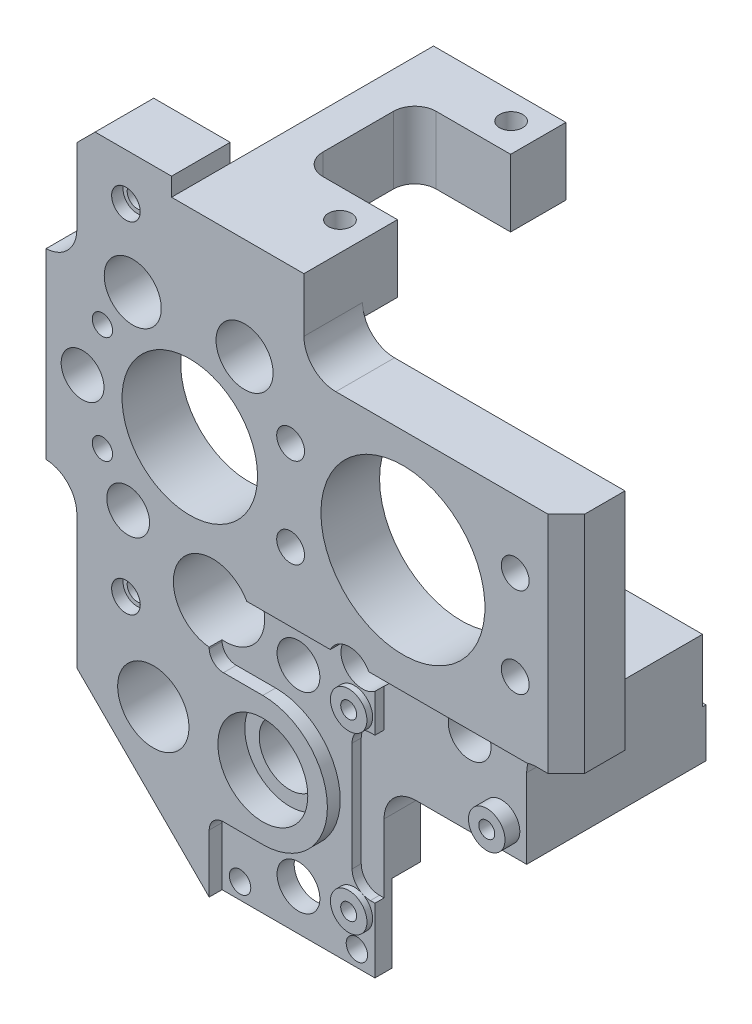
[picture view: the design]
ISO-10303-21;
HEADER;
FILE_DESCRIPTION(('STEP AP214'),'2;1');
FILE_NAME('part.step','',(''),(''),'','','');
FILE_SCHEMA(('AUTOMOTIVE_DESIGN { 1 0 10303 214 1 1 1 1 }'));
ENDSEC;
DATA;
#1=APPLICATION_CONTEXT('core data for automotive mechanical design processes');
#2=APPLICATION_PROTOCOL_DEFINITION('international standard','automotive_design',2000,#1);
#3=PRODUCT_CONTEXT('',#1,'mechanical');
#4=PRODUCT('Part','Part','',(#3));
#5=PRODUCT_RELATED_PRODUCT_CATEGORY('part','',(#4));
#6=PRODUCT_DEFINITION_FORMATION('','',#4);
#7=PRODUCT_DEFINITION_CONTEXT('part definition',#1,'design');
#8=PRODUCT_DEFINITION('design','',#6,#7);
#9=PRODUCT_DEFINITION_SHAPE('','',#8);
#10=(LENGTH_UNIT() NAMED_UNIT(*) SI_UNIT(.MILLI.,.METRE.));
#11=(NAMED_UNIT(*) PLANE_ANGLE_UNIT() SI_UNIT($,.RADIAN.));
#12=(NAMED_UNIT(*) SI_UNIT($,.STERADIAN.) SOLID_ANGLE_UNIT());
#13=UNCERTAINTY_MEASURE_WITH_UNIT(LENGTH_MEASURE(1.E-05),#10,'distance_accuracy_value','');
#14=(GEOMETRIC_REPRESENTATION_CONTEXT(3) GLOBAL_UNCERTAINTY_ASSIGNED_CONTEXT((#13)) GLOBAL_UNIT_ASSIGNED_CONTEXT((#10,
#11,#12)) REPRESENTATION_CONTEXT('',''));
#15=CARTESIAN_POINT('',(0.,0.,0.));
#16=DIRECTION('',(0.,0.,1.));
#17=DIRECTION('',(1.,0.,0.));
#18=AXIS2_PLACEMENT_3D('',#15,#16,#17);
#19=CARTESIAN_POINT('',(-16.51,-18.941358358,6.528054));
#20=DIRECTION('',(0.,0.,1.));
#21=DIRECTION('',(1.,0.,0.));
#22=AXIS2_PLACEMENT_3D('',#19,#20,#21);
#23=CYLINDRICAL_SURFACE('',#22,1.13029999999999);
#24=CARTESIAN_POINT('',(-16.51,-18.941358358,0.));
#25=DIRECTION('',(0.,0.,1.));
#26=DIRECTION('',(1.,0.,0.));
#27=AXIS2_PLACEMENT_3D('',#24,#25,#26);
#28=CIRCLE('',#27,1.13029999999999);
#29=CARTESIAN_POINT('',(-15.3797,-18.941358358,0.));
#30=VERTEX_POINT('',#29);
#31=EDGE_CURVE('E518',#30,#30,#28,.T.);
#32=ORIENTED_EDGE('',*,*,#31,.F.);
#33=EDGE_LOOP('',(#32));
#34=FACE_BOUND('',#33,.T.);
#35=CARTESIAN_POINT('',(-16.51,-18.941358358,5.258054));
#36=DIRECTION('',(0.,0.,1.));
#37=DIRECTION('',(1.,0.,0.));
#38=AXIS2_PLACEMENT_3D('',#35,#36,#37);
#39=CIRCLE('',#38,1.13029999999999);
#40=CARTESIAN_POINT('',(-15.3797,-18.941358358,5.258054));
#41=VERTEX_POINT('',#40);
#42=EDGE_CURVE('E38',#41,#41,#39,.F.);
#43=ORIENTED_EDGE('',*,*,#42,.F.);
#44=EDGE_LOOP('',(#43));
#45=FACE_BOUND('',#44,.T.);
#46=ADVANCED_FACE('F34',(#34,#45),#23,.F.);
#47=CARTESIAN_POINT('',(-16.51,18.941358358,6.528054));
#48=DIRECTION('',(0.,0.,1.));
#49=DIRECTION('',(1.,0.,0.));
#50=AXIS2_PLACEMENT_3D('',#47,#48,#49);
#51=CYLINDRICAL_SURFACE('',#50,1.13029999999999);
#52=CARTESIAN_POINT('',(-16.51,18.941358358,0.));
#53=DIRECTION('',(0.,0.,1.));
#54=DIRECTION('',(1.,0.,0.));
#55=AXIS2_PLACEMENT_3D('',#52,#53,#54);
#56=CIRCLE('',#55,1.13029999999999);
#57=CARTESIAN_POINT('',(-15.3797,18.941358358,0.));
#58=VERTEX_POINT('',#57);
#59=EDGE_CURVE('E497',#58,#58,#56,.T.);
#60=ORIENTED_EDGE('',*,*,#59,.F.);
#61=EDGE_LOOP('',(#60));
#62=FACE_BOUND('',#61,.T.);
#63=CARTESIAN_POINT('',(-16.51,18.941358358,5.258054));
#64=DIRECTION('',(0.,0.,1.));
#65=DIRECTION('',(1.,0.,0.));
#66=AXIS2_PLACEMENT_3D('',#63,#64,#65);
#67=CIRCLE('',#66,1.13029999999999);
#68=CARTESIAN_POINT('',(-15.3797,18.941358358,5.258054));
#69=VERTEX_POINT('',#68);
#70=EDGE_CURVE('E438',#69,#69,#67,.F.);
#71=ORIENTED_EDGE('',*,*,#70,.F.);
#72=EDGE_LOOP('',(#71));
#73=FACE_BOUND('',#72,.T.);
#74=ADVANCED_FACE('F962',(#62,#73),#51,.F.);
#75=CARTESIAN_POINT('',(-7.23900000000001,-15.20698,5.73405));
#76=DIRECTION('',(-1.,0.,0.));
#77=DIRECTION('',(0.,-1.,0.));
#78=AXIS2_PLACEMENT_3D('',#75,#76,#77);
#79=PLANE('',#78);
#80=DIRECTION('',(0.,0.,-1.));
#81=VECTOR('',#80,1.);
#82=CARTESIAN_POINT('',(-7.23900000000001,-36.80968,28.3966203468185));
#83=LINE('',#82,#81);
#84=CARTESIAN_POINT('',(-7.23900000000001,-36.80968,6.5278));
#85=VERTEX_POINT('',#84);
#86=CARTESIAN_POINT('',(-7.23900000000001,-36.80968,5.09905));
#87=VERTEX_POINT('',#86);
#88=EDGE_CURVE('E51',#85,#87,#83,.T.);
#89=ORIENTED_EDGE('',*,*,#88,.F.);
#90=DIRECTION('',(0.,-1.,0.));
#91=VECTOR('',#90,1.);
#92=CARTESIAN_POINT('',(-7.23900000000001,-15.20698,6.5278));
#93=LINE('',#92,#91);
#94=CARTESIAN_POINT('',(-7.239,-43.27398,6.5278));
#95=VERTEX_POINT('',#94);
#96=EDGE_CURVE('E732',#85,#95,#93,.T.);
#97=ORIENTED_EDGE('',*,*,#96,.T.);
#98=DIRECTION('',(0.,0.,1.));
#99=VECTOR('',#98,1.);
#100=CARTESIAN_POINT('',(-7.239,-43.27398,5.73405));
#101=LINE('',#100,#99);
#102=CARTESIAN_POINT('',(-7.23900000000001,-43.27398,5.09905));
#103=VERTEX_POINT('',#102);
#104=EDGE_CURVE('E734',#103,#95,#101,.T.);
#105=ORIENTED_EDGE('',*,*,#104,.F.);
#106=DIRECTION('',(0.,-1.,0.));
#107=VECTOR('',#106,1.);
#108=CARTESIAN_POINT('',(-7.23900000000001,-15.20698,5.09905));
#109=LINE('',#108,#107);
#110=EDGE_CURVE('E674',#87,#103,#109,.T.);
#111=ORIENTED_EDGE('',*,*,#110,.F.);
#112=EDGE_LOOP('',(#89,#97,#105,#111));
#113=FACE_BOUND('',#112,.T.);
#114=ADVANCED_FACE('F968',(#113),#79,.F.);
#115=DIRECTION('',(0.,0.,-1.));
#116=VECTOR('',#115,1.);
#117=CARTESIAN_POINT('',(-7.23900000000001,-19.3416122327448,28.3966203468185));
#118=LINE('',#117,#116);
#119=CARTESIAN_POINT('',(-7.23900000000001,-19.3416122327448,6.5278));
#120=VERTEX_POINT('',#119);
#121=CARTESIAN_POINT('',(-7.23900000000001,-19.3416122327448,5.09905));
#122=VERTEX_POINT('',#121);
#123=EDGE_CURVE('E495',#120,#122,#118,.T.);
#124=ORIENTED_EDGE('',*,*,#123,.T.);
#125=CARTESIAN_POINT('',(-7.23900000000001,-19.1749477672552,5.09905));
#126=VERTEX_POINT('',#125);
#127=EDGE_CURVE('E675',#126,#122,#109,.T.);
#128=ORIENTED_EDGE('',*,*,#127,.F.);
#129=DIRECTION('',(0.,0.,-1.));
#130=VECTOR('',#129,1.);
#131=CARTESIAN_POINT('',(-7.23900000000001,-19.1749477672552,0.));
#132=LINE('',#131,#130);
#133=CARTESIAN_POINT('',(-7.23900000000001,-19.1749477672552,6.5278));
#134=VERTEX_POINT('',#133);
#135=EDGE_CURVE('E653',#126,#134,#132,.F.);
#136=ORIENTED_EDGE('',*,*,#135,.T.);
#137=EDGE_CURVE('E59',#134,#120,#93,.T.);
#138=ORIENTED_EDGE('',*,*,#137,.T.);
#139=EDGE_LOOP('',(#124,#128,#136,#138));
#140=FACE_BOUND('',#139,.T.);
#141=ADVANCED_FACE('F1098',(#140),#79,.F.);
#142=CARTESIAN_POINT('',(-4.69900000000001,-15.20698,5.09905));
#143=DIRECTION('',(0.,0.,-1.));
#144=DIRECTION('',(-1.,0.,0.));
#145=AXIS2_PLACEMENT_3D('',#142,#143,#144);
#146=PLANE('',#145);
#147=CARTESIAN_POINT('',(1.27,-38.70198,5.09905));
#148=DIRECTION('',(0.,0.,-1.));
#149=DIRECTION('',(-1.,0.,0.));
#150=AXIS2_PLACEMENT_3D('',#147,#148,#149);
#151=CIRCLE('',#150,2.38124999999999);
#152=CARTESIAN_POINT('',(-1.11124999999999,-38.70198,5.09905));
#153=VERTEX_POINT('',#152);
#154=EDGE_CURVE('E625',#153,#153,#151,.T.);
#155=ORIENTED_EDGE('',*,*,#154,.T.);
#156=EDGE_LOOP('',(#155));
#157=FACE_BOUND('',#156,.T.);
#158=CARTESIAN_POINT('',(1.27,-17.36598,5.09905));
#159=DIRECTION('',(0.,0.,-1.));
#160=DIRECTION('',(-1.,0.,0.));
#161=AXIS2_PLACEMENT_3D('',#158,#159,#160);
#162=CIRCLE('',#161,2.38124999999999);
#163=CARTESIAN_POINT('',(-1.11124999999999,-17.36598,5.09905));
#164=VERTEX_POINT('',#163);
#165=EDGE_CURVE('E614',#164,#164,#162,.T.);
#166=ORIENTED_EDGE('',*,*,#165,.T.);
#167=EDGE_LOOP('',(#166));
#168=FACE_BOUND('',#167,.T.);
#169=CARTESIAN_POINT('',(-5.23000000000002,-41.49598,5.09905));
#170=DIRECTION('',(0.,0.,-1.));
#171=DIRECTION('',(-1.,0.,0.));
#172=AXIS2_PLACEMENT_3D('',#169,#170,#171);
#173=CIRCLE('',#172,1.190625);
#174=CARTESIAN_POINT('',(-4.03937500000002,-41.49598,5.09905));
#175=VERTEX_POINT('',#174);
#176=EDGE_CURVE('E557',#175,#175,#173,.T.);
#177=ORIENTED_EDGE('',*,*,#176,.T.);
#178=EDGE_LOOP('',(#177));
#179=FACE_BOUND('',#178,.T.);
#180=CARTESIAN_POINT('',(7.77,-41.49598,5.09905));
#181=DIRECTION('',(0.,0.,-1.));
#182=DIRECTION('',(-1.,0.,0.));
#183=AXIS2_PLACEMENT_3D('',#180,#181,#182);
#184=CIRCLE('',#183,1.190625);
#185=CARTESIAN_POINT('',(8.960625,-41.49598,5.09905));
#186=VERTEX_POINT('',#185);
#187=EDGE_CURVE('E551',#186,#186,#184,.T.);
#188=ORIENTED_EDGE('',*,*,#187,.T.);
#189=EDGE_LOOP('',(#188));
#190=FACE_BOUND('',#189,.T.);
#191=CARTESIAN_POINT('',(-5.65150000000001,-36.80968,5.09905));
#192=DIRECTION('',(0.,0.,-1.));
#193=DIRECTION('',(1.,0.,0.));
#194=AXIS2_PLACEMENT_3D('',#191,#192,#193);
#195=CIRCLE('',#194,1.5875);
#196=CARTESIAN_POINT('',(-5.65150000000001,-35.22218,5.09905));
#197=VERTEX_POINT('',#196);
#198=EDGE_CURVE('E470',#87,#197,#195,.T.);
#199=ORIENTED_EDGE('',*,*,#198,.F.);
#200=ORIENTED_EDGE('',*,*,#110,.T.);
#201=DIRECTION('',(1.,0.,0.));
#202=VECTOR('',#201,1.);
#203=CARTESIAN_POINT('',(-7.23900000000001,-43.27398,5.09905));
#204=LINE('',#203,#202);
#205=CARTESIAN_POINT('',(9.77899999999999,-43.27398,5.09905));
#206=VERTEX_POINT('',#205);
#207=EDGE_CURVE('E677',#103,#206,#204,.T.);
#208=ORIENTED_EDGE('',*,*,#207,.T.);
#209=DIRECTION('',(0.,-1.,0.));
#210=VECTOR('',#209,1.);
#211=CARTESIAN_POINT('',(9.779,-24.892,5.09905));
#212=LINE('',#211,#210);
#213=CARTESIAN_POINT('',(9.779,-36.0635563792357,5.09905));
#214=VERTEX_POINT('',#213);
#215=EDGE_CURVE('E687',#214,#206,#212,.T.);
#216=ORIENTED_EDGE('',*,*,#215,.F.);
#217=DIRECTION('',(1.,0.,0.));
#218=VECTOR('',#217,1.);
#219=CARTESIAN_POINT('',(9.27099999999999,-36.0635563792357,5.09905));
#220=LINE('',#219,#218);
#221=CARTESIAN_POINT('',(9.27099999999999,-36.0635563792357,5.09905));
#222=VERTEX_POINT('',#221);
#223=EDGE_CURVE('E527',#222,#214,#220,.T.);
#224=ORIENTED_EDGE('',*,*,#223,.F.);
#225=CARTESIAN_POINT('',(9.27099999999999,-34.0315563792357,5.09905));
#226=DIRECTION('',(0.,0.,1.));
#227=DIRECTION('',(-1.,0.,0.));
#228=AXIS2_PLACEMENT_3D('',#225,#226,#227);
#229=CIRCLE('',#228,2.032);
#230=CARTESIAN_POINT('',(8.38199999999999,-35.8587681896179,5.09905));
#231=VERTEX_POINT('',#230);
#232=EDGE_CURVE('E524',#231,#222,#229,.T.);
#233=ORIENTED_EDGE('',*,*,#232,.F.);
#234=CARTESIAN_POINT('',(7.49299999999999,-37.68598,5.09905));
#235=DIRECTION('',(0.,0.,1.));
#236=DIRECTION('',(1.,0.,0.));
#237=AXIS2_PLACEMENT_3D('',#234,#235,#236);
#238=CIRCLE('',#237,2.03199999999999);
#239=EDGE_CURVE('E668',#231,#231,#238,.T.);
#240=ORIENTED_EDGE('',*,*,#239,.F.);
#241=CARTESIAN_POINT('',(7.239,-34.0315563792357,5.09905));
#242=VERTEX_POINT('',#241);
#243=EDGE_CURVE('E525',#242,#231,#229,.T.);
#244=ORIENTED_EDGE('',*,*,#243,.F.);
#245=DIRECTION('',(0.,-1.,0.));
#246=VECTOR('',#245,1.);
#247=CARTESIAN_POINT('',(7.239,-34.0315563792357,5.09905));
#248=LINE('',#247,#246);
#249=CARTESIAN_POINT('',(7.239,-21.9094036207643,5.09905));
#250=VERTEX_POINT('',#249);
#251=EDGE_CURVE('E521',#250,#242,#248,.T.);
#252=ORIENTED_EDGE('',*,*,#251,.F.);
#253=CARTESIAN_POINT('',(9.27099999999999,-21.9094036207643,5.09905));
#254=DIRECTION('',(0.,0.,1.));
#255=DIRECTION('',(-1.,0.,0.));
#256=AXIS2_PLACEMENT_3D('',#253,#254,#255);
#257=CIRCLE('',#256,2.032);
#258=CARTESIAN_POINT('',(8.382,-20.0821918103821,5.09905));
#259=VERTEX_POINT('',#258);
#260=EDGE_CURVE('E517',#259,#250,#257,.T.);
#261=ORIENTED_EDGE('',*,*,#260,.F.);
#262=CARTESIAN_POINT('',(7.493,-18.25498,5.09905));
#263=DIRECTION('',(0.,0.,1.));
#264=DIRECTION('',(1.,0.,0.));
#265=AXIS2_PLACEMENT_3D('',#262,#263,#264);
#266=CIRCLE('',#265,2.032);
#267=EDGE_CURVE('E671',#259,#259,#266,.T.);
#268=ORIENTED_EDGE('',*,*,#267,.F.);
#269=CARTESIAN_POINT('',(9.27099999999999,-19.8774036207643,5.09905));
#270=VERTEX_POINT('',#269);
#271=EDGE_CURVE('E519',#270,#259,#257,.T.);
#272=ORIENTED_EDGE('',*,*,#271,.F.);
#273=DIRECTION('',(-1.,0.,0.));
#274=VECTOR('',#273,1.);
#275=CARTESIAN_POINT('',(9.27099999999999,-19.8774036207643,5.09905));
#276=LINE('',#275,#274);
#277=CARTESIAN_POINT('',(9.779,-19.8774036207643,5.09905));
#278=VERTEX_POINT('',#277);
#279=EDGE_CURVE('E514',#278,#270,#276,.T.);
#280=ORIENTED_EDGE('',*,*,#279,.F.);
#281=CARTESIAN_POINT('',(9.779,-15.6444041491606,5.09905));
#282=VERTEX_POINT('',#281);
#283=EDGE_CURVE('E683',#282,#278,#212,.T.);
#284=ORIENTED_EDGE('',*,*,#283,.F.);
#285=CARTESIAN_POINT('',(8.382,-13.716,5.09905));
#286=DIRECTION('',(0.,0.,-1.));
#287=DIRECTION('',(-1.,0.,0.));
#288=AXIS2_PLACEMENT_3D('',#285,#286,#287);
#289=CIRCLE('',#288,2.38124999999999);
#290=CARTESIAN_POINT('',(6.24426554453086,-12.66698,5.09905));
#291=VERTEX_POINT('',#290);
#292=EDGE_CURVE('E606',#282,#291,#289,.T.);
#293=ORIENTED_EDGE('',*,*,#292,.T.);
#294=DIRECTION('',(-1.,0.,0.));
#295=VECTOR('',#294,1.);
#296=CARTESIAN_POINT('',(32.512,-12.66698,5.09905));
#297=LINE('',#296,#295);
#298=CARTESIAN_POINT('',(-3.0636093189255,-12.66698,5.09905));
#299=VERTEX_POINT('',#298);
#300=EDGE_CURVE('E680',#291,#299,#297,.T.);
#301=ORIENTED_EDGE('',*,*,#300,.T.);
#302=CARTESIAN_POINT('',(-6.858,-14.82598,5.09905));
#303=DIRECTION('',(0.,0.,-1.));
#304=DIRECTION('',(-1.,0.,0.));
#305=AXIS2_PLACEMENT_3D('',#302,#303,#304);
#306=CIRCLE('',#305,4.365625);
#307=EDGE_CURVE('E1407',#299,#126,#306,.T.);
#308=ORIENTED_EDGE('',*,*,#307,.T.);
#309=ORIENTED_EDGE('',*,*,#127,.T.);
#310=CARTESIAN_POINT('',(-5.6536886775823,-19.25828,5.09905));
#311=DIRECTION('',(0.,0.,-1.));
#312=DIRECTION('',(1.,0.,0.));
#313=AXIS2_PLACEMENT_3D('',#310,#311,#312);
#314=CIRCLE('',#313,1.5875);
#315=CARTESIAN_POINT('',(-5.6536886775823,-20.84578,5.09905));
#316=VERTEX_POINT('',#315);
#317=EDGE_CURVE('E467',#316,#122,#314,.T.);
#318=ORIENTED_EDGE('',*,*,#317,.F.);
#319=DIRECTION('',(-1.,0.,0.));
#320=VECTOR('',#319,1.);
#321=CARTESIAN_POINT('',(-1.27,-20.84578,5.09905));
#322=LINE('',#321,#320);
#323=CARTESIAN_POINT('',(-1.27,-20.84578,5.09905));
#324=VERTEX_POINT('',#323);
#325=EDGE_CURVE('E479',#324,#316,#322,.T.);
#326=ORIENTED_EDGE('',*,*,#325,.F.);
#327=CARTESIAN_POINT('',(-1.27,-28.03398,5.09905));
#328=DIRECTION('',(0.,0.,1.));
#329=DIRECTION('',(1.,0.,0.));
#330=AXIS2_PLACEMENT_3D('',#327,#328,#329);
#331=CIRCLE('',#330,7.1882);
#332=CARTESIAN_POINT('',(-1.27,-35.22218,5.09905));
#333=VERTEX_POINT('',#332);
#334=EDGE_CURVE('E476',#333,#324,#331,.T.);
#335=ORIENTED_EDGE('',*,*,#334,.F.);
#336=DIRECTION('',(1.,0.,0.));
#337=VECTOR('',#336,1.);
#338=CARTESIAN_POINT('',(-1.27,-35.22218,5.09905));
#339=LINE('',#338,#337);
#340=EDGE_CURVE('E473',#197,#333,#339,.T.);
#341=ORIENTED_EDGE('',*,*,#340,.F.);
#342=EDGE_LOOP('',(#199,#200,#208,#216,#224,#233,#240,#244,#252,#261,#268,#272,#280,#284,#293,
#301,#308,#309,#318,#326,#335,#341));
#343=FACE_BOUND('',#342,.T.);
#344=ADVANCED_FACE('F957',(#157,#168,#179,#190,#343),#146,.F.);
#345=CARTESIAN_POINT('',(9.779,-24.892,6.5278));
#346=DIRECTION('',(-1.,0.,0.));
#347=DIRECTION('',(0.,-1.,0.));
#348=AXIS2_PLACEMENT_3D('',#345,#346,#347);
#349=PLANE('',#348);
#350=ORIENTED_EDGE('',*,*,#283,.T.);
#351=DIRECTION('',(0.,0.,1.));
#352=VECTOR('',#351,1.);
#353=CARTESIAN_POINT('',(9.779,-19.8774036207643,-12.3011845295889));
#354=LINE('',#353,#352);
#355=CARTESIAN_POINT('',(9.779,-19.8774036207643,4.08305));
#356=VERTEX_POINT('',#355);
#357=EDGE_CURVE('E529',#356,#278,#354,.T.);
#358=ORIENTED_EDGE('',*,*,#357,.F.);
#359=DIRECTION('',(0.,-1.,0.));
#360=VECTOR('',#359,1.);
#361=CARTESIAN_POINT('',(9.779,-31.5182040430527,4.08305));
#362=LINE('',#361,#360);
#363=CARTESIAN_POINT('',(9.779,-15.6444041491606,4.08305));
#364=VERTEX_POINT('',#363);
#365=EDGE_CURVE('E567',#364,#356,#362,.T.);
#366=ORIENTED_EDGE('',*,*,#365,.F.);
#367=DIRECTION('',(0.,0.,1.));
#368=VECTOR('',#367,1.);
#369=CARTESIAN_POINT('',(9.779,-15.6444041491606,6.5278));
#370=LINE('',#369,#368);
#371=EDGE_CURVE('E43',#282,#364,#370,.F.);
#372=ORIENTED_EDGE('',*,*,#371,.F.);
#373=EDGE_LOOP('',(#350,#358,#366,#372));
#374=FACE_BOUND('',#373,.T.);
#375=ADVANCED_FACE('F951',(#374),#349,.F.);
#376=CARTESIAN_POINT('',(-25.4,-43.27398,6.5278));
#377=DIRECTION('',(0.,0.,1.));
#378=DIRECTION('',(1.,0.,0.));
#379=AXIS2_PLACEMENT_3D('',#376,#377,#378);
#380=PLANE('',#379);
#381=CARTESIAN_POINT('',(-16.51,-18.941358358,6.5278));
#382=DIRECTION('',(0.,0.,1.));
#383=DIRECTION('',(1.,0.,0.));
#384=AXIS2_PLACEMENT_3D('',#381,#382,#383);
#385=CIRCLE('',#384,1.6002);
#386=CARTESIAN_POINT('',(-14.9098,-18.941358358,6.5278));
#387=VERTEX_POINT('',#386);
#388=EDGE_CURVE('E12',#387,#387,#385,.T.);
#389=ORIENTED_EDGE('',*,*,#388,.F.);
#390=EDGE_LOOP('',(#389));
#391=FACE_BOUND('',#390,.T.);
#392=CARTESIAN_POINT('',(-15.748,10.795,6.5278));
#393=DIRECTION('',(0.,0.,-1.));
#394=DIRECTION('',(-1.,0.,0.));
#395=AXIS2_PLACEMENT_3D('',#392,#393,#394);
#396=CIRCLE('',#395,3.175);
#397=CARTESIAN_POINT('',(-18.923,10.795,6.5278));
#398=VERTEX_POINT('',#397);
#399=EDGE_CURVE('E629',#398,#398,#396,.T.);
#400=ORIENTED_EDGE('',*,*,#399,.T.);
#401=EDGE_LOOP('',(#400));
#402=FACE_BOUND('',#401,.T.);
#403=CARTESIAN_POINT('',(-3.302,10.795,6.5278));
#404=DIRECTION('',(0.,0.,-1.));
#405=DIRECTION('',(-1.,0.,0.));
#406=AXIS2_PLACEMENT_3D('',#403,#404,#405);
#407=CIRCLE('',#406,3.175);
#408=CARTESIAN_POINT('',(-6.477,10.795,6.5278));
#409=VERTEX_POINT('',#408);
#410=EDGE_CURVE('E635',#409,#409,#407,.T.);
#411=ORIENTED_EDGE('',*,*,#410,.T.);
#412=EDGE_LOOP('',(#411));
#413=FACE_BOUND('',#412,.T.);
#414=CARTESIAN_POINT('',(-13.462,-28.03398,6.5278));
#415=DIRECTION('',(0.,0.,-1.));
#416=DIRECTION('',(-1.,0.,0.));
#417=AXIS2_PLACEMENT_3D('',#414,#415,#416);
#418=CIRCLE('',#417,3.96875);
#419=CARTESIAN_POINT('',(-17.43075,-28.03398,6.5278));
#420=VERTEX_POINT('',#419);
#421=EDGE_CURVE('E641',#420,#420,#418,.T.);
#422=ORIENTED_EDGE('',*,*,#421,.T.);
#423=EDGE_LOOP('',(#422));
#424=FACE_BOUND('',#423,.T.);
#425=CARTESIAN_POINT('',(-9.398,0.,6.5278));
#426=DIRECTION('',(0.,0.,1.));
#427=DIRECTION('',(1.,0.,0.));
#428=AXIS2_PLACEMENT_3D('',#425,#426,#427);
#429=CIRCLE('',#428,7.540625);
#430=CARTESIAN_POINT('',(-1.857375,0.,6.5278));
#431=VERTEX_POINT('',#430);
#432=EDGE_CURVE('E658',#431,#431,#429,.T.);
#433=ORIENTED_EDGE('',*,*,#432,.F.);
#434=EDGE_LOOP('',(#433));
#435=FACE_BOUND('',#434,.T.);
#436=CARTESIAN_POINT('',(26.823,5.,6.5278));
#437=DIRECTION('',(0.,0.,1.));
#438=DIRECTION('',(1.,0.,0.));
#439=AXIS2_PLACEMENT_3D('',#436,#437,#438);
#440=CIRCLE('',#439,1.54999999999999);
#441=CARTESIAN_POINT('',(28.373,5.,6.5278));
#442=VERTEX_POINT('',#441);
#443=EDGE_CURVE('E757',#442,#442,#440,.T.);
#444=ORIENTED_EDGE('',*,*,#443,.F.);
#445=EDGE_LOOP('',(#444));
#446=FACE_BOUND('',#445,.T.);
#447=CARTESIAN_POINT('',(1.82299999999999,-5.,6.5278));
#448=DIRECTION('',(0.,0.,1.));
#449=DIRECTION('',(1.,0.,0.));
#450=AXIS2_PLACEMENT_3D('',#447,#448,#449);
#451=CIRCLE('',#450,1.54999999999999);
#452=CARTESIAN_POINT('',(3.37299999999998,-5.,6.5278));
#453=VERTEX_POINT('',#452);
#454=EDGE_CURVE('E753',#453,#453,#451,.T.);
#455=ORIENTED_EDGE('',*,*,#454,.F.);
#456=EDGE_LOOP('',(#455));
#457=FACE_BOUND('',#456,.T.);
#458=CARTESIAN_POINT('',(1.82299999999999,5.,6.5278));
#459=DIRECTION('',(0.,0.,1.));
#460=DIRECTION('',(1.,0.,0.));
#461=AXIS2_PLACEMENT_3D('',#458,#459,#460);
#462=CIRCLE('',#461,1.54999999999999);
#463=CARTESIAN_POINT('',(3.37299999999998,5.,6.5278));
#464=VERTEX_POINT('',#463);
#465=EDGE_CURVE('E749',#464,#464,#462,.T.);
#466=ORIENTED_EDGE('',*,*,#465,.F.);
#467=EDGE_LOOP('',(#466));
#468=FACE_BOUND('',#467,.T.);
#469=CARTESIAN_POINT('',(26.823,-5.,6.5278));
#470=DIRECTION('',(0.,0.,1.));
#471=DIRECTION('',(1.,0.,0.));
#472=AXIS2_PLACEMENT_3D('',#469,#470,#471);
#473=CIRCLE('',#472,1.54999999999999);
#474=CARTESIAN_POINT('',(28.373,-5.,6.5278));
#475=VERTEX_POINT('',#474);
#476=EDGE_CURVE('E745',#475,#475,#473,.T.);
#477=ORIENTED_EDGE('',*,*,#476,.F.);
#478=EDGE_LOOP('',(#477));
#479=FACE_BOUND('',#478,.T.);
#480=CARTESIAN_POINT('',(-19.1232329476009,5.96899994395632,6.5278));
#481=DIRECTION('',(0.,0.,1.));
#482=DIRECTION('',(1.,0.,0.));
#483=AXIS2_PLACEMENT_3D('',#480,#481,#482);
#484=CIRCLE('',#483,1.13029999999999);
#485=CARTESIAN_POINT('',(-17.9929329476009,5.96899994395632,6.5278));
#486=VERTEX_POINT('',#485);
#487=EDGE_CURVE('E741',#486,#486,#484,.T.);
#488=ORIENTED_EDGE('',*,*,#487,.F.);
#489=EDGE_LOOP('',(#488));
#490=FACE_BOUND('',#489,.T.);
#491=CARTESIAN_POINT('',(-19.1232329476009,-5.96900005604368,6.5278));
#492=DIRECTION('',(0.,0.,1.));
#493=DIRECTION('',(1.,0.,0.));
#494=AXIS2_PLACEMENT_3D('',#491,#492,#493);
#495=CIRCLE('',#494,1.13029999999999);
#496=CARTESIAN_POINT('',(-17.9929329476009,-5.96900005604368,6.5278));
#497=VERTEX_POINT('',#496);
#498=EDGE_CURVE('E737',#497,#497,#495,.T.);
#499=ORIENTED_EDGE('',*,*,#498,.F.);
#500=EDGE_LOOP('',(#499));
#501=FACE_BOUND('',#500,.T.);
#502=CARTESIAN_POINT('',(14.323,0.,6.5278));
#503=DIRECTION('',(0.,0.,-1.));
#504=DIRECTION('',(-1.,0.,0.));
#505=AXIS2_PLACEMENT_3D('',#502,#503,#504);
#506=CIRCLE('',#505,9.128125);
#507=CARTESIAN_POINT('',(5.19487499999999,0.,6.5278));
#508=VERTEX_POINT('',#507);
#509=EDGE_CURVE('E662',#508,#508,#506,.T.);
#510=ORIENTED_EDGE('',*,*,#509,.T.);
#511=EDGE_LOOP('',(#510));
#512=FACE_BOUND('',#511,.T.);
#513=CARTESIAN_POINT('',(-21.336,0.,6.5278));
#514=DIRECTION('',(0.,0.,1.));
#515=DIRECTION('',(1.,0.,0.));
#516=AXIS2_PLACEMENT_3D('',#513,#514,#515);
#517=CIRCLE('',#516,2.38124999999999);
#518=CARTESIAN_POINT('',(-18.95475,0.,6.5278));
#519=VERTEX_POINT('',#518);
#520=EDGE_CURVE('E624',#519,#519,#517,.T.);
#521=ORIENTED_EDGE('',*,*,#520,.F.);
#522=EDGE_LOOP('',(#521));
#523=FACE_BOUND('',#522,.T.);
#524=CARTESIAN_POINT('',(-16.256,-10.50798,6.5278));
#525=DIRECTION('',(0.,0.,1.));
#526=DIRECTION('',(1.,0.,0.));
#527=AXIS2_PLACEMENT_3D('',#524,#525,#526);
#528=CIRCLE('',#527,2.38124999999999);
#529=CARTESIAN_POINT('',(-13.87475,-10.50798,6.5278));
#530=VERTEX_POINT('',#529);
#531=EDGE_CURVE('E617',#530,#530,#528,.T.);
#532=ORIENTED_EDGE('',*,*,#531,.F.);
#533=EDGE_LOOP('',(#532));
#534=FACE_BOUND('',#533,.T.);
#535=DIRECTION('',(1.,0.,0.));
#536=VECTOR('',#535,1.);
#537=CARTESIAN_POINT('',(3.302,22.098,6.5278));
#538=LINE('',#537,#536);
#539=CARTESIAN_POINT('',(-11.43,22.098,6.5278));
#540=VERTEX_POINT('',#539);
#541=CARTESIAN_POINT('',(3.302,22.098,6.5278));
#542=VERTEX_POINT('',#541);
#543=EDGE_CURVE('E801',#540,#542,#538,.T.);
#544=ORIENTED_EDGE('',*,*,#543,.F.);
#545=DIRECTION('',(0.,1.,0.));
#546=VECTOR('',#545,1.);
#547=CARTESIAN_POINT('',(-11.43,-7.50040104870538,6.5278));
#548=LINE('',#547,#546);
#549=CARTESIAN_POINT('',(-11.43,24.13,6.5278));
#550=VERTEX_POINT('',#549);
#551=EDGE_CURVE('E591',#540,#550,#548,.T.);
#552=ORIENTED_EDGE('',*,*,#551,.T.);
#553=DIRECTION('',(-1.,0.,0.));
#554=VECTOR('',#553,1.);
#555=CARTESIAN_POINT('',(-25.4,24.13,6.5278));
#556=LINE('',#555,#554);
#557=CARTESIAN_POINT('',(-19.939,24.13,6.5278));
#558=VERTEX_POINT('',#557);
#559=EDGE_CURVE('E828',#550,#558,#556,.T.);
#560=ORIENTED_EDGE('',*,*,#559,.T.);
#561=DIRECTION('',(0.707106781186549,0.707106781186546,0.));
#562=VECTOR('',#561,1.);
#563=CARTESIAN_POINT('',(-56.37149,-12.3024899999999,6.5278));
#564=LINE('',#563,#562);
#565=CARTESIAN_POINT('',(-21.971,22.098,6.5278));
#566=VERTEX_POINT('',#565);
#567=EDGE_CURVE('E1405',#558,#566,#564,.F.);
#568=ORIENTED_EDGE('',*,*,#567,.T.);
#569=DIRECTION('',(0.,-1.,0.));
#570=VECTOR('',#569,1.);
#571=CARTESIAN_POINT('',(-21.971,24.13,6.5278));
#572=LINE('',#571,#570);
#573=CARTESIAN_POINT('',(-21.971,13.7137313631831,6.5278));
#574=VERTEX_POINT('',#573);
#575=EDGE_CURVE('E715',#566,#574,#572,.T.);
#576=ORIENTED_EDGE('',*,*,#575,.T.);
#577=CARTESIAN_POINT('',(-25.527,13.7137313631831,6.5278));
#578=DIRECTION('',(0.,0.,1.));
#579=DIRECTION('',(1.,0.,0.));
#580=AXIS2_PLACEMENT_3D('',#577,#578,#579);
#581=CIRCLE('',#580,3.556);
#582=CARTESIAN_POINT('',(-25.4,10.1599999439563,6.5278));
#583=VERTEX_POINT('',#582);
#584=EDGE_CURVE('E1498',#574,#583,#581,.F.);
#585=ORIENTED_EDGE('',*,*,#584,.T.);
#586=DIRECTION('',(0.,-1.,0.));
#587=VECTOR('',#586,1.);
#588=CARTESIAN_POINT('',(-25.4,24.13,6.5278));
#589=LINE('',#588,#587);
#590=CARTESIAN_POINT('',(-25.4,-10.1600000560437,6.5278));
#591=VERTEX_POINT('',#590);
#592=EDGE_CURVE('E1261',#583,#591,#589,.T.);
#593=ORIENTED_EDGE('',*,*,#592,.T.);
#594=CARTESIAN_POINT('',(-25.527,-13.7137314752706,6.5278));
#595=DIRECTION('',(0.,0.,1.));
#596=DIRECTION('',(1.,0.,0.));
#597=AXIS2_PLACEMENT_3D('',#594,#595,#596);
#598=CIRCLE('',#597,3.556);
#599=CARTESIAN_POINT('',(-21.971,-13.7137314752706,6.5278));
#600=VERTEX_POINT('',#599);
#601=EDGE_CURVE('E1346',#591,#600,#598,.F.);
#602=ORIENTED_EDGE('',*,*,#601,.T.);
#603=DIRECTION('',(0.,-1.,0.));
#604=VECTOR('',#603,1.);
#605=CARTESIAN_POINT('',(-21.971,-43.27398,6.5278));
#606=LINE('',#605,#604);
#607=CARTESIAN_POINT('',(-21.971,-28.54198,6.5278));
#608=VERTEX_POINT('',#607);
#609=EDGE_CURVE('E722',#600,#608,#606,.T.);
#610=ORIENTED_EDGE('',*,*,#609,.T.);
#611=DIRECTION('',(-0.707106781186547,0.707106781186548,0.));
#612=VECTOR('',#611,1.);
#613=CARTESIAN_POINT('',(-16.3195,-34.19348,6.5278));
#614=LINE('',#613,#612);
#615=EDGE_CURVE('E1190',#608,#95,#614,.F.);
#616=ORIENTED_EDGE('',*,*,#615,.T.);
#617=ORIENTED_EDGE('',*,*,#96,.F.);
#618=CARTESIAN_POINT('',(-5.65150000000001,-36.80968,6.5278));
#619=DIRECTION('',(0.,0.,1.));
#620=DIRECTION('',(1.,0.,0.));
#621=AXIS2_PLACEMENT_3D('',#618,#619,#620);
#622=CIRCLE('',#621,1.5875);
#623=CARTESIAN_POINT('',(-5.65150000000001,-35.22218,6.52780000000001));
#624=VERTEX_POINT('',#623);
#625=EDGE_CURVE('E461',#85,#624,#622,.F.);
#626=ORIENTED_EDGE('',*,*,#625,.T.);
#627=DIRECTION('',(1.,0.,0.));
#628=VECTOR('',#627,1.);
#629=CARTESIAN_POINT('',(-1.27,-35.22218,6.5278));
#630=LINE('',#629,#628);
#631=CARTESIAN_POINT('',(-1.27,-35.22218,6.52780000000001));
#632=VERTEX_POINT('',#631);
#633=EDGE_CURVE('E458',#624,#632,#630,.T.);
#634=ORIENTED_EDGE('',*,*,#633,.T.);
#635=CARTESIAN_POINT('',(-1.27,-28.03398,6.5278));
#636=DIRECTION('',(0.,0.,1.));
#637=DIRECTION('',(1.,0.,0.));
#638=AXIS2_PLACEMENT_3D('',#635,#636,#637);
#639=CIRCLE('',#638,7.1882);
#640=CARTESIAN_POINT('',(-1.27,-20.84578,6.52780000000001));
#641=VERTEX_POINT('',#640);
#642=EDGE_CURVE('E454',#632,#641,#639,.T.);
#643=ORIENTED_EDGE('',*,*,#642,.T.);
#644=DIRECTION('',(-1.,0.,0.));
#645=VECTOR('',#644,1.);
#646=CARTESIAN_POINT('',(-1.27,-20.84578,6.5278));
#647=LINE('',#646,#645);
#648=CARTESIAN_POINT('',(-5.6536886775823,-20.84578,6.5278));
#649=VERTEX_POINT('',#648);
#650=EDGE_CURVE('E451',#641,#649,#647,.T.);
#651=ORIENTED_EDGE('',*,*,#650,.T.);
#652=CARTESIAN_POINT('',(-5.6536886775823,-19.25828,6.5278));
#653=DIRECTION('',(0.,0.,1.));
#654=DIRECTION('',(1.,0.,0.));
#655=AXIS2_PLACEMENT_3D('',#652,#653,#654);
#656=CIRCLE('',#655,1.5875);
#657=EDGE_CURVE('E464',#649,#120,#656,.F.);
#658=ORIENTED_EDGE('',*,*,#657,.T.);
#659=ORIENTED_EDGE('',*,*,#137,.F.);
#660=CARTESIAN_POINT('',(-6.858,-14.82598,6.5278));
#661=DIRECTION('',(0.,0.,-1.));
#662=DIRECTION('',(-1.,0.,0.));
#663=AXIS2_PLACEMENT_3D('',#660,#661,#662);
#664=CIRCLE('',#663,4.365625);
#665=CARTESIAN_POINT('',(-3.0636093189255,-12.66698,6.5278));
#666=VERTEX_POINT('',#665);
#667=EDGE_CURVE('E650',#134,#666,#664,.T.);
#668=ORIENTED_EDGE('',*,*,#667,.T.);
#669=DIRECTION('',(-1.,0.,0.));
#670=VECTOR('',#669,1.);
#671=CARTESIAN_POINT('',(-4.69900000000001,-12.66698,6.5278));
#672=LINE('',#671,#670);
#673=CARTESIAN_POINT('',(6.24426554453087,-12.66698,6.5278));
#674=VERTEX_POINT('',#673);
#675=EDGE_CURVE('E728',#674,#666,#672,.T.);
#676=ORIENTED_EDGE('',*,*,#675,.F.);
#677=CARTESIAN_POINT('',(8.382,-13.716,6.5278));
#678=DIRECTION('',(0.,0.,1.));
#679=DIRECTION('',(1.,0.,0.));
#680=AXIS2_PLACEMENT_3D('',#677,#678,#679);
#681=CIRCLE('',#680,2.38124999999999);
#682=CARTESIAN_POINT('',(10.5197344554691,-12.66698,6.5278));
#683=VERTEX_POINT('',#682);
#684=EDGE_CURVE('E603',#683,#674,#681,.T.);
#685=ORIENTED_EDGE('',*,*,#684,.F.);
#686=CARTESIAN_POINT('',(28.1331158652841,-12.66698,6.5278));
#687=VERTEX_POINT('',#686);
#688=EDGE_CURVE('E729',#687,#683,#672,.T.);
#689=ORIENTED_EDGE('',*,*,#688,.F.);
#690=CARTESIAN_POINT('',(29.21,-16.056,6.5278));
#691=DIRECTION('',(0.,0.,1.));
#692=DIRECTION('',(1.,0.,0.));
#693=AXIS2_PLACEMENT_3D('',#690,#691,#692);
#694=CIRCLE('',#693,3.556);
#695=CARTESIAN_POINT('',(29.21,-12.5,6.5278));
#696=VERTEX_POINT('',#695);
#697=EDGE_CURVE('E1311',#687,#696,#694,.F.);
#698=ORIENTED_EDGE('',*,*,#697,.T.);
#699=DIRECTION('',(1.,0.,0.));
#700=VECTOR('',#699,1.);
#701=CARTESIAN_POINT('',(32.512,-12.5,6.5278));
#702=LINE('',#701,#700);
#703=CARTESIAN_POINT('',(30.48,-12.5,6.5278));
#704=VERTEX_POINT('',#703);
#705=EDGE_CURVE('E1252',#696,#704,#702,.T.);
#706=ORIENTED_EDGE('',*,*,#705,.T.);
#707=DIRECTION('',(0.,1.,0.));
#708=VECTOR('',#707,1.);
#709=CARTESIAN_POINT('',(30.48,12.5,6.5278));
#710=LINE('',#709,#708);
#711=CARTESIAN_POINT('',(30.48,12.5,6.5278));
#712=VERTEX_POINT('',#711);
#713=EDGE_CURVE('E1198',#704,#712,#710,.T.);
#714=ORIENTED_EDGE('',*,*,#713,.T.);
#715=DIRECTION('',(-1.,0.,0.));
#716=VECTOR('',#715,1.);
#717=CARTESIAN_POINT('',(32.512,12.5,6.5278));
#718=LINE('',#717,#716);
#719=CARTESIAN_POINT('',(6.858,12.5,6.5278));
#720=VERTEX_POINT('',#719);
#721=EDGE_CURVE('E1320',#712,#720,#718,.T.);
#722=ORIENTED_EDGE('',*,*,#721,.T.);
#723=CARTESIAN_POINT('',(6.858,16.056,6.5278));
#724=DIRECTION('',(0.,0.,1.));
#725=DIRECTION('',(1.,0.,0.));
#726=AXIS2_PLACEMENT_3D('',#723,#724,#725);
#727=CIRCLE('',#726,3.556);
#728=CARTESIAN_POINT('',(3.302,16.056,6.5278));
#729=VERTEX_POINT('',#728);
#730=EDGE_CURVE('E1342',#720,#729,#727,.F.);
#731=ORIENTED_EDGE('',*,*,#730,.T.);
#732=DIRECTION('',(0.,-1.,0.));
#733=VECTOR('',#732,1.);
#734=CARTESIAN_POINT('',(3.302,24.13,6.5278));
#735=LINE('',#734,#733);
#736=EDGE_CURVE('E1276',#542,#729,#735,.T.);
#737=ORIENTED_EDGE('',*,*,#736,.F.);
#738=EDGE_LOOP('',(#544,#552,#560,#568,#576,#585,#593,#602,#610,#616,#617,#626,#634,#643,#651,
#658,#659,#668,#676,#685,#689,#698,#706,#714,#722,#731,#737));
#739=FACE_BOUND('',#738,.T.);
#740=CARTESIAN_POINT('',(-16.51,18.941358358,6.5278));
#741=DIRECTION('',(0.,0.,1.));
#742=DIRECTION('',(1.,0.,0.));
#743=AXIS2_PLACEMENT_3D('',#740,#741,#742);
#744=CIRCLE('',#743,1.6002);
#745=CARTESIAN_POINT('',(-14.9098,18.941358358,6.5278));
#746=VERTEX_POINT('',#745);
#747=EDGE_CURVE('E547',#746,#746,#744,.T.);
#748=ORIENTED_EDGE('',*,*,#747,.F.);
#749=EDGE_LOOP('',(#748));
#750=FACE_BOUND('',#749,.T.);
#751=CARTESIAN_POINT('',(-1.27,-28.03398,6.5278));
#752=DIRECTION('',(0.,0.,1.));
#753=DIRECTION('',(1.,0.,0.));
#754=AXIS2_PLACEMENT_3D('',#751,#752,#753);
#755=CIRCLE('',#754,5.0038);
#756=CARTESIAN_POINT('',(3.7338,-28.03398,6.5278));
#757=VERTEX_POINT('',#756);
#758=EDGE_CURVE('E455',#757,#757,#755,.T.);
#759=ORIENTED_EDGE('',*,*,#758,.F.);
#760=EDGE_LOOP('',(#759));
#761=FACE_BOUND('',#760,.T.);
#762=ADVANCED_FACE('F946',(#391,#402,#413,#424,#435,#446,#457,#468,#479,#490,#501,#512,#523,
#534,#739,#750,#761),#380,.T.);
#763=CARTESIAN_POINT('',(25.654,-24.892,6.5278));
#764=DIRECTION('',(0.,1.,0.));
#765=DIRECTION('',(0.,0.,1.));
#766=AXIS2_PLACEMENT_3D('',#763,#764,#765);
#767=PLANE('',#766);
#768=DIRECTION('',(1.,0.,0.));
#769=VECTOR('',#768,1.);
#770=CARTESIAN_POINT('',(25.654,-24.892,4.08305));
#771=LINE('',#770,#769);
#772=CARTESIAN_POINT('',(13.335,-24.892,4.08305));
#773=VERTEX_POINT('',#772);
#774=CARTESIAN_POINT('',(25.654,-24.892,4.08305));
#775=VERTEX_POINT('',#774);
#776=EDGE_CURVE('E575',#773,#775,#771,.T.);
#777=ORIENTED_EDGE('',*,*,#776,.F.);
#778=DIRECTION('',(0.,0.,-1.));
#779=VECTOR('',#778,1.);
#780=CARTESIAN_POINT('',(13.335,-24.892,0.));
#781=LINE('',#780,#779);
#782=CARTESIAN_POINT('',(13.335,-24.892,0.));
#783=VERTEX_POINT('',#782);
#784=EDGE_CURVE('E1240',#773,#783,#781,.T.);
#785=ORIENTED_EDGE('',*,*,#784,.T.);
#786=DIRECTION('',(1.,0.,0.));
#787=VECTOR('',#786,1.);
#788=CARTESIAN_POINT('',(25.654,-24.892,0.));
#789=LINE('',#788,#787);
#790=CARTESIAN_POINT('',(15.113,-24.892,0.));
#791=VERTEX_POINT('',#790);
#792=EDGE_CURVE('E1241',#783,#791,#789,.T.);
#793=ORIENTED_EDGE('',*,*,#792,.T.);
#794=DIRECTION('',(0.,0.,1.));
#795=VECTOR('',#794,1.);
#796=CARTESIAN_POINT('',(15.113,-24.892,-15.492000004));
#797=LINE('',#796,#795);
#798=CARTESIAN_POINT('',(15.113,-24.892,-15.873000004));
#799=VERTEX_POINT('',#798);
#800=EDGE_CURVE('E1279',#799,#791,#797,.T.);
#801=ORIENTED_EDGE('',*,*,#800,.F.);
#802=DIRECTION('',(-1.,0.,0.));
#803=VECTOR('',#802,1.);
#804=CARTESIAN_POINT('',(25.654,-24.892,-15.873000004));
#805=LINE('',#804,#803);
#806=CARTESIAN_POINT('',(25.654,-24.892,-15.873000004));
#807=VERTEX_POINT('',#806);
#808=EDGE_CURVE('E791',#807,#799,#805,.T.);
#809=ORIENTED_EDGE('',*,*,#808,.F.);
#810=DIRECTION('',(0.,0.,-1.));
#811=VECTOR('',#810,1.);
#812=CARTESIAN_POINT('',(25.654,-24.892,6.5278));
#813=LINE('',#812,#811);
#814=EDGE_CURVE('E1257',#775,#807,#813,.T.);
#815=ORIENTED_EDGE('',*,*,#814,.F.);
#816=EDGE_LOOP('',(#777,#785,#793,#801,#809,#815));
#817=FACE_BOUND('',#816,.T.);
#818=ADVANCED_FACE('F942',(#817),#767,.F.);
#819=CARTESIAN_POINT('',(25.654,-12.5,6.5278));
#820=DIRECTION('',(-1.,0.,0.));
#821=DIRECTION('',(0.,0.,1.));
#822=AXIS2_PLACEMENT_3D('',#819,#820,#821);
#823=PLANE('',#822);
#824=DIRECTION('',(0.,1.,0.));
#825=VECTOR('',#824,1.);
#826=CARTESIAN_POINT('',(25.654,-12.5,4.08305));
#827=LINE('',#826,#825);
#828=CARTESIAN_POINT('',(25.654,-16.056,4.08305));
#829=VERTEX_POINT('',#828);
#830=EDGE_CURVE('E577',#775,#829,#827,.T.);
#831=ORIENTED_EDGE('',*,*,#830,.F.);
#832=ORIENTED_EDGE('',*,*,#814,.T.);
#833=DIRECTION('',(0.,-1.,0.));
#834=VECTOR('',#833,1.);
#835=CARTESIAN_POINT('',(25.654,-24.892,-15.873000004));
#836=LINE('',#835,#834);
#837=CARTESIAN_POINT('',(25.654,-19.485,-15.873000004));
#838=VERTEX_POINT('',#837);
#839=EDGE_CURVE('E788',#838,#807,#836,.T.);
#840=ORIENTED_EDGE('',*,*,#839,.F.);
#841=DIRECTION('',(0.,0.,1.));
#842=VECTOR('',#841,1.);
#843=CARTESIAN_POINT('',(25.654,-19.485,-15.873000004));
#844=LINE('',#843,#842);
#845=CARTESIAN_POINT('',(25.654,-19.485,-15.492000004));
#846=VERTEX_POINT('',#845);
#847=EDGE_CURVE('E798',#838,#846,#844,.T.);
#848=ORIENTED_EDGE('',*,*,#847,.T.);
#849=DIRECTION('',(0.,-1.,0.));
#850=VECTOR('',#849,1.);
#851=CARTESIAN_POINT('',(25.654,-24.892,-15.492000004));
#852=LINE('',#851,#850);
#853=CARTESIAN_POINT('',(25.654,-12.5,-15.492000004));
#854=VERTEX_POINT('',#853);
#855=EDGE_CURVE('E1289',#854,#846,#852,.T.);
#856=ORIENTED_EDGE('',*,*,#855,.F.);
#857=DIRECTION('',(0.,0.,1.));
#858=VECTOR('',#857,1.);
#859=CARTESIAN_POINT('',(25.654,-12.5,-15.492000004));
#860=LINE('',#859,#858);
#861=CARTESIAN_POINT('',(25.654,-12.5,0.));
#862=VERTEX_POINT('',#861);
#863=EDGE_CURVE('E1298',#854,#862,#860,.T.);
#864=ORIENTED_EDGE('',*,*,#863,.T.);
#865=DIRECTION('',(0.,-1.,0.));
#866=VECTOR('',#865,1.);
#867=CARTESIAN_POINT('',(25.654,-43.27398,0.));
#868=LINE('',#867,#866);
#869=CARTESIAN_POINT('',(25.654,-16.056,0.));
#870=VERTEX_POINT('',#869);
#871=EDGE_CURVE('E1237',#862,#870,#868,.T.);
#872=ORIENTED_EDGE('',*,*,#871,.T.);
#873=DIRECTION('',(0.,0.,-1.));
#874=VECTOR('',#873,1.);
#875=CARTESIAN_POINT('',(25.654,-16.056,6.5278));
#876=LINE('',#875,#874);
#877=EDGE_CURVE('E1234',#870,#829,#876,.F.);
#878=ORIENTED_EDGE('',*,*,#877,.T.);
#879=EDGE_LOOP('',(#831,#832,#840,#848,#856,#864,#872,#878));
#880=FACE_BOUND('',#879,.T.);
#881=ADVANCED_FACE('F938',(#880),#823,.F.);
#882=CARTESIAN_POINT('',(13.335,-28.448,6.5278));
#883=DIRECTION('',(0.,0.,1.));
#884=DIRECTION('',(1.,0.,0.));
#885=AXIS2_PLACEMENT_3D('',#882,#883,#884);
#886=CYLINDRICAL_SURFACE('',#885,3.556);
#887=CARTESIAN_POINT('',(13.335,-28.448,4.08305));
#888=DIRECTION('',(0.,0.,1.));
#889=DIRECTION('',(1.,0.,0.));
#890=AXIS2_PLACEMENT_3D('',#887,#888,#889);
#891=CIRCLE('',#890,3.556);
#892=CARTESIAN_POINT('',(9.779,-28.448,4.08305));
#893=VERTEX_POINT('',#892);
#894=EDGE_CURVE('E573',#893,#773,#891,.F.);
#895=ORIENTED_EDGE('',*,*,#894,.F.);
#896=DIRECTION('',(0.,0.,-1.));
#897=VECTOR('',#896,1.);
#898=CARTESIAN_POINT('',(9.779,-28.448,5.09905));
#899=LINE('',#898,#897);
#900=CARTESIAN_POINT('',(9.779,-28.448,0.));
#901=VERTEX_POINT('',#900);
#902=EDGE_CURVE('E1499',#901,#893,#899,.F.);
#903=ORIENTED_EDGE('',*,*,#902,.F.);
#904=CARTESIAN_POINT('',(13.335,-28.448,0.));
#905=DIRECTION('',(0.,0.,1.));
#906=DIRECTION('',(1.,0.,0.));
#907=AXIS2_PLACEMENT_3D('',#904,#905,#906);
#908=CIRCLE('',#907,3.556);
#909=EDGE_CURVE('E1395',#783,#901,#908,.T.);
#910=ORIENTED_EDGE('',*,*,#909,.F.);
#911=ORIENTED_EDGE('',*,*,#784,.F.);
#912=EDGE_LOOP('',(#895,#903,#910,#911));
#913=FACE_BOUND('',#912,.T.);
#914=ADVANCED_FACE('F941',(#913),#886,.F.);
#915=CARTESIAN_POINT('',(-4.69900000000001,-12.66698,5.73405));
#916=DIRECTION('',(0.,1.,0.));
#917=DIRECTION('',(-1.,0.,0.));
#918=AXIS2_PLACEMENT_3D('',#915,#916,#917);
#919=PLANE('',#918);
#920=ORIENTED_EDGE('',*,*,#300,.F.);
#921=DIRECTION('',(0.,0.,1.));
#922=VECTOR('',#921,1.);
#923=CARTESIAN_POINT('',(6.24426554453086,-12.66698,6.5278));
#924=LINE('',#923,#922);
#925=EDGE_CURVE('E610',#291,#674,#924,.T.);
#926=ORIENTED_EDGE('',*,*,#925,.T.);
#927=ORIENTED_EDGE('',*,*,#675,.T.);
#928=DIRECTION('',(0.,0.,-1.));
#929=VECTOR('',#928,1.);
#930=CARTESIAN_POINT('',(-3.0636093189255,-12.66698,0.));
#931=LINE('',#930,#929);
#932=EDGE_CURVE('E655',#666,#299,#931,.T.);
#933=ORIENTED_EDGE('',*,*,#932,.T.);
#934=EDGE_LOOP('',(#920,#926,#927,#933));
#935=FACE_BOUND('',#934,.T.);
#936=ADVANCED_FACE('F1143',(#935),#919,.F.);
#937=CARTESIAN_POINT('',(-25.4,-43.27398,0.));
#938=DIRECTION('',(0.,0.,1.));
#939=DIRECTION('',(1.,0.,0.));
#940=AXIS2_PLACEMENT_3D('',#937,#938,#939);
#941=PLANE('',#940);
#942=ORIENTED_EDGE('',*,*,#59,.T.);
#943=EDGE_LOOP('',(#942));
#944=FACE_BOUND('',#943,.T.);
#945=ORIENTED_EDGE('',*,*,#31,.T.);
#946=EDGE_LOOP('',(#945));
#947=FACE_BOUND('',#946,.T.);
#948=CARTESIAN_POINT('',(6.858,16.056,0.));
#949=DIRECTION('',(0.,0.,1.));
#950=DIRECTION('',(1.,0.,0.));
#951=AXIS2_PLACEMENT_3D('',#948,#949,#950);
#952=CIRCLE('',#951,3.556);
#953=CARTESIAN_POINT('',(3.302,16.056,0.));
#954=VERTEX_POINT('',#953);
#955=CARTESIAN_POINT('',(6.858,12.5,0.));
#956=VERTEX_POINT('',#955);
#957=EDGE_CURVE('E1344',#954,#956,#952,.T.);
#958=ORIENTED_EDGE('',*,*,#957,.T.);
#959=DIRECTION('',(-1.,0.,0.));
#960=VECTOR('',#959,1.);
#961=CARTESIAN_POINT('',(32.512,12.5,0.));
#962=LINE('',#961,#960);
#963=CARTESIAN_POINT('',(32.512,12.5,0.));
#964=VERTEX_POINT('',#963);
#965=EDGE_CURVE('E1326',#964,#956,#962,.T.);
#966=ORIENTED_EDGE('',*,*,#965,.F.);
#967=DIRECTION('',(0.,1.,0.));
#968=VECTOR('',#967,1.);
#969=CARTESIAN_POINT('',(32.512,24.13,0.));
#970=LINE('',#969,#968);
#971=CARTESIAN_POINT('',(32.512,-12.5,0.));
#972=VERTEX_POINT('',#971);
#973=EDGE_CURVE('E1267',#972,#964,#970,.T.);
#974=ORIENTED_EDGE('',*,*,#973,.F.);
#975=DIRECTION('',(1.,0.,0.));
#976=VECTOR('',#975,1.);
#977=CARTESIAN_POINT('',(32.512,-12.5,0.));
#978=LINE('',#977,#976);
#979=CARTESIAN_POINT('',(29.21,-12.5,0.));
#980=VERTEX_POINT('',#979);
#981=EDGE_CURVE('E1244',#980,#972,#978,.T.);
#982=ORIENTED_EDGE('',*,*,#981,.F.);
#983=CARTESIAN_POINT('',(29.21,-16.056,0.));
#984=DIRECTION('',(0.,0.,1.));
#985=DIRECTION('',(1.,0.,0.));
#986=AXIS2_PLACEMENT_3D('',#983,#984,#985);
#987=CIRCLE('',#986,3.556);
#988=EDGE_CURVE('E1383',#980,#870,#987,.T.);
#989=ORIENTED_EDGE('',*,*,#988,.T.);
#990=ORIENTED_EDGE('',*,*,#871,.F.);
#991=DIRECTION('',(1.,0.,0.));
#992=VECTOR('',#991,1.);
#993=CARTESIAN_POINT('',(25.654,-12.5,0.));
#994=LINE('',#993,#992);
#995=CARTESIAN_POINT('',(15.113,-12.5,0.));
#996=VERTEX_POINT('',#995);
#997=EDGE_CURVE('E1275',#996,#862,#994,.T.);
#998=ORIENTED_EDGE('',*,*,#997,.F.);
#999=DIRECTION('',(0.,1.,0.));
#1000=VECTOR('',#999,1.);
#1001=CARTESIAN_POINT('',(15.113,-24.892,0.));
#1002=LINE('',#1001,#1000);
#1003=EDGE_CURVE('E1272',#791,#996,#1002,.T.);
#1004=ORIENTED_EDGE('',*,*,#1003,.F.);
#1005=ORIENTED_EDGE('',*,*,#792,.F.);
#1006=ORIENTED_EDGE('',*,*,#909,.T.);
#1007=DIRECTION('',(0.,1.,0.));
#1008=VECTOR('',#1007,1.);
#1009=CARTESIAN_POINT('',(9.779,-24.892,0.));
#1010=LINE('',#1009,#1008);
#1011=CARTESIAN_POINT('',(9.77899999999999,-34.6202364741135,0.));
#1012=VERTEX_POINT('',#1011);
#1013=EDGE_CURVE('E1245',#1012,#901,#1010,.T.);
#1014=ORIENTED_EDGE('',*,*,#1013,.F.);
#1015=DIRECTION('',(1.,0.,0.));
#1016=VECTOR('',#1015,1.);
#1017=CARTESIAN_POINT('',(9.77899999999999,-34.6202364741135,0.));
#1018=LINE('',#1017,#1016);
#1019=CARTESIAN_POINT('',(-15.8927435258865,-34.6202364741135,0.));
#1020=VERTEX_POINT('',#1019);
#1021=EDGE_CURVE('E701',#1020,#1012,#1018,.T.);
#1022=ORIENTED_EDGE('',*,*,#1021,.F.);
#1023=DIRECTION('',(0.707106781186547,-0.707106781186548,0.));
#1024=VECTOR('',#1023,1.);
#1025=CARTESIAN_POINT('',(-7.23900000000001,-43.27398,0.));
#1026=LINE('',#1025,#1024);
#1027=CARTESIAN_POINT('',(-21.971,-28.5419799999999,0.));
#1028=VERTEX_POINT('',#1027);
#1029=EDGE_CURVE('E1183',#1020,#1028,#1026,.F.);
#1030=ORIENTED_EDGE('',*,*,#1029,.T.);
#1031=DIRECTION('',(0.,-1.,0.));
#1032=VECTOR('',#1031,1.);
#1033=CARTESIAN_POINT('',(-21.971,-43.27398,0.));
#1034=LINE('',#1033,#1032);
#1035=CARTESIAN_POINT('',(-21.971,-13.7137314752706,0.));
#1036=VERTEX_POINT('',#1035);
#1037=EDGE_CURVE('E721',#1036,#1028,#1034,.T.);
#1038=ORIENTED_EDGE('',*,*,#1037,.F.);
#1039=CARTESIAN_POINT('',(-25.527,-13.7137314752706,0.));
#1040=DIRECTION('',(0.,0.,1.));
#1041=DIRECTION('',(1.,0.,0.));
#1042=AXIS2_PLACEMENT_3D('',#1039,#1040,#1041);
#1043=CIRCLE('',#1042,3.556);
#1044=CARTESIAN_POINT('',(-25.4,-10.1600000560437,0.));
#1045=VERTEX_POINT('',#1044);
#1046=EDGE_CURVE('E1502',#1036,#1045,#1043,.T.);
#1047=ORIENTED_EDGE('',*,*,#1046,.T.);
#1048=DIRECTION('',(0.,-1.,0.));
#1049=VECTOR('',#1048,1.);
#1050=CARTESIAN_POINT('',(-25.4,24.13,0.));
#1051=LINE('',#1050,#1049);
#1052=CARTESIAN_POINT('',(-25.4,10.1599999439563,0.));
#1053=VERTEX_POINT('',#1052);
#1054=EDGE_CURVE('E1256',#1053,#1045,#1051,.T.);
#1055=ORIENTED_EDGE('',*,*,#1054,.F.);
#1056=CARTESIAN_POINT('',(-25.527,13.7137313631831,0.));
#1057=DIRECTION('',(0.,0.,1.));
#1058=DIRECTION('',(1.,0.,0.));
#1059=AXIS2_PLACEMENT_3D('',#1056,#1057,#1058);
#1060=CIRCLE('',#1059,3.556);
#1061=CARTESIAN_POINT('',(-21.971,13.7137313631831,0.));
#1062=VERTEX_POINT('',#1061);
#1063=EDGE_CURVE('E1495',#1053,#1062,#1060,.T.);
#1064=ORIENTED_EDGE('',*,*,#1063,.T.);
#1065=DIRECTION('',(0.,-1.,0.));
#1066=VECTOR('',#1065,1.);
#1067=CARTESIAN_POINT('',(-21.971,24.13,0.));
#1068=LINE('',#1067,#1066);
#1069=CARTESIAN_POINT('',(-21.971,22.098,0.));
#1070=VERTEX_POINT('',#1069);
#1071=EDGE_CURVE('E710',#1070,#1062,#1068,.T.);
#1072=ORIENTED_EDGE('',*,*,#1071,.F.);
#1073=DIRECTION('',(-0.707106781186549,-0.707106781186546,0.));
#1074=VECTOR('',#1073,1.);
#1075=CARTESIAN_POINT('',(-21.971,22.098,0.));
#1076=LINE('',#1075,#1074);
#1077=CARTESIAN_POINT('',(-19.939,24.13,0.));
#1078=VERTEX_POINT('',#1077);
#1079=EDGE_CURVE('E1400',#1070,#1078,#1076,.F.);
#1080=ORIENTED_EDGE('',*,*,#1079,.T.);
#1081=DIRECTION('',(-1.,0.,0.));
#1082=VECTOR('',#1081,1.);
#1083=CARTESIAN_POINT('',(-25.4,24.13,0.));
#1084=LINE('',#1083,#1082);
#1085=CARTESIAN_POINT('',(-11.43,24.13,0.));
#1086=VERTEX_POINT('',#1085);
#1087=EDGE_CURVE('E1263',#1086,#1078,#1084,.T.);
#1088=ORIENTED_EDGE('',*,*,#1087,.F.);
#1089=DIRECTION('',(0.,-1.,0.));
#1090=VECTOR('',#1089,1.);
#1091=CARTESIAN_POINT('',(-11.43,-43.27398,0.));
#1092=LINE('',#1091,#1090);
#1093=CARTESIAN_POINT('',(-11.43,22.098,0.));
#1094=VERTEX_POINT('',#1093);
#1095=EDGE_CURVE('E594',#1086,#1094,#1092,.T.);
#1096=ORIENTED_EDGE('',*,*,#1095,.T.);
#1097=DIRECTION('',(0.,1.,0.));
#1098=VECTOR('',#1097,1.);
#1099=CARTESIAN_POINT('',(-11.43,24.13,0.));
#1100=LINE('',#1099,#1098);
#1101=CARTESIAN_POINT('',(-11.43,14.605,0.));
#1102=VERTEX_POINT('',#1101);
#1103=EDGE_CURVE('E1370',#1102,#1094,#1100,.T.);
#1104=ORIENTED_EDGE('',*,*,#1103,.F.);
#1105=DIRECTION('',(-1.,0.,0.));
#1106=VECTOR('',#1105,1.);
#1107=CARTESIAN_POINT('',(-6.35,14.605,0.));
#1108=LINE('',#1107,#1106);
#1109=CARTESIAN_POINT('',(-0.98003285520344,14.605,0.));
#1110=VERTEX_POINT('',#1109);
#1111=EDGE_CURVE('E1375',#1110,#1102,#1108,.T.);
#1112=ORIENTED_EDGE('',*,*,#1111,.F.);
#1113=DIRECTION('',(0.,1.,0.));
#1114=VECTOR('',#1113,1.);
#1115=CARTESIAN_POINT('',(-0.980032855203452,22.098,0.));
#1116=LINE('',#1115,#1114);
#1117=CARTESIAN_POINT('',(-0.980032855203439,13.843,0.));
#1118=VERTEX_POINT('',#1117);
#1119=EDGE_CURVE('E827',#1110,#1118,#1116,.F.);
#1120=ORIENTED_EDGE('',*,*,#1119,.T.);
#1121=CARTESIAN_POINT('',(-0.980420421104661,13.8432,0.));
#1122=CARTESIAN_POINT('',(-0.928970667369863,13.816688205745,0.));
#1123=CARTESIAN_POINT('',(-0.877347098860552,13.7904970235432,0.));
#1124=CARTESIAN_POINT('',(-0.773455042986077,13.7391750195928,0.));
#1125=CARTESIAN_POINT('',(-0.721185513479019,13.7140463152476,0.));
#1126=CARTESIAN_POINT('',(-0.613580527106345,13.6643013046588,0.));
#1127=CARTESIAN_POINT('',(-0.558211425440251,13.6397563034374,0.));
#1128=CARTESIAN_POINT('',(-0.446387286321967,13.5933994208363,0.));
#1129=CARTESIAN_POINT('',(-0.389933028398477,13.5715856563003,0.));
#1130=CARTESIAN_POINT('',(-0.260897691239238,13.5272924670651,0.));
#1131=CARTESIAN_POINT('',(-0.187853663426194,13.5060438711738,0.));
#1132=CARTESIAN_POINT('',(-0.0770154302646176,13.4832645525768,0.));
#1133=CARTESIAN_POINT('',(-0.0401728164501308,13.4772010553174,0.));
#1134=CARTESIAN_POINT('',(0.0339219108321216,13.4685962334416,0.));
#1135=CARTESIAN_POINT('',(0.0711738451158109,13.4660534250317,0.));
#1136=CARTESIAN_POINT('',(0.14605515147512,13.4647919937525,0.));
#1137=CARTESIAN_POINT('',(0.183685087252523,13.4661053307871,0.));
#1138=CARTESIAN_POINT('',(0.258628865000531,13.4724582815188,0.));
#1139=CARTESIAN_POINT('',(0.295942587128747,13.4774992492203,0.));
#1140=CARTESIAN_POINT('',(0.408267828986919,13.4975855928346,0.));
#1141=CARTESIAN_POINT('',(0.482373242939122,13.5175860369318,0.));
#1142=CARTESIAN_POINT('',(0.615427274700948,13.5610603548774,0.));
#1143=CARTESIAN_POINT('',(0.674801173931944,13.5833558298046,0.));
#1144=CARTESIAN_POINT('',(0.792314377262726,13.6311284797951,0.));
#1145=CARTESIAN_POINT('',(0.850452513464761,13.656608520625,0.));
#1146=CARTESIAN_POINT('',(0.963264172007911,13.7083675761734,0.));
#1147=CARTESIAN_POINT('',(1.01797744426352,13.7345618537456,0.));
#1148=CARTESIAN_POINT('',(1.12666197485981,13.7881255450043,0.));
#1149=CARTESIAN_POINT('',(1.18063472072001,13.8154919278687,0.));
#1150=CARTESIAN_POINT('',(1.23442042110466,13.8432,0.));
#1151=B_SPLINE_CURVE_WITH_KNOTS('',3,(#1121,#1122,#1123,#1124,#1125,#1126,#1127,#1128,#1129,
#1130,#1131,#1132,#1133,#1134,#1135,#1136,#1137,#1138,#1139,#1140,#1141,#1142,#1143,#1144,#1145,
#1146,#1147,#1148,#1149,#1150),.UNSPECIFIED.,.F.,.F.,(4,2,2,2,2,2,2,2,2,2,2,2,2,2,4),(0.,
0.173645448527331,0.347622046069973,0.529260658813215,0.710773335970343,0.938260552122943,
1.05013484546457,1.16196197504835,1.27471854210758,1.38751608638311,1.61692181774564,
1.80710785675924,1.99746629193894,2.17943313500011,2.36095492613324),.UNSPECIFIED.);
#1152=CARTESIAN_POINT('',(1.23403285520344,13.843,0.));
#1153=VERTEX_POINT('',#1152);
#1154=EDGE_CURVE('E819',#1118,#1153,#1151,.T.);
#1155=ORIENTED_EDGE('',*,*,#1154,.T.);
#1156=DIRECTION('',(0.,1.,0.));
#1157=VECTOR('',#1156,1.);
#1158=CARTESIAN_POINT('',(1.23403285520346,22.098,0.));
#1159=LINE('',#1158,#1157);
#1160=CARTESIAN_POINT('',(1.23403285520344,14.605,0.));
#1161=VERTEX_POINT('',#1160);
#1162=EDGE_CURVE('E1184',#1153,#1161,#1159,.T.);
#1163=ORIENTED_EDGE('',*,*,#1162,.T.);
#1164=CARTESIAN_POINT('',(3.302,14.605,0.));
#1165=VERTEX_POINT('',#1164);
#1166=EDGE_CURVE('E1351',#1165,#1161,#1108,.T.);
#1167=ORIENTED_EDGE('',*,*,#1166,.F.);
#1168=DIRECTION('',(0.,1.,0.));
#1169=VECTOR('',#1168,1.);
#1170=CARTESIAN_POINT('',(3.302,9.8280375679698,0.));
#1171=LINE('',#1170,#1169);
#1172=EDGE_CURVE('E597',#1165,#954,#1171,.T.);
#1173=ORIENTED_EDGE('',*,*,#1172,.T.);
#1174=EDGE_LOOP('',(#958,#966,#974,#982,#989,#990,#998,#1004,#1005,#1006,#1014,#1022,#1030,
#1038,#1047,#1055,#1064,#1072,#1080,#1088,#1096,#1104,#1112,#1120,#1155,#1163,#1167,#1173));
#1175=FACE_BOUND('',#1174,.T.);
#1176=CARTESIAN_POINT('',(8.382,-13.716,0.));
#1177=DIRECTION('',(0.,0.,1.));
#1178=DIRECTION('',(1.,0.,0.));
#1179=AXIS2_PLACEMENT_3D('',#1176,#1177,#1178);
#1180=CIRCLE('',#1179,2.38124999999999);
#1181=CARTESIAN_POINT('',(10.76325,-13.716,0.));
#1182=VERTEX_POINT('',#1181);
#1183=EDGE_CURVE('E605',#1182,#1182,#1180,.T.);
#1184=ORIENTED_EDGE('',*,*,#1183,.T.);
#1185=EDGE_LOOP('',(#1184));
#1186=FACE_BOUND('',#1185,.T.);
#1187=CARTESIAN_POINT('',(1.27,-17.36598,0.));
#1188=DIRECTION('',(0.,0.,1.));
#1189=DIRECTION('',(1.,0.,0.));
#1190=AXIS2_PLACEMENT_3D('',#1187,#1188,#1189);
#1191=CIRCLE('',#1190,2.38124999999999);
#1192=CARTESIAN_POINT('',(3.65124999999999,-17.36598,0.));
#1193=VERTEX_POINT('',#1192);
#1194=EDGE_CURVE('E613',#1193,#1193,#1191,.T.);
#1195=ORIENTED_EDGE('',*,*,#1194,.T.);
#1196=EDGE_LOOP('',(#1195));
#1197=FACE_BOUND('',#1196,.T.);
#1198=CARTESIAN_POINT('',(-16.256,-10.50798,0.));
#1199=DIRECTION('',(0.,0.,1.));
#1200=DIRECTION('',(1.,0.,0.));
#1201=AXIS2_PLACEMENT_3D('',#1198,#1199,#1200);
#1202=CIRCLE('',#1201,2.38124999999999);
#1203=CARTESIAN_POINT('',(-13.87475,-10.50798,0.));
#1204=VERTEX_POINT('',#1203);
#1205=EDGE_CURVE('E620',#1204,#1204,#1202,.T.);
#1206=ORIENTED_EDGE('',*,*,#1205,.T.);
#1207=EDGE_LOOP('',(#1206));
#1208=FACE_BOUND('',#1207,.T.);
#1209=CARTESIAN_POINT('',(-21.336,0.,0.));
#1210=DIRECTION('',(0.,0.,1.));
#1211=DIRECTION('',(1.,0.,0.));
#1212=AXIS2_PLACEMENT_3D('',#1209,#1210,#1211);
#1213=CIRCLE('',#1212,2.38124999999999);
#1214=CARTESIAN_POINT('',(-18.95475,0.,0.));
#1215=VERTEX_POINT('',#1214);
#1216=EDGE_CURVE('E628',#1215,#1215,#1213,.T.);
#1217=ORIENTED_EDGE('',*,*,#1216,.T.);
#1218=EDGE_LOOP('',(#1217));
#1219=FACE_BOUND('',#1218,.T.);
#1220=CARTESIAN_POINT('',(-15.748,10.795,0.));
#1221=DIRECTION('',(0.,0.,-1.));
#1222=DIRECTION('',(-1.,0.,0.));
#1223=AXIS2_PLACEMENT_3D('',#1220,#1221,#1222);
#1224=CIRCLE('',#1223,3.175);
#1225=CARTESIAN_POINT('',(-18.923,10.795,0.));
#1226=VERTEX_POINT('',#1225);
#1227=EDGE_CURVE('E632',#1226,#1226,#1224,.T.);
#1228=ORIENTED_EDGE('',*,*,#1227,.F.);
#1229=EDGE_LOOP('',(#1228));
#1230=FACE_BOUND('',#1229,.T.);
#1231=CARTESIAN_POINT('',(-1.27,-28.03398,0.));
#1232=DIRECTION('',(0.,0.,1.));
#1233=DIRECTION('',(1.,0.,0.));
#1234=AXIS2_PLACEMENT_3D('',#1231,#1232,#1233);
#1235=CIRCLE('',#1234,3.39999999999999);
#1236=CARTESIAN_POINT('',(2.12999999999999,-28.03398,0.));
#1237=VERTEX_POINT('',#1236);
#1238=EDGE_CURVE('E1287',#1237,#1237,#1235,.T.);
#1239=ORIENTED_EDGE('',*,*,#1238,.T.);
#1240=EDGE_LOOP('',(#1239));
#1241=FACE_BOUND('',#1240,.T.);
#1242=CARTESIAN_POINT('',(26.823,5.,0.));
#1243=DIRECTION('',(0.,0.,1.));
#1244=DIRECTION('',(1.,0.,0.));
#1245=AXIS2_PLACEMENT_3D('',#1242,#1243,#1244);
#1246=CIRCLE('',#1245,1.54999999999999);
#1247=CARTESIAN_POINT('',(28.373,5.,0.));
#1248=VERTEX_POINT('',#1247);
#1249=EDGE_CURVE('E760',#1248,#1248,#1246,.T.);
#1250=ORIENTED_EDGE('',*,*,#1249,.T.);
#1251=EDGE_LOOP('',(#1250));
#1252=FACE_BOUND('',#1251,.T.);
#1253=CARTESIAN_POINT('',(1.82299999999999,-5.,0.));
#1254=DIRECTION('',(0.,0.,1.));
#1255=DIRECTION('',(1.,0.,0.));
#1256=AXIS2_PLACEMENT_3D('',#1253,#1254,#1255);
#1257=CIRCLE('',#1256,1.54999999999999);
#1258=CARTESIAN_POINT('',(3.37299999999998,-5.,0.));
#1259=VERTEX_POINT('',#1258);
#1260=EDGE_CURVE('E756',#1259,#1259,#1257,.T.);
#1261=ORIENTED_EDGE('',*,*,#1260,.T.);
#1262=EDGE_LOOP('',(#1261));
#1263=FACE_BOUND('',#1262,.T.);
#1264=CARTESIAN_POINT('',(1.82299999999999,5.,0.));
#1265=DIRECTION('',(0.,0.,1.));
#1266=DIRECTION('',(1.,0.,0.));
#1267=AXIS2_PLACEMENT_3D('',#1264,#1265,#1266);
#1268=CIRCLE('',#1267,1.54999999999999);
#1269=CARTESIAN_POINT('',(3.37299999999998,5.,0.));
#1270=VERTEX_POINT('',#1269);
#1271=EDGE_CURVE('E752',#1270,#1270,#1268,.T.);
#1272=ORIENTED_EDGE('',*,*,#1271,.T.);
#1273=EDGE_LOOP('',(#1272));
#1274=FACE_BOUND('',#1273,.T.);
#1275=CARTESIAN_POINT('',(26.823,-5.,0.));
#1276=DIRECTION('',(0.,0.,1.));
#1277=DIRECTION('',(1.,0.,0.));
#1278=AXIS2_PLACEMENT_3D('',#1275,#1276,#1277);
#1279=CIRCLE('',#1278,1.54999999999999);
#1280=CARTESIAN_POINT('',(28.373,-5.,0.));
#1281=VERTEX_POINT('',#1280);
#1282=EDGE_CURVE('E748',#1281,#1281,#1279,.T.);
#1283=ORIENTED_EDGE('',*,*,#1282,.T.);
#1284=EDGE_LOOP('',(#1283));
#1285=FACE_BOUND('',#1284,.T.);
#1286=CARTESIAN_POINT('',(-19.1232329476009,5.96899994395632,0.));
#1287=DIRECTION('',(0.,0.,1.));
#1288=DIRECTION('',(1.,0.,0.));
#1289=AXIS2_PLACEMENT_3D('',#1286,#1287,#1288);
#1290=CIRCLE('',#1289,1.13029999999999);
#1291=CARTESIAN_POINT('',(-17.9929329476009,5.96899994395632,0.));
#1292=VERTEX_POINT('',#1291);
#1293=EDGE_CURVE('E744',#1292,#1292,#1290,.T.);
#1294=ORIENTED_EDGE('',*,*,#1293,.T.);
#1295=EDGE_LOOP('',(#1294));
#1296=FACE_BOUND('',#1295,.T.);
#1297=CARTESIAN_POINT('',(-19.1232329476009,-5.96900005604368,0.));
#1298=DIRECTION('',(0.,0.,1.));
#1299=DIRECTION('',(1.,0.,0.));
#1300=AXIS2_PLACEMENT_3D('',#1297,#1298,#1299);
#1301=CIRCLE('',#1300,1.13029999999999);
#1302=CARTESIAN_POINT('',(-17.9929329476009,-5.96900005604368,0.));
#1303=VERTEX_POINT('',#1302);
#1304=EDGE_CURVE('E740',#1303,#1303,#1301,.T.);
#1305=ORIENTED_EDGE('',*,*,#1304,.T.);
#1306=EDGE_LOOP('',(#1305));
#1307=FACE_BOUND('',#1306,.T.);
#1308=CARTESIAN_POINT('',(7.493,-18.25498,0.));
#1309=DIRECTION('',(0.,0.,1.));
#1310=DIRECTION('',(1.,0.,0.));
#1311=AXIS2_PLACEMENT_3D('',#1308,#1309,#1310);
#1312=CIRCLE('',#1311,0.888999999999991);
#1313=CARTESIAN_POINT('',(8.38199999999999,-18.25498,0.));
#1314=VERTEX_POINT('',#1313);
#1315=EDGE_CURVE('E700',#1314,#1314,#1312,.T.);
#1316=ORIENTED_EDGE('',*,*,#1315,.T.);
#1317=EDGE_LOOP('',(#1316));
#1318=FACE_BOUND('',#1317,.T.);
#1319=CARTESIAN_POINT('',(14.323,0.,0.));
#1320=DIRECTION('',(0.,0.,-1.));
#1321=DIRECTION('',(-1.,0.,0.));
#1322=AXIS2_PLACEMENT_3D('',#1319,#1320,#1321);
#1323=CIRCLE('',#1322,9.128125);
#1324=CARTESIAN_POINT('',(5.19487499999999,0.,0.));
#1325=VERTEX_POINT('',#1324);
#1326=EDGE_CURVE('E665',#1325,#1325,#1323,.T.);
#1327=ORIENTED_EDGE('',*,*,#1326,.F.);
#1328=EDGE_LOOP('',(#1327));
#1329=FACE_BOUND('',#1328,.T.);
#1330=CARTESIAN_POINT('',(-9.398,0.,0.));
#1331=DIRECTION('',(0.,0.,1.));
#1332=DIRECTION('',(1.,0.,0.));
#1333=AXIS2_PLACEMENT_3D('',#1330,#1331,#1332);
#1334=CIRCLE('',#1333,7.54062499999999);
#1335=CARTESIAN_POINT('',(-1.85737500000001,0.,0.));
#1336=VERTEX_POINT('',#1335);
#1337=EDGE_CURVE('E661',#1336,#1336,#1334,.T.);
#1338=ORIENTED_EDGE('',*,*,#1337,.T.);
#1339=EDGE_LOOP('',(#1338));
#1340=FACE_BOUND('',#1339,.T.);
#1341=CARTESIAN_POINT('',(-6.858,-14.82598,0.));
#1342=DIRECTION('',(0.,0.,-1.));
#1343=DIRECTION('',(-1.,0.,0.));
#1344=AXIS2_PLACEMENT_3D('',#1341,#1342,#1343);
#1345=CIRCLE('',#1344,4.365625);
#1346=CARTESIAN_POINT('',(-11.223625,-14.82598,0.));
#1347=VERTEX_POINT('',#1346);
#1348=EDGE_CURVE('E647',#1347,#1347,#1345,.T.);
#1349=ORIENTED_EDGE('',*,*,#1348,.F.);
#1350=EDGE_LOOP('',(#1349));
#1351=FACE_BOUND('',#1350,.T.);
#1352=CARTESIAN_POINT('',(-13.462,-28.03398,0.));
#1353=DIRECTION('',(0.,0.,-1.));
#1354=DIRECTION('',(-1.,0.,0.));
#1355=AXIS2_PLACEMENT_3D('',#1352,#1353,#1354);
#1356=CIRCLE('',#1355,3.96875);
#1357=CARTESIAN_POINT('',(-17.43075,-28.03398,0.));
#1358=VERTEX_POINT('',#1357);
#1359=EDGE_CURVE('E644',#1358,#1358,#1356,.T.);
#1360=ORIENTED_EDGE('',*,*,#1359,.F.);
#1361=EDGE_LOOP('',(#1360));
#1362=FACE_BOUND('',#1361,.T.);
#1363=CARTESIAN_POINT('',(-3.302,10.795,0.));
#1364=DIRECTION('',(0.,0.,-1.));
#1365=DIRECTION('',(-1.,0.,0.));
#1366=AXIS2_PLACEMENT_3D('',#1363,#1364,#1365);
#1367=CIRCLE('',#1366,3.175);
#1368=CARTESIAN_POINT('',(-6.477,10.795,0.));
#1369=VERTEX_POINT('',#1368);
#1370=EDGE_CURVE('E638',#1369,#1369,#1367,.T.);
#1371=ORIENTED_EDGE('',*,*,#1370,.F.);
#1372=EDGE_LOOP('',(#1371));
#1373=FACE_BOUND('',#1372,.T.);
#1374=ADVANCED_FACE('F830',(#944,#947,#1175,#1186,#1197,#1208,#1219,#1230,#1241,#1252,#1263,
#1274,#1285,#1296,#1307,#1318,#1329,#1340,#1351,#1362,#1373),#941,.F.);
#1375=CARTESIAN_POINT('',(-4.69900000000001,-15.20698,5.73405));
#1376=DIRECTION('',(0.,0.,1.));
#1377=DIRECTION('',(1.,0.,0.));
#1378=AXIS2_PLACEMENT_3D('',#1375,#1376,#1377);
#1379=PLANE('',#1378);
#1380=CARTESIAN_POINT('',(7.493,-18.25498,5.73405));
#1381=DIRECTION('',(0.,0.,1.));
#1382=DIRECTION('',(1.,0.,0.));
#1383=AXIS2_PLACEMENT_3D('',#1380,#1381,#1382);
#1384=CIRCLE('',#1383,0.888999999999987);
#1385=CARTESIAN_POINT('',(8.38199999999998,-18.25498,5.73405));
#1386=VERTEX_POINT('',#1385);
#1387=EDGE_CURVE('E697',#1386,#1386,#1384,.T.);
#1388=ORIENTED_EDGE('',*,*,#1387,.F.);
#1389=EDGE_LOOP('',(#1388));
#1390=FACE_BOUND('',#1389,.T.);
#1391=CARTESIAN_POINT('',(7.493,-18.25498,5.73405));
#1392=DIRECTION('',(0.,0.,1.));
#1393=DIRECTION('',(1.,0.,0.));
#1394=AXIS2_PLACEMENT_3D('',#1391,#1392,#1393);
#1395=CIRCLE('',#1394,2.032);
#1396=CARTESIAN_POINT('',(9.52499999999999,-18.25498,5.73405));
#1397=VERTEX_POINT('',#1396);
#1398=EDGE_CURVE('E1218',#1397,#1397,#1395,.T.);
#1399=ORIENTED_EDGE('',*,*,#1398,.T.);
#1400=EDGE_LOOP('',(#1399));
#1401=FACE_BOUND('',#1400,.T.);
#1402=ADVANCED_FACE('F1133',(#1390,#1401),#1379,.T.);
#1403=CARTESIAN_POINT('',(7.49299999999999,-37.68598,5.73405));
#1404=DIRECTION('',(0.,0.,1.));
#1405=DIRECTION('',(1.,0.,0.));
#1406=AXIS2_PLACEMENT_3D('',#1403,#1404,#1405);
#1407=CIRCLE('',#1406,0.888999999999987);
#1408=CARTESIAN_POINT('',(8.38199999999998,-37.68598,5.73405));
#1409=VERTEX_POINT('',#1408);
#1410=EDGE_CURVE('E693',#1409,#1409,#1407,.T.);
#1411=ORIENTED_EDGE('',*,*,#1410,.F.);
#1412=EDGE_LOOP('',(#1411));
#1413=FACE_BOUND('',#1412,.T.);
#1414=CARTESIAN_POINT('',(7.49299999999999,-37.68598,5.73405));
#1415=DIRECTION('',(0.,0.,1.));
#1416=DIRECTION('',(1.,0.,0.));
#1417=AXIS2_PLACEMENT_3D('',#1414,#1415,#1416);
#1418=CIRCLE('',#1417,2.03199999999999);
#1419=CARTESIAN_POINT('',(9.52499999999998,-37.68598,5.73405));
#1420=VERTEX_POINT('',#1419);
#1421=EDGE_CURVE('E1215',#1420,#1420,#1418,.T.);
#1422=ORIENTED_EDGE('',*,*,#1421,.T.);
#1423=EDGE_LOOP('',(#1422));
#1424=FACE_BOUND('',#1423,.T.);
#1425=ADVANCED_FACE('F949',(#1413,#1424),#1379,.T.);
#1426=DIRECTION('',(0.,-1.,0.));
#1427=VECTOR('',#1426,1.);
#1428=CARTESIAN_POINT('',(9.779,-36.0635563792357,4.08305));
#1429=LINE('',#1428,#1427);
#1430=CARTESIAN_POINT('',(9.779,-36.0635563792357,4.08305));
#1431=VERTEX_POINT('',#1430);
#1432=EDGE_CURVE('E510',#893,#1431,#1429,.T.);
#1433=ORIENTED_EDGE('',*,*,#1432,.T.);
#1434=DIRECTION('',(0.,0.,1.));
#1435=VECTOR('',#1434,1.);
#1436=CARTESIAN_POINT('',(9.779,-36.0635563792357,-12.3011845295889));
#1437=LINE('',#1436,#1435);
#1438=EDGE_CURVE('E504',#1431,#214,#1437,.T.);
#1439=ORIENTED_EDGE('',*,*,#1438,.T.);
#1440=ORIENTED_EDGE('',*,*,#215,.T.);
#1441=DIRECTION('',(0.,0.,-1.));
#1442=VECTOR('',#1441,1.);
#1443=CARTESIAN_POINT('',(9.77899999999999,-43.27398,6.5278));
#1444=LINE('',#1443,#1442);
#1445=CARTESIAN_POINT('',(9.77899999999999,-43.27398,3.19405));
#1446=VERTEX_POINT('',#1445);
#1447=EDGE_CURVE('E1259',#206,#1446,#1444,.T.);
#1448=ORIENTED_EDGE('',*,*,#1447,.T.);
#1449=DIRECTION('',(0.,-1.,0.));
#1450=VECTOR('',#1449,1.);
#1451=CARTESIAN_POINT('',(9.77899999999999,-43.27398,3.19405));
#1452=LINE('',#1451,#1450);
#1453=CARTESIAN_POINT('',(9.77899999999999,-34.6202364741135,3.19405));
#1454=VERTEX_POINT('',#1453);
#1455=EDGE_CURVE('E707',#1454,#1446,#1452,.T.);
#1456=ORIENTED_EDGE('',*,*,#1455,.F.);
#1457=DIRECTION('',(0.,0.,-1.));
#1458=VECTOR('',#1457,1.);
#1459=CARTESIAN_POINT('',(9.77899999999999,-34.6202364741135,38.6422522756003));
#1460=LINE('',#1459,#1458);
#1461=EDGE_CURVE('E711',#1454,#1012,#1460,.T.);
#1462=ORIENTED_EDGE('',*,*,#1461,.T.);
#1463=ORIENTED_EDGE('',*,*,#1013,.T.);
#1464=ORIENTED_EDGE('',*,*,#902,.T.);
#1465=EDGE_LOOP('',(#1433,#1439,#1440,#1448,#1456,#1462,#1463,#1464));
#1466=FACE_BOUND('',#1465,.T.);
#1467=ADVANCED_FACE('F912',(#1466),#349,.F.);
#1468=CARTESIAN_POINT('',(-1.27,-28.03398,3.5306));
#1469=DIRECTION('',(0.,0.,1.));
#1470=DIRECTION('',(1.,0.,0.));
#1471=AXIS2_PLACEMENT_3D('',#1468,#1469,#1470);
#1472=CYLINDRICAL_SURFACE('',#1471,5.0038);
#1473=CARTESIAN_POINT('',(-1.27,-28.03398,3.5306));
#1474=DIRECTION('',(0.,0.,1.));
#1475=DIRECTION('',(1.,0.,0.));
#1476=AXIS2_PLACEMENT_3D('',#1473,#1474,#1475);
#1477=CIRCLE('',#1476,5.0038);
#1478=CARTESIAN_POINT('',(3.7338,-28.03398,3.5306));
#1479=VERTEX_POINT('',#1478);
#1480=EDGE_CURVE('E1288',#1479,#1479,#1477,.T.);
#1481=CARTESIAN_POINT('',(3.7338,-28.03398,3.5306));
#1482=CARTESIAN_POINT('',(3.7338,-28.03398,3.56182083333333));
#1483=CARTESIAN_POINT('',(3.7338,-28.03398,3.59304166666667));
#1484=CARTESIAN_POINT('',(3.7338,-28.03398,3.65548333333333));
#1485=CARTESIAN_POINT('',(3.7338,-28.03398,3.68670416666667));
#1486=CARTESIAN_POINT('',(3.7338,-28.03398,3.74914583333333));
#1487=CARTESIAN_POINT('',(3.7338,-28.03398,3.78036666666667));
#1488=CARTESIAN_POINT('',(3.7338,-28.03398,3.84280833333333));
#1489=CARTESIAN_POINT('',(3.7338,-28.03398,3.87402916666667));
#1490=CARTESIAN_POINT('',(3.7338,-28.03398,3.93647083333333));
#1491=CARTESIAN_POINT('',(3.7338,-28.03398,3.96769166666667));
#1492=CARTESIAN_POINT('',(3.7338,-28.03398,4.03013333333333));
#1493=CARTESIAN_POINT('',(3.7338,-28.03398,4.06135416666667));
#1494=CARTESIAN_POINT('',(3.7338,-28.03398,4.12379583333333));
#1495=CARTESIAN_POINT('',(3.7338,-28.03398,4.15501666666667));
#1496=CARTESIAN_POINT('',(3.7338,-28.03398,4.21745833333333));
#1497=CARTESIAN_POINT('',(3.7338,-28.03398,4.24867916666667));
#1498=CARTESIAN_POINT('',(3.7338,-28.03398,4.31112083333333));
#1499=CARTESIAN_POINT('',(3.7338,-28.03398,4.34234166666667));
#1500=CARTESIAN_POINT('',(3.7338,-28.03398,4.40478333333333));
#1501=CARTESIAN_POINT('',(3.7338,-28.03398,4.43600416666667));
#1502=CARTESIAN_POINT('',(3.7338,-28.03398,4.49844583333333));
#1503=CARTESIAN_POINT('',(3.7338,-28.03398,4.52966666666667));
#1504=CARTESIAN_POINT('',(3.7338,-28.03398,4.59210833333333));
#1505=CARTESIAN_POINT('',(3.7338,-28.03398,4.62332916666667));
#1506=CARTESIAN_POINT('',(3.7338,-28.03398,4.68577083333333));
#1507=CARTESIAN_POINT('',(3.7338,-28.03398,4.71699166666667));
#1508=CARTESIAN_POINT('',(3.7338,-28.03398,4.77943333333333));
#1509=CARTESIAN_POINT('',(3.7338,-28.03398,4.81065416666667));
#1510=CARTESIAN_POINT('',(3.7338,-28.03398,4.87309583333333));
#1511=CARTESIAN_POINT('',(3.7338,-28.03398,4.90431666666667));
#1512=CARTESIAN_POINT('',(3.7338,-28.03398,4.96675833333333));
#1513=CARTESIAN_POINT('',(3.7338,-28.03398,4.99797916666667));
#1514=CARTESIAN_POINT('',(3.7338,-28.03398,5.06042083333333));
#1515=CARTESIAN_POINT('',(3.7338,-28.03398,5.09164166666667));
#1516=CARTESIAN_POINT('',(3.7338,-28.03398,5.15408333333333));
#1517=CARTESIAN_POINT('',(3.7338,-28.03398,5.18530416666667));
#1518=CARTESIAN_POINT('',(3.7338,-28.03398,5.24774583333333));
#1519=CARTESIAN_POINT('',(3.7338,-28.03398,5.27896666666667));
#1520=CARTESIAN_POINT('',(3.7338,-28.03398,5.34140833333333));
#1521=CARTESIAN_POINT('',(3.7338,-28.03398,5.37262916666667));
#1522=CARTESIAN_POINT('',(3.7338,-28.03398,5.43507083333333));
#1523=CARTESIAN_POINT('',(3.7338,-28.03398,5.46629166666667));
#1524=CARTESIAN_POINT('',(3.7338,-28.03398,5.52873333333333));
#1525=CARTESIAN_POINT('',(3.7338,-28.03398,5.55995416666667));
#1526=CARTESIAN_POINT('',(3.7338,-28.03398,5.62239583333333));
#1527=CARTESIAN_POINT('',(3.7338,-28.03398,5.65361666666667));
#1528=CARTESIAN_POINT('',(3.7338,-28.03398,5.71605833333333));
#1529=CARTESIAN_POINT('',(3.7338,-28.03398,5.74727916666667));
#1530=CARTESIAN_POINT('',(3.7338,-28.03398,5.80972083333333));
#1531=CARTESIAN_POINT('',(3.7338,-28.03398,5.84094166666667));
#1532=CARTESIAN_POINT('',(3.7338,-28.03398,5.90338333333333));
#1533=CARTESIAN_POINT('',(3.7338,-28.03398,5.93460416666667));
#1534=CARTESIAN_POINT('',(3.7338,-28.03398,5.99704583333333));
#1535=CARTESIAN_POINT('',(3.7338,-28.03398,6.02826666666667));
#1536=CARTESIAN_POINT('',(3.7338,-28.03398,6.09070833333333));
#1537=CARTESIAN_POINT('',(3.7338,-28.03398,6.12192916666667));
#1538=CARTESIAN_POINT('',(3.7338,-28.03398,6.18437083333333));
#1539=CARTESIAN_POINT('',(3.7338,-28.03398,6.21559166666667));
#1540=CARTESIAN_POINT('',(3.7338,-28.03398,6.27803333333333));
#1541=CARTESIAN_POINT('',(3.7338,-28.03398,6.30925416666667));
#1542=CARTESIAN_POINT('',(3.7338,-28.03398,6.37169583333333));
#1543=CARTESIAN_POINT('',(3.7338,-28.03398,6.40291666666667));
#1544=CARTESIAN_POINT('',(3.7338,-28.03398,6.46535833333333));
#1545=CARTESIAN_POINT('',(3.7338,-28.03398,6.49657916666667));
#1546=CARTESIAN_POINT('',(3.7338,-28.03398,6.5278));
#1547=B_SPLINE_CURVE_WITH_KNOTS('',3,(#1481,#1482,#1483,#1484,#1485,#1486,#1487,#1488,#1489,
#1490,#1491,#1492,#1493,#1494,#1495,#1496,#1497,#1498,#1499,#1500,#1501,#1502,#1503,#1504,#1505,
#1506,#1507,#1508,#1509,#1510,#1511,#1512,#1513,#1514,#1515,#1516,#1517,#1518,#1519,#1520,#1521,
#1522,#1523,#1524,#1525,#1526,#1527,#1528,#1529,#1530,#1531,#1532,#1533,#1534,#1535,#1536,#1537,
#1538,#1539,#1540,#1541,#1542,#1543,#1544,#1545,#1546),.UNSPECIFIED.,.F.,.F.,(4,2,2,2,2,2,2,2,2,
2,2,2,2,2,2,2,2,2,2,2,2,2,2,2,2,2,2,2,2,2,2,2,4),(0.,0.0936624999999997,0.187325,0.2809875,
0.37465,0.4683125,0.561975,0.6556375,0.749299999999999,0.842962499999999,0.936624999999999,
1.0302875,1.12395,1.2176125,1.311275,1.4049375,1.4986,1.5922625,1.685925,1.7795875,1.87325,
1.9669125,2.060575,2.1542375,2.2479,2.3415625,2.435225,2.5288875,2.62255,2.7162125,2.809875,
2.9035375,2.9972),.UNSPECIFIED.);
#1548=EDGE_CURVE('BSEAM908',#1479,#757,#1547,.T.);
#1549=ORIENTED_EDGE('',*,*,#1480,.F.);
#1550=ORIENTED_EDGE('',*,*,#758,.T.);
#1551=ORIENTED_EDGE('',*,*,#1548,.T.);
#1552=ORIENTED_EDGE('',*,*,#1548,.F.);
#1553=EDGE_LOOP('',(#1549,#1551,#1550,#1552));
#1554=FACE_BOUND('',#1553,.T.);
#1555=ADVANCED_FACE('F908',(#1554),#1472,.F.);
#1556=CARTESIAN_POINT('',(25.654,-12.5,-15.492000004));
#1557=DIRECTION('',(0.,0.,1.));
#1558=DIRECTION('',(1.,0.,0.));
#1559=AXIS2_PLACEMENT_3D('',#1556,#1557,#1558);
#1560=PLANE('',#1559);
#1561=DIRECTION('',(1.,0.,0.));
#1562=VECTOR('',#1561,1.);
#1563=CARTESIAN_POINT('',(25.654,-19.485,-15.492000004));
#1564=LINE('',#1563,#1562);
#1565=CARTESIAN_POINT('',(15.113,-19.485,-15.492000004));
#1566=VERTEX_POINT('',#1565);
#1567=EDGE_CURVE('E787',#1566,#846,#1564,.T.);
#1568=ORIENTED_EDGE('',*,*,#1567,.F.);
#1569=DIRECTION('',(0.,1.,0.));
#1570=VECTOR('',#1569,1.);
#1571=CARTESIAN_POINT('',(15.113,-24.892,-15.492000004));
#1572=LINE('',#1571,#1570);
#1573=CARTESIAN_POINT('',(15.113,-12.5,-15.492000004));
#1574=VERTEX_POINT('',#1573);
#1575=EDGE_CURVE('E807',#1566,#1574,#1572,.T.);
#1576=ORIENTED_EDGE('',*,*,#1575,.T.);
#1577=DIRECTION('',(1.,0.,0.));
#1578=VECTOR('',#1577,1.);
#1579=CARTESIAN_POINT('',(25.654,-12.5,-15.492000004));
#1580=LINE('',#1579,#1578);
#1581=EDGE_CURVE('E1296',#1574,#854,#1580,.T.);
#1582=ORIENTED_EDGE('',*,*,#1581,.T.);
#1583=ORIENTED_EDGE('',*,*,#855,.T.);
#1584=EDGE_LOOP('',(#1568,#1576,#1582,#1583));
#1585=FACE_BOUND('',#1584,.T.);
#1586=ADVANCED_FACE('F911',(#1585),#1560,.F.);
#1587=CARTESIAN_POINT('',(-1.27,-28.03398,6.5278));
#1588=DIRECTION('',(0.,0.,1.));
#1589=DIRECTION('',(1.,0.,0.));
#1590=AXIS2_PLACEMENT_3D('',#1587,#1588,#1589);
#1591=CYLINDRICAL_SURFACE('',#1590,3.39999999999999);
#1592=ORIENTED_EDGE('',*,*,#1238,.F.);
#1593=EDGE_LOOP('',(#1592));
#1594=FACE_BOUND('',#1593,.T.);
#1595=CARTESIAN_POINT('',(-1.27,-28.03398,3.5306));
#1596=DIRECTION('',(0.,0.,1.));
#1597=DIRECTION('',(1.,0.,0.));
#1598=AXIS2_PLACEMENT_3D('',#1595,#1596,#1597);
#1599=CIRCLE('',#1598,3.39999999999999);
#1600=CARTESIAN_POINT('',(2.12999999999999,-28.03398,3.5306));
#1601=VERTEX_POINT('',#1600);
#1602=EDGE_CURVE('E1285',#1601,#1601,#1599,.F.);
#1603=ORIENTED_EDGE('',*,*,#1602,.F.);
#1604=EDGE_LOOP('',(#1603));
#1605=FACE_BOUND('',#1604,.T.);
#1606=ADVANCED_FACE('F914',(#1594,#1605),#1591,.F.);
#1607=CARTESIAN_POINT('',(32.512,24.13,6.5278));
#1608=DIRECTION('',(-1.,0.,0.));
#1609=DIRECTION('',(0.,-1.,0.));
#1610=AXIS2_PLACEMENT_3D('',#1607,#1608,#1609);
#1611=PLANE('',#1610);
#1612=DIRECTION('',(0.,0.,-1.));
#1613=VECTOR('',#1612,1.);
#1614=CARTESIAN_POINT('',(32.512,12.5,6.5278));
#1615=LINE('',#1614,#1613);
#1616=CARTESIAN_POINT('',(32.512,12.5,4.4958));
#1617=VERTEX_POINT('',#1616);
#1618=EDGE_CURVE('E1318',#1617,#964,#1615,.T.);
#1619=ORIENTED_EDGE('',*,*,#1618,.F.);
#1620=DIRECTION('',(0.,-1.,0.));
#1621=VECTOR('',#1620,1.);
#1622=CARTESIAN_POINT('',(32.512,-12.5,4.4958));
#1623=LINE('',#1622,#1621);
#1624=CARTESIAN_POINT('',(32.512,-12.5,4.49579999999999));
#1625=VERTEX_POINT('',#1624);
#1626=EDGE_CURVE('E1207',#1617,#1625,#1623,.T.);
#1627=ORIENTED_EDGE('',*,*,#1626,.T.);
#1628=DIRECTION('',(0.,0.,-1.));
#1629=VECTOR('',#1628,1.);
#1630=CARTESIAN_POINT('',(32.512,-12.5,6.5278));
#1631=LINE('',#1630,#1629);
#1632=EDGE_CURVE('E1253',#1625,#972,#1631,.T.);
#1633=ORIENTED_EDGE('',*,*,#1632,.T.);
#1634=ORIENTED_EDGE('',*,*,#973,.T.);
#1635=EDGE_LOOP('',(#1619,#1627,#1633,#1634));
#1636=FACE_BOUND('',#1635,.T.);
#1637=ADVANCED_FACE('F917',(#1636),#1611,.F.);
#1638=CARTESIAN_POINT('',(-25.4,24.13,6.5278));
#1639=DIRECTION('',(0.,-1.,0.));
#1640=DIRECTION('',(0.,0.,-1.));
#1641=AXIS2_PLACEMENT_3D('',#1638,#1639,#1640);
#1642=PLANE('',#1641);
#1643=ORIENTED_EDGE('',*,*,#559,.F.);
#1644=DIRECTION('',(0.,0.,1.));
#1645=VECTOR('',#1644,1.);
#1646=CARTESIAN_POINT('',(-11.43,24.13,-22.6314000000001));
#1647=LINE('',#1646,#1645);
#1648=EDGE_CURVE('E585',#1086,#550,#1647,.T.);
#1649=ORIENTED_EDGE('',*,*,#1648,.F.);
#1650=ORIENTED_EDGE('',*,*,#1087,.T.);
#1651=DIRECTION('',(0.,0.,1.));
#1652=VECTOR('',#1651,1.);
#1653=CARTESIAN_POINT('',(-19.939,24.13,6.5278));
#1654=LINE('',#1653,#1652);
#1655=EDGE_CURVE('E1402',#1078,#558,#1654,.T.);
#1656=ORIENTED_EDGE('',*,*,#1655,.T.);
#1657=EDGE_LOOP('',(#1643,#1649,#1650,#1656));
#1658=FACE_BOUND('',#1657,.T.);
#1659=ADVANCED_FACE('F1484',(#1658),#1642,.F.);
#1660=CARTESIAN_POINT('',(-25.4,24.13,6.5278));
#1661=DIRECTION('',(1.,0.,0.));
#1662=DIRECTION('',(0.,1.,0.));
#1663=AXIS2_PLACEMENT_3D('',#1660,#1661,#1662);
#1664=PLANE('',#1663);
#1665=ORIENTED_EDGE('',*,*,#592,.F.);
#1666=DIRECTION('',(0.,0.,-1.));
#1667=VECTOR('',#1666,1.);
#1668=CARTESIAN_POINT('',(-25.4,10.1599999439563,6.5278));
#1669=LINE('',#1668,#1667);
#1670=EDGE_CURVE('E717',#583,#1053,#1669,.T.);
#1671=ORIENTED_EDGE('',*,*,#1670,.T.);
#1672=ORIENTED_EDGE('',*,*,#1054,.T.);
#1673=DIRECTION('',(0.,0.,-1.));
#1674=VECTOR('',#1673,1.);
#1675=CARTESIAN_POINT('',(-25.4,-10.1600000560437,6.5278));
#1676=LINE('',#1675,#1674);
#1677=EDGE_CURVE('E724',#591,#1045,#1676,.T.);
#1678=ORIENTED_EDGE('',*,*,#1677,.F.);
#1679=EDGE_LOOP('',(#1665,#1671,#1672,#1678));
#1680=FACE_BOUND('',#1679,.T.);
#1681=ADVANCED_FACE('F1516',(#1680),#1664,.F.);
#1682=CARTESIAN_POINT('',(-25.4,-43.27398,6.5278));
#1683=DIRECTION('',(0.,1.,0.));
#1684=DIRECTION('',(0.,0.,1.));
#1685=AXIS2_PLACEMENT_3D('',#1682,#1683,#1684);
#1686=PLANE('',#1685);
#1687=ORIENTED_EDGE('',*,*,#1447,.F.);
#1688=ORIENTED_EDGE('',*,*,#207,.F.);
#1689=DIRECTION('',(0.,0.,-1.));
#1690=VECTOR('',#1689,1.);
#1691=CARTESIAN_POINT('',(-7.23900000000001,-43.27398,6.5278));
#1692=LINE('',#1691,#1690);
#1693=CARTESIAN_POINT('',(-7.23900000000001,-43.27398,3.19405));
#1694=VERTEX_POINT('',#1693);
#1695=EDGE_CURVE('E1181',#103,#1694,#1692,.T.);
#1696=ORIENTED_EDGE('',*,*,#1695,.T.);
#1697=DIRECTION('',(-1.,0.,0.));
#1698=VECTOR('',#1697,1.);
#1699=CARTESIAN_POINT('',(9.77899999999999,-43.27398,3.19405));
#1700=LINE('',#1699,#1698);
#1701=EDGE_CURVE('E703',#1446,#1694,#1700,.T.);
#1702=ORIENTED_EDGE('',*,*,#1701,.F.);
#1703=EDGE_LOOP('',(#1687,#1688,#1696,#1702));
#1704=FACE_BOUND('',#1703,.T.);
#1705=ADVANCED_FACE('F936',(#1704),#1686,.F.);
#1706=CARTESIAN_POINT('',(32.512,-12.5,6.5278));
#1707=DIRECTION('',(0.,1.,0.));
#1708=DIRECTION('',(0.,0.,1.));
#1709=AXIS2_PLACEMENT_3D('',#1706,#1707,#1708);
#1710=PLANE('',#1709);
#1711=ORIENTED_EDGE('',*,*,#705,.F.);
#1712=DIRECTION('',(0.,0.,-1.));
#1713=VECTOR('',#1712,1.);
#1714=CARTESIAN_POINT('',(29.21,-12.5,0.));
#1715=LINE('',#1714,#1713);
#1716=EDGE_CURVE('E1231',#696,#980,#1715,.T.);
#1717=ORIENTED_EDGE('',*,*,#1716,.T.);
#1718=ORIENTED_EDGE('',*,*,#981,.T.);
#1719=ORIENTED_EDGE('',*,*,#1632,.F.);
#1720=DIRECTION('',(-0.707106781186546,0.,0.707106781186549));
#1721=VECTOR('',#1720,1.);
#1722=CARTESIAN_POINT('',(30.48,-12.5,6.5278));
#1723=LINE('',#1722,#1721);
#1724=EDGE_CURVE('E1209',#1625,#704,#1723,.T.);
#1725=ORIENTED_EDGE('',*,*,#1724,.T.);
#1726=EDGE_LOOP('',(#1711,#1717,#1718,#1719,#1725));
#1727=FACE_BOUND('',#1726,.T.);
#1728=ADVANCED_FACE('F932',(#1727),#1710,.F.);
#1729=CARTESIAN_POINT('',(15.113,-24.892,-15.492000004));
#1730=DIRECTION('',(1.,0.,0.));
#1731=DIRECTION('',(0.,0.,-1.));
#1732=AXIS2_PLACEMENT_3D('',#1729,#1730,#1731);
#1733=PLANE('',#1732);
#1734=ORIENTED_EDGE('',*,*,#1003,.T.);
#1735=DIRECTION('',(0.,0.,1.));
#1736=VECTOR('',#1735,1.);
#1737=CARTESIAN_POINT('',(15.113,-12.5,-15.492000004));
#1738=LINE('',#1737,#1736);
#1739=EDGE_CURVE('E1282',#1574,#996,#1738,.T.);
#1740=ORIENTED_EDGE('',*,*,#1739,.F.);
#1741=ORIENTED_EDGE('',*,*,#1575,.F.);
#1742=DIRECTION('',(0.,0.,1.));
#1743=VECTOR('',#1742,1.);
#1744=CARTESIAN_POINT('',(15.113,-19.485,-15.873000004));
#1745=LINE('',#1744,#1743);
#1746=CARTESIAN_POINT('',(15.113,-19.485,-15.873000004));
#1747=VERTEX_POINT('',#1746);
#1748=EDGE_CURVE('E812',#1747,#1566,#1745,.T.);
#1749=ORIENTED_EDGE('',*,*,#1748,.F.);
#1750=DIRECTION('',(0.,1.,0.));
#1751=VECTOR('',#1750,1.);
#1752=CARTESIAN_POINT('',(15.113,-24.892,-15.873000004));
#1753=LINE('',#1752,#1751);
#1754=EDGE_CURVE('E794',#799,#1747,#1753,.T.);
#1755=ORIENTED_EDGE('',*,*,#1754,.F.);
#1756=ORIENTED_EDGE('',*,*,#800,.T.);
#1757=EDGE_LOOP('',(#1734,#1740,#1741,#1749,#1755,#1756));
#1758=FACE_BOUND('',#1757,.T.);
#1759=ADVANCED_FACE('F928',(#1758),#1733,.F.);
#1760=CARTESIAN_POINT('',(25.654,-12.5,-15.492000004));
#1761=DIRECTION('',(0.,-1.,0.));
#1762=DIRECTION('',(0.,0.,-1.));
#1763=AXIS2_PLACEMENT_3D('',#1760,#1761,#1762);
#1764=PLANE('',#1763);
#1765=ORIENTED_EDGE('',*,*,#997,.T.);
#1766=ORIENTED_EDGE('',*,*,#863,.F.);
#1767=ORIENTED_EDGE('',*,*,#1581,.F.);
#1768=ORIENTED_EDGE('',*,*,#1739,.T.);
#1769=EDGE_LOOP('',(#1765,#1766,#1767,#1768));
#1770=FACE_BOUND('',#1769,.T.);
#1771=ADVANCED_FACE('F921',(#1770),#1764,.F.);
#1772=CARTESIAN_POINT('',(3.302,24.13,6.5278));
#1773=DIRECTION('',(1.,0.,0.));
#1774=DIRECTION('',(0.,0.,-1.));
#1775=AXIS2_PLACEMENT_3D('',#1772,#1773,#1774);
#1776=PLANE('',#1775);
#1777=DIRECTION('',(0.,0.,-1.));
#1778=VECTOR('',#1777,1.);
#1779=CARTESIAN_POINT('',(3.302,16.056,6.5278));
#1780=LINE('',#1779,#1778);
#1781=EDGE_CURVE('E1226',#729,#954,#1780,.T.);
#1782=ORIENTED_EDGE('',*,*,#1781,.T.);
#1783=ORIENTED_EDGE('',*,*,#1172,.F.);
#1784=DIRECTION('',(0.,0.,1.));
#1785=VECTOR('',#1784,1.);
#1786=CARTESIAN_POINT('',(3.302,14.605,-22.6314));
#1787=LINE('',#1786,#1785);
#1788=CARTESIAN_POINT('',(3.302,14.605,-3.8862));
#1789=VERTEX_POINT('',#1788);
#1790=EDGE_CURVE('E600',#1789,#1165,#1787,.T.);
#1791=ORIENTED_EDGE('',*,*,#1790,.F.);
#1792=DIRECTION('',(0.,1.,0.));
#1793=VECTOR('',#1792,1.);
#1794=CARTESIAN_POINT('',(3.302,14.605,-3.8862));
#1795=LINE('',#1794,#1793);
#1796=CARTESIAN_POINT('',(3.302,22.098,-3.8862));
#1797=VERTEX_POINT('',#1796);
#1798=EDGE_CURVE('E1464',#1789,#1797,#1795,.T.);
#1799=ORIENTED_EDGE('',*,*,#1798,.T.);
#1800=DIRECTION('',(0.,0.,1.));
#1801=VECTOR('',#1800,1.);
#1802=CARTESIAN_POINT('',(3.302,22.098,0.));
#1803=LINE('',#1802,#1801);
#1804=EDGE_CURVE('E1336',#1797,#542,#1803,.T.);
#1805=ORIENTED_EDGE('',*,*,#1804,.T.);
#1806=ORIENTED_EDGE('',*,*,#736,.T.);
#1807=EDGE_LOOP('',(#1782,#1783,#1791,#1799,#1805,#1806));
#1808=FACE_BOUND('',#1807,.T.);
#1809=ADVANCED_FACE('F906',(#1808),#1776,.T.);
#1810=CARTESIAN_POINT('',(-1.27,-28.03398,3.5306));
#1811=DIRECTION('',(0.,0.,1.));
#1812=DIRECTION('',(1.,0.,0.));
#1813=AXIS2_PLACEMENT_3D('',#1810,#1811,#1812);
#1814=PLANE('',#1813);
#1815=ORIENTED_EDGE('',*,*,#1480,.T.);
#1816=EDGE_LOOP('',(#1815));
#1817=FACE_BOUND('',#1816,.T.);
#1818=ORIENTED_EDGE('',*,*,#1602,.T.);
#1819=EDGE_LOOP('',(#1818));
#1820=FACE_BOUND('',#1819,.T.);
#1821=ADVANCED_FACE('F902',(#1817,#1820),#1814,.T.);
#1822=CARTESIAN_POINT('',(32.512,12.5,6.5278));
#1823=DIRECTION('',(0.,-1.,0.));
#1824=DIRECTION('',(0.,0.,-1.));
#1825=AXIS2_PLACEMENT_3D('',#1822,#1823,#1824);
#1826=PLANE('',#1825);
#1827=ORIENTED_EDGE('',*,*,#965,.T.);
#1828=DIRECTION('',(0.,0.,-1.));
#1829=VECTOR('',#1828,1.);
#1830=CARTESIAN_POINT('',(6.858,12.5,6.5278));
#1831=LINE('',#1830,#1829);
#1832=EDGE_CURVE('E1229',#956,#720,#1831,.F.);
#1833=ORIENTED_EDGE('',*,*,#1832,.T.);
#1834=ORIENTED_EDGE('',*,*,#721,.F.);
#1835=DIRECTION('',(0.707106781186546,0.,-0.707106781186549));
#1836=VECTOR('',#1835,1.);
#1837=CARTESIAN_POINT('',(30.48,12.5,6.52779999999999));
#1838=LINE('',#1837,#1836);
#1839=EDGE_CURVE('E1205',#712,#1617,#1838,.T.);
#1840=ORIENTED_EDGE('',*,*,#1839,.T.);
#1841=ORIENTED_EDGE('',*,*,#1618,.T.);
#1842=EDGE_LOOP('',(#1827,#1833,#1834,#1840,#1841));
#1843=FACE_BOUND('',#1842,.T.);
#1844=ADVANCED_FACE('F898',(#1843),#1826,.F.);
#1845=CARTESIAN_POINT('',(-6.35,14.605,-22.6314));
#1846=DIRECTION('',(0.,1.,0.));
#1847=DIRECTION('',(0.,0.,1.));
#1848=AXIS2_PLACEMENT_3D('',#1845,#1846,#1847);
#1849=PLANE('',#1848);
#1850=CARTESIAN_POINT('',(0.127,14.605,-19.7104000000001));
#1851=DIRECTION('',(0.,1.,0.));
#1852=DIRECTION('',(0.,0.,1.));
#1853=AXIS2_PLACEMENT_3D('',#1850,#1851,#1852);
#1854=CIRCLE('',#1853,1.28905);
#1855=CARTESIAN_POINT('',(0.127,14.605,-18.4213500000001));
#1856=VERTEX_POINT('',#1855);
#1857=EDGE_CURVE('E772',#1856,#1856,#1854,.T.);
#1858=ORIENTED_EDGE('',*,*,#1857,.T.);
#1859=EDGE_LOOP('',(#1858));
#1860=FACE_BOUND('',#1859,.T.);
#1861=CARTESIAN_POINT('',(-4.98475,14.605,-6.26745000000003));
#1862=DIRECTION('',(0.,1.,0.));
#1863=DIRECTION('',(0.,0.,1.));
#1864=AXIS2_PLACEMENT_3D('',#1861,#1862,#1863);
#1865=CIRCLE('',#1864,2.38125);
#1866=CARTESIAN_POINT('',(-4.98475,14.605,-3.88620000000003));
#1867=VERTEX_POINT('',#1866);
#1868=CARTESIAN_POINT('',(-7.366,14.605,-6.26745000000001));
#1869=VERTEX_POINT('',#1868);
#1870=EDGE_CURVE('E1356',#1867,#1869,#1865,.F.);
#1871=ORIENTED_EDGE('',*,*,#1870,.F.);
#1872=DIRECTION('',(-1.,0.,0.));
#1873=VECTOR('',#1872,1.);
#1874=CARTESIAN_POINT('',(11.7428293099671,14.605,-3.8862));
#1875=LINE('',#1874,#1873);
#1876=EDGE_CURVE('E1355',#1789,#1867,#1875,.T.);
#1877=ORIENTED_EDGE('',*,*,#1876,.F.);
#1878=ORIENTED_EDGE('',*,*,#1790,.T.);
#1879=ORIENTED_EDGE('',*,*,#1166,.T.);
#1880=CARTESIAN_POINT('',(0.127000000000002,14.605,-0.660400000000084));
#1881=DIRECTION('',(0.,1.,0.));
#1882=DIRECTION('',(0.,0.,1.));
#1883=AXIS2_PLACEMENT_3D('',#1880,#1881,#1882);
#1884=CIRCLE('',#1883,1.28905);
#1885=EDGE_CURVE('E766',#1161,#1110,#1884,.T.);
#1886=ORIENTED_EDGE('',*,*,#1885,.T.);
#1887=ORIENTED_EDGE('',*,*,#1111,.T.);
#1888=DIRECTION('',(0.,0.,1.));
#1889=VECTOR('',#1888,1.);
#1890=CARTESIAN_POINT('',(-11.43,14.605,-22.6314));
#1891=LINE('',#1890,#1889);
#1892=CARTESIAN_POINT('',(-11.43,14.605,-22.6314));
#1893=VERTEX_POINT('',#1892);
#1894=EDGE_CURVE('E1373',#1893,#1102,#1891,.T.);
#1895=ORIENTED_EDGE('',*,*,#1894,.F.);
#1896=DIRECTION('',(-1.,0.,0.));
#1897=VECTOR('',#1896,1.);
#1898=CARTESIAN_POINT('',(-6.35,14.605,-22.6314));
#1899=LINE('',#1898,#1897);
#1900=CARTESIAN_POINT('',(3.302,14.605,-22.6314));
#1901=VERTEX_POINT('',#1900);
#1902=EDGE_CURVE('E1367',#1901,#1893,#1899,.T.);
#1903=ORIENTED_EDGE('',*,*,#1902,.F.);
#1904=DIRECTION('',(0.,0.,-1.));
#1905=VECTOR('',#1904,1.);
#1906=CARTESIAN_POINT('',(3.302,14.605,-22.6314));
#1907=LINE('',#1906,#1905);
#1908=CARTESIAN_POINT('',(3.302,14.605,-16.4846));
#1909=VERTEX_POINT('',#1908);
#1910=EDGE_CURVE('E423',#1909,#1901,#1907,.T.);
#1911=ORIENTED_EDGE('',*,*,#1910,.F.);
#1912=DIRECTION('',(-1.,0.,0.));
#1913=VECTOR('',#1912,1.);
#1914=CARTESIAN_POINT('',(12.9936561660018,14.605,-16.4846));
#1915=LINE('',#1914,#1913);
#1916=CARTESIAN_POINT('',(-4.98475,14.605,-16.4846));
#1917=VERTEX_POINT('',#1916);
#1918=EDGE_CURVE('E416',#1909,#1917,#1915,.T.);
#1919=ORIENTED_EDGE('',*,*,#1918,.T.);
#1920=CARTESIAN_POINT('',(-4.98475,14.605,-14.10335));
#1921=DIRECTION('',(0.,1.,0.));
#1922=DIRECTION('',(0.,0.,1.));
#1923=AXIS2_PLACEMENT_3D('',#1920,#1921,#1922);
#1924=CIRCLE('',#1923,2.38125);
#1925=CARTESIAN_POINT('',(-7.366,14.605,-14.1033500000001));
#1926=VERTEX_POINT('',#1925);
#1927=EDGE_CURVE('E421',#1926,#1917,#1924,.F.);
#1928=ORIENTED_EDGE('',*,*,#1927,.F.);
#1929=DIRECTION('',(0.,0.,-1.));
#1930=VECTOR('',#1929,1.);
#1931=CARTESIAN_POINT('',(-7.366,14.605,-14.1033500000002));
#1932=LINE('',#1931,#1930);
#1933=EDGE_CURVE('E437',#1869,#1926,#1932,.T.);
#1934=ORIENTED_EDGE('',*,*,#1933,.F.);
#1935=EDGE_LOOP('',(#1871,#1877,#1878,#1879,#1886,#1887,#1895,#1903,#1911,#1919,#1928,#1934));
#1936=FACE_BOUND('',#1935,.T.);
#1937=ADVANCED_FACE('F419',(#1860,#1936),#1849,.F.);
#1938=CARTESIAN_POINT('',(-11.43,24.13,-22.6314));
#1939=DIRECTION('',(1.,0.,0.));
#1940=DIRECTION('',(0.,1.,0.));
#1941=AXIS2_PLACEMENT_3D('',#1938,#1939,#1940);
#1942=PLANE('',#1941);
#1943=ORIENTED_EDGE('',*,*,#1103,.T.);
#1944=DIRECTION('',(0.,0.,1.));
#1945=VECTOR('',#1944,1.);
#1946=CARTESIAN_POINT('',(-11.43,22.098,-22.6314));
#1947=LINE('',#1946,#1945);
#1948=CARTESIAN_POINT('',(-11.43,22.098,-22.6314000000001));
#1949=VERTEX_POINT('',#1948);
#1950=EDGE_CURVE('E588',#1949,#1094,#1947,.T.);
#1951=ORIENTED_EDGE('',*,*,#1950,.F.);
#1952=DIRECTION('',(0.,1.,0.));
#1953=VECTOR('',#1952,1.);
#1954=CARTESIAN_POINT('',(-11.43,24.13,-22.6314));
#1955=LINE('',#1954,#1953);
#1956=EDGE_CURVE('E1369',#1893,#1949,#1955,.T.);
#1957=ORIENTED_EDGE('',*,*,#1956,.F.);
#1958=ORIENTED_EDGE('',*,*,#1894,.T.);
#1959=EDGE_LOOP('',(#1943,#1951,#1957,#1958));
#1960=FACE_BOUND('',#1959,.T.);
#1961=ADVANCED_FACE('F891',(#1960),#1942,.F.);
#1962=CARTESIAN_POINT('',(-6.35,14.605,-22.6314));
#1963=DIRECTION('',(0.,0.,-1.));
#1964=DIRECTION('',(-1.,0.,0.));
#1965=AXIS2_PLACEMENT_3D('',#1962,#1963,#1964);
#1966=PLANE('',#1965);
#1967=ORIENTED_EDGE('',*,*,#1956,.T.);
#1968=DIRECTION('',(-1.,0.,0.));
#1969=VECTOR('',#1968,1.);
#1970=CARTESIAN_POINT('',(12.9936561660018,22.098,-22.6314));
#1971=LINE('',#1970,#1969);
#1972=CARTESIAN_POINT('',(3.302,22.098,-22.6314));
#1973=VERTEX_POINT('',#1972);
#1974=EDGE_CURVE('E1467',#1973,#1949,#1971,.T.);
#1975=ORIENTED_EDGE('',*,*,#1974,.F.);
#1976=DIRECTION('',(0.,1.,0.));
#1977=VECTOR('',#1976,1.);
#1978=CARTESIAN_POINT('',(3.302,14.605,-22.6314));
#1979=LINE('',#1978,#1977);
#1980=EDGE_CURVE('E1470',#1901,#1973,#1979,.T.);
#1981=ORIENTED_EDGE('',*,*,#1980,.F.);
#1982=ORIENTED_EDGE('',*,*,#1902,.T.);
#1983=EDGE_LOOP('',(#1967,#1975,#1981,#1982));
#1984=FACE_BOUND('',#1983,.T.);
#1985=ADVANCED_FACE('F887',(#1984),#1966,.T.);
#1986=CARTESIAN_POINT('',(11.7428293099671,14.605,-3.8862));
#1987=DIRECTION('',(0.,0.,1.));
#1988=DIRECTION('',(1.,0.,0.));
#1989=AXIS2_PLACEMENT_3D('',#1986,#1987,#1988);
#1990=PLANE('',#1989);
#1991=ORIENTED_EDGE('',*,*,#1798,.F.);
#1992=ORIENTED_EDGE('',*,*,#1876,.T.);
#1993=DIRECTION('',(0.,1.,0.));
#1994=VECTOR('',#1993,1.);
#1995=CARTESIAN_POINT('',(-4.98474999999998,-43.2749800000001,-3.88620000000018));
#1996=LINE('',#1995,#1994);
#1997=CARTESIAN_POINT('',(-4.98475000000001,22.098,-3.88620000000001));
#1998=VERTEX_POINT('',#1997);
#1999=EDGE_CURVE('E500',#1867,#1998,#1996,.T.);
#2000=ORIENTED_EDGE('',*,*,#1999,.T.);
#2001=DIRECTION('',(-1.,0.,0.));
#2002=VECTOR('',#2001,1.);
#2003=CARTESIAN_POINT('',(11.7428293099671,22.098,-3.8862));
#2004=LINE('',#2003,#2002);
#2005=EDGE_CURVE('E1359',#1797,#1998,#2004,.T.);
#2006=ORIENTED_EDGE('',*,*,#2005,.F.);
#2007=EDGE_LOOP('',(#1991,#1992,#2000,#2006));
#2008=FACE_BOUND('',#2007,.T.);
#2009=ADVANCED_FACE('F883',(#2008),#1990,.F.);
#2010=CARTESIAN_POINT('',(11.7428293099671,22.098,0.));
#2011=DIRECTION('',(0.,-1.,0.));
#2012=DIRECTION('',(0.,0.,-1.));
#2013=AXIS2_PLACEMENT_3D('',#2010,#2011,#2012);
#2014=PLANE('',#2013);
#2015=CARTESIAN_POINT('',(0.127000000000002,22.098,-0.660400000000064));
#2016=DIRECTION('',(0.,1.,0.));
#2017=DIRECTION('',(0.,0.,1.));
#2018=AXIS2_PLACEMENT_3D('',#2015,#2016,#2017);
#2019=CIRCLE('',#2018,1.28905);
#2020=CARTESIAN_POINT('',(0.127000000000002,22.098,0.628649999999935));
#2021=VERTEX_POINT('',#2020);
#2022=EDGE_CURVE('E763',#2021,#2021,#2019,.T.);
#2023=ORIENTED_EDGE('',*,*,#2022,.F.);
#2024=EDGE_LOOP('',(#2023));
#2025=FACE_BOUND('',#2024,.T.);
#2026=ORIENTED_EDGE('',*,*,#2005,.T.);
#2027=CARTESIAN_POINT('',(-4.98475000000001,22.098,-6.26745000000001));
#2028=DIRECTION('',(0.,1.,0.));
#2029=DIRECTION('',(0.,0.,-1.));
#2030=AXIS2_PLACEMENT_3D('',#2027,#2028,#2029);
#2031=CIRCLE('',#2030,2.38125);
#2032=CARTESIAN_POINT('',(-7.366,22.098,-6.26745000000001));
#2033=VERTEX_POINT('',#2032);
#2034=EDGE_CURVE('E442',#2033,#1998,#2031,.T.);
#2035=ORIENTED_EDGE('',*,*,#2034,.F.);
#2036=DIRECTION('',(0.,0.,1.));
#2037=VECTOR('',#2036,1.);
#2038=CARTESIAN_POINT('',(-7.366,22.098,-14.10335));
#2039=LINE('',#2038,#2037);
#2040=CARTESIAN_POINT('',(-7.36600000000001,22.098,-14.10335));
#2041=VERTEX_POINT('',#2040);
#2042=EDGE_CURVE('E447',#2041,#2033,#2039,.T.);
#2043=ORIENTED_EDGE('',*,*,#2042,.F.);
#2044=CARTESIAN_POINT('',(-4.98475000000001,22.098,-14.10335));
#2045=DIRECTION('',(0.,1.,0.));
#2046=DIRECTION('',(0.,0.,1.));
#2047=AXIS2_PLACEMENT_3D('',#2044,#2045,#2046);
#2048=CIRCLE('',#2047,2.38125);
#2049=CARTESIAN_POINT('',(-4.98475000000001,22.098,-16.4846));
#2050=VERTEX_POINT('',#2049);
#2051=EDGE_CURVE('E1450',#2050,#2041,#2048,.T.);
#2052=ORIENTED_EDGE('',*,*,#2051,.F.);
#2053=DIRECTION('',(-1.,0.,0.));
#2054=VECTOR('',#2053,1.);
#2055=CARTESIAN_POINT('',(12.9936561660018,22.098,-16.4846));
#2056=LINE('',#2055,#2054);
#2057=CARTESIAN_POINT('',(3.302,22.098,-16.4846));
#2058=VERTEX_POINT('',#2057);
#2059=EDGE_CURVE('E427',#2058,#2050,#2056,.T.);
#2060=ORIENTED_EDGE('',*,*,#2059,.F.);
#2061=DIRECTION('',(0.,0.,1.));
#2062=VECTOR('',#2061,1.);
#2063=CARTESIAN_POINT('',(3.302,22.098,-22.6314));
#2064=LINE('',#2063,#2062);
#2065=EDGE_CURVE('E1363',#1973,#2058,#2064,.T.);
#2066=ORIENTED_EDGE('',*,*,#2065,.F.);
#2067=ORIENTED_EDGE('',*,*,#1974,.T.);
#2068=ORIENTED_EDGE('',*,*,#1950,.T.);
#2069=EDGE_CURVE('E587',#1094,#540,#1947,.T.);
#2070=ORIENTED_EDGE('',*,*,#2069,.T.);
#2071=ORIENTED_EDGE('',*,*,#543,.T.);
#2072=ORIENTED_EDGE('',*,*,#1804,.F.);
#2073=EDGE_LOOP('',(#2026,#2035,#2043,#2052,#2060,#2066,#2067,#2068,#2070,#2071,#2072));
#2074=FACE_BOUND('',#2073,.T.);
#2075=CARTESIAN_POINT('',(0.127,22.098,-19.7104000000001));
#2076=DIRECTION('',(0.,1.,0.));
#2077=DIRECTION('',(0.,0.,1.));
#2078=AXIS2_PLACEMENT_3D('',#2075,#2076,#2077);
#2079=CIRCLE('',#2078,1.28905);
#2080=CARTESIAN_POINT('',(0.127,22.098,-18.4213500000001));
#2081=VERTEX_POINT('',#2080);
#2082=EDGE_CURVE('E769',#2081,#2081,#2079,.T.);
#2083=ORIENTED_EDGE('',*,*,#2082,.F.);
#2084=EDGE_LOOP('',(#2083));
#2085=FACE_BOUND('',#2084,.T.);
#2086=ADVANCED_FACE('F877',(#2025,#2074,#2085),#2014,.F.);
#2087=CARTESIAN_POINT('',(12.9936561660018,14.605,-16.4846));
#2088=DIRECTION('',(0.,0.,-1.));
#2089=DIRECTION('',(-1.,0.,0.));
#2090=AXIS2_PLACEMENT_3D('',#2087,#2088,#2089);
#2091=PLANE('',#2090);
#2092=ORIENTED_EDGE('',*,*,#2059,.T.);
#2093=DIRECTION('',(0.,1.,0.));
#2094=VECTOR('',#2093,1.);
#2095=CARTESIAN_POINT('',(-4.98474999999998,-43.27498,-16.4846000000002));
#2096=LINE('',#2095,#2094);
#2097=EDGE_CURVE('E434',#1917,#2050,#2096,.T.);
#2098=ORIENTED_EDGE('',*,*,#2097,.F.);
#2099=ORIENTED_EDGE('',*,*,#1918,.F.);
#2100=DIRECTION('',(0.,-1.,0.));
#2101=VECTOR('',#2100,1.);
#2102=CARTESIAN_POINT('',(3.302,14.605,-16.4846));
#2103=LINE('',#2102,#2101);
#2104=EDGE_CURVE('E1360',#2058,#1909,#2103,.T.);
#2105=ORIENTED_EDGE('',*,*,#2104,.F.);
#2106=EDGE_LOOP('',(#2092,#2098,#2099,#2105));
#2107=FACE_BOUND('',#2106,.T.);
#2108=ADVANCED_FACE('F440',(#2107),#2091,.F.);
#2109=CARTESIAN_POINT('',(3.302,24.13,6.5278));
#2110=DIRECTION('',(1.,0.,0.));
#2111=DIRECTION('',(0.,0.,-1.));
#2112=AXIS2_PLACEMENT_3D('',#2109,#2110,#2111);
#2113=PLANE('',#2112);
#2114=ORIENTED_EDGE('',*,*,#1910,.T.);
#2115=ORIENTED_EDGE('',*,*,#1980,.T.);
#2116=ORIENTED_EDGE('',*,*,#2065,.T.);
#2117=ORIENTED_EDGE('',*,*,#2104,.T.);
#2118=EDGE_LOOP('',(#2114,#2115,#2116,#2117));
#2119=FACE_BOUND('',#2118,.T.);
#2120=ADVANCED_FACE('F873',(#2119),#2113,.T.);
#2121=CARTESIAN_POINT('',(25.654,-19.485,-15.873000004));
#2122=DIRECTION('',(0.,-1.,0.));
#2123=DIRECTION('',(0.,0.,-1.));
#2124=AXIS2_PLACEMENT_3D('',#2121,#2122,#2123);
#2125=PLANE('',#2124);
#2126=ORIENTED_EDGE('',*,*,#1567,.T.);
#2127=ORIENTED_EDGE('',*,*,#847,.F.);
#2128=DIRECTION('',(1.,0.,0.));
#2129=VECTOR('',#2128,1.);
#2130=CARTESIAN_POINT('',(25.654,-19.485,-15.873000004));
#2131=LINE('',#2130,#2129);
#2132=EDGE_CURVE('E796',#1747,#838,#2131,.T.);
#2133=ORIENTED_EDGE('',*,*,#2132,.F.);
#2134=ORIENTED_EDGE('',*,*,#1748,.T.);
#2135=EDGE_LOOP('',(#2126,#2127,#2133,#2134));
#2136=FACE_BOUND('',#2135,.T.);
#2137=ADVANCED_FACE('F869',(#2136),#2125,.F.);
#2138=CARTESIAN_POINT('',(25.654,-19.485,-15.873000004));
#2139=DIRECTION('',(0.,0.,1.));
#2140=DIRECTION('',(1.,0.,0.));
#2141=AXIS2_PLACEMENT_3D('',#2138,#2139,#2140);
#2142=PLANE('',#2141);
#2143=CARTESIAN_POINT('',(18.161,-21.9436,-15.873000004));
#2144=DIRECTION('',(0.,0.,-1.));
#2145=DIRECTION('',(-1.,0.,0.));
#2146=AXIS2_PLACEMENT_3D('',#2143,#2144,#2145);
#2147=CIRCLE('',#2146,1.13029999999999);
#2148=CARTESIAN_POINT('',(17.0307,-21.9436,-15.873000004));
#2149=VERTEX_POINT('',#2148);
#2150=EDGE_CURVE('E778',#2149,#2149,#2147,.T.);
#2151=ORIENTED_EDGE('',*,*,#2150,.F.);
#2152=EDGE_LOOP('',(#2151));
#2153=FACE_BOUND('',#2152,.T.);
#2154=CARTESIAN_POINT('',(23.368,-21.9436,-15.873000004));
#2155=DIRECTION('',(0.,0.,-1.));
#2156=DIRECTION('',(-1.,0.,0.));
#2157=AXIS2_PLACEMENT_3D('',#2154,#2155,#2156);
#2158=CIRCLE('',#2157,1.19062499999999);
#2159=CARTESIAN_POINT('',(22.177375,-21.9436,-15.873000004));
#2160=VERTEX_POINT('',#2159);
#2161=EDGE_CURVE('E784',#2160,#2160,#2158,.T.);
#2162=ORIENTED_EDGE('',*,*,#2161,.F.);
#2163=EDGE_LOOP('',(#2162));
#2164=FACE_BOUND('',#2163,.T.);
#2165=ORIENTED_EDGE('',*,*,#839,.T.);
#2166=ORIENTED_EDGE('',*,*,#808,.T.);
#2167=ORIENTED_EDGE('',*,*,#1754,.T.);
#2168=ORIENTED_EDGE('',*,*,#2132,.T.);
#2169=EDGE_LOOP('',(#2165,#2166,#2167,#2168));
#2170=FACE_BOUND('',#2169,.T.);
#2171=ADVANCED_FACE('F865',(#2153,#2164,#2170),#2142,.F.);
#2172=CARTESIAN_POINT('',(23.368,-21.9436,-15.873000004));
#2173=DIRECTION('',(0.,0.,-1.));
#2174=DIRECTION('',(-1.,0.,0.));
#2175=AXIS2_PLACEMENT_3D('',#2172,#2173,#2174);
#2176=CYLINDRICAL_SURFACE('',#2175,1.19062499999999);
#2177=CARTESIAN_POINT('',(23.368,-21.9436,-10.158000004));
#2178=DIRECTION('',(0.,0.,-1.));
#2179=DIRECTION('',(-1.,0.,0.));
#2180=AXIS2_PLACEMENT_3D('',#2177,#2178,#2179);
#2181=CIRCLE('',#2180,1.190625);
#2182=CARTESIAN_POINT('',(22.177375,-21.9436,-10.158000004));
#2183=VERTEX_POINT('',#2182);
#2184=EDGE_CURVE('E781',#2183,#2183,#2181,.T.);
#2185=ORIENTED_EDGE('',*,*,#2184,.F.);
#2186=EDGE_LOOP('',(#2185));
#2187=FACE_BOUND('',#2186,.T.);
#2188=ORIENTED_EDGE('',*,*,#2161,.T.);
#2189=EDGE_LOOP('',(#2188));
#2190=FACE_BOUND('',#2189,.T.);
#2191=ADVANCED_FACE('F861',(#2187,#2190),#2176,.F.);
#2192=CARTESIAN_POINT('',(23.368,-21.9436,-10.158000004));
#2193=DIRECTION('',(0.,0.,1.));
#2194=DIRECTION('',(1.,0.,0.));
#2195=AXIS2_PLACEMENT_3D('',#2192,#2193,#2194);
#2196=PLANE('',#2195);
#2197=ORIENTED_EDGE('',*,*,#2184,.T.);
#2198=EDGE_LOOP('',(#2197));
#2199=FACE_BOUND('',#2198,.T.);
#2200=ADVANCED_FACE('F857',(#2199),#2196,.F.);
#2201=CARTESIAN_POINT('',(18.161,-21.9436,-15.873000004));
#2202=DIRECTION('',(0.,0.,-1.));
#2203=DIRECTION('',(-1.,0.,0.));
#2204=AXIS2_PLACEMENT_3D('',#2201,#2202,#2203);
#2205=CYLINDRICAL_SURFACE('',#2204,1.13029999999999);
#2206=CARTESIAN_POINT('',(18.161,-21.9436,-4.316000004));
#2207=DIRECTION('',(0.,0.,-1.));
#2208=DIRECTION('',(-1.,0.,0.));
#2209=AXIS2_PLACEMENT_3D('',#2206,#2207,#2208);
#2210=CIRCLE('',#2209,1.1303);
#2211=CARTESIAN_POINT('',(17.0307,-21.9436,-4.316000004));
#2212=VERTEX_POINT('',#2211);
#2213=EDGE_CURVE('E775',#2212,#2212,#2210,.T.);
#2214=ORIENTED_EDGE('',*,*,#2213,.F.);
#2215=EDGE_LOOP('',(#2214));
#2216=FACE_BOUND('',#2215,.T.);
#2217=ORIENTED_EDGE('',*,*,#2150,.T.);
#2218=EDGE_LOOP('',(#2217));
#2219=FACE_BOUND('',#2218,.T.);
#2220=ADVANCED_FACE('F853',(#2216,#2219),#2205,.F.);
#2221=CARTESIAN_POINT('',(18.161,-21.9436,-4.316000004));
#2222=DIRECTION('',(0.,0.,-1.));
#2223=DIRECTION('',(-1.,0.,0.));
#2224=AXIS2_PLACEMENT_3D('',#2221,#2222,#2223);
#2225=CONICAL_SURFACE('',#2224,1.1303,1.02974425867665);
#2226=CARTESIAN_POINT('',(18.161,-21.9436,-3.63684724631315));
#2227=VERTEX_POINT('',#2226);
#2228=VERTEX_LOOP('',#2227);
#2229=FACE_BOUND('',#2228,.T.);
#2230=ORIENTED_EDGE('',*,*,#2213,.T.);
#2231=EDGE_LOOP('',(#2230));
#2232=FACE_BOUND('',#2231,.T.);
#2233=ADVANCED_FACE('F849',(#2229,#2232),#2225,.F.);
#2234=CARTESIAN_POINT('',(0.127,22.098,-19.7104000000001));
#2235=DIRECTION('',(0.,1.,0.));
#2236=DIRECTION('',(0.,0.,1.));
#2237=AXIS2_PLACEMENT_3D('',#2234,#2235,#2236);
#2238=CYLINDRICAL_SURFACE('',#2237,1.28905);
#2239=ORIENTED_EDGE('',*,*,#2082,.T.);
#2240=EDGE_LOOP('',(#2239));
#2241=FACE_BOUND('',#2240,.T.);
#2242=ORIENTED_EDGE('',*,*,#1857,.F.);
#2243=EDGE_LOOP('',(#2242));
#2244=FACE_BOUND('',#2243,.T.);
#2245=ADVANCED_FACE('F845',(#2241,#2244),#2238,.F.);
#2246=CARTESIAN_POINT('',(0.127000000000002,22.098,-0.660400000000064));
#2247=DIRECTION('',(0.,1.,0.));
#2248=DIRECTION('',(0.,0.,1.));
#2249=AXIS2_PLACEMENT_3D('',#2246,#2247,#2248);
#2250=CYLINDRICAL_SURFACE('',#2249,1.28905);
#2251=ORIENTED_EDGE('',*,*,#2022,.T.);
#2252=EDGE_LOOP('',(#2251));
#2253=FACE_BOUND('',#2252,.T.);
#2254=CARTESIAN_POINT('',(0.127000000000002,13.843,-0.660400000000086));
#2255=DIRECTION('',(0.,1.,0.));
#2256=DIRECTION('',(0.,0.,1.));
#2257=AXIS2_PLACEMENT_3D('',#2254,#2255,#2256);
#2258=CIRCLE('',#2257,1.28905);
#2259=EDGE_CURVE('E761',#1118,#1153,#2258,.T.);
#2260=ORIENTED_EDGE('',*,*,#2259,.F.);
#2261=ORIENTED_EDGE('',*,*,#1119,.F.);
#2262=ORIENTED_EDGE('',*,*,#1885,.F.);
#2263=ORIENTED_EDGE('',*,*,#1162,.F.);
#2264=EDGE_LOOP('',(#2260,#2261,#2262,#2263));
#2265=FACE_BOUND('',#2264,.T.);
#2266=ADVANCED_FACE('F840',(#2253,#2265),#2250,.F.);
#2267=CARTESIAN_POINT('',(0.127000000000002,13.843,-0.660400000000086));
#2268=DIRECTION('',(0.,1.,0.));
#2269=DIRECTION('',(0.,0.,1.));
#2270=AXIS2_PLACEMENT_3D('',#2267,#2268,#2269);
#2271=CONICAL_SURFACE('',#2270,1.28905,1.02974425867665);
#2272=ORIENTED_EDGE('',*,*,#2259,.T.);
#2273=ORIENTED_EDGE('',*,*,#1154,.F.);
#2274=EDGE_LOOP('',(#2272,#2273));
#2275=FACE_BOUND('',#2274,.T.);
#2276=ADVANCED_FACE('F834',(#2275),#2271,.F.);
#2277=CARTESIAN_POINT('',(26.823,5.,6.5278));
#2278=DIRECTION('',(0.,0.,1.));
#2279=DIRECTION('',(1.,0.,0.));
#2280=AXIS2_PLACEMENT_3D('',#2277,#2278,#2279);
#2281=CYLINDRICAL_SURFACE('',#2280,1.54999999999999);
#2282=ORIENTED_EDGE('',*,*,#443,.T.);
#2283=EDGE_LOOP('',(#2282));
#2284=FACE_BOUND('',#2283,.T.);
#2285=ORIENTED_EDGE('',*,*,#1249,.F.);
#2286=EDGE_LOOP('',(#2285));
#2287=FACE_BOUND('',#2286,.T.);
#2288=ADVANCED_FACE('F839',(#2284,#2287),#2281,.F.);
#2289=CARTESIAN_POINT('',(1.82299999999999,-5.,6.5278));
#2290=DIRECTION('',(0.,0.,1.));
#2291=DIRECTION('',(1.,0.,0.));
#2292=AXIS2_PLACEMENT_3D('',#2289,#2290,#2291);
#2293=CYLINDRICAL_SURFACE('',#2292,1.54999999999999);
#2294=ORIENTED_EDGE('',*,*,#454,.T.);
#2295=EDGE_LOOP('',(#2294));
#2296=FACE_BOUND('',#2295,.T.);
#2297=ORIENTED_EDGE('',*,*,#1260,.F.);
#2298=EDGE_LOOP('',(#2297));
#2299=FACE_BOUND('',#2298,.T.);
#2300=ADVANCED_FACE('F1157',(#2296,#2299),#2293,.F.);
#2301=CARTESIAN_POINT('',(1.82299999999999,5.,6.5278));
#2302=DIRECTION('',(0.,0.,1.));
#2303=DIRECTION('',(1.,0.,0.));
#2304=AXIS2_PLACEMENT_3D('',#2301,#2302,#2303);
#2305=CYLINDRICAL_SURFACE('',#2304,1.54999999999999);
#2306=ORIENTED_EDGE('',*,*,#465,.T.);
#2307=EDGE_LOOP('',(#2306));
#2308=FACE_BOUND('',#2307,.T.);
#2309=ORIENTED_EDGE('',*,*,#1271,.F.);
#2310=EDGE_LOOP('',(#2309));
#2311=FACE_BOUND('',#2310,.T.);
#2312=ADVANCED_FACE('F1154',(#2308,#2311),#2305,.F.);
#2313=CARTESIAN_POINT('',(26.823,-5.,6.5278));
#2314=DIRECTION('',(0.,0.,1.));
#2315=DIRECTION('',(1.,0.,0.));
#2316=AXIS2_PLACEMENT_3D('',#2313,#2314,#2315);
#2317=CYLINDRICAL_SURFACE('',#2316,1.54999999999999);
#2318=ORIENTED_EDGE('',*,*,#476,.T.);
#2319=EDGE_LOOP('',(#2318));
#2320=FACE_BOUND('',#2319,.T.);
#2321=ORIENTED_EDGE('',*,*,#1282,.F.);
#2322=EDGE_LOOP('',(#2321));
#2323=FACE_BOUND('',#2322,.T.);
#2324=ADVANCED_FACE('F1150',(#2320,#2323),#2317,.F.);
#2325=CARTESIAN_POINT('',(-19.1232329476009,5.96899994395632,6.5278));
#2326=DIRECTION('',(0.,0.,1.));
#2327=DIRECTION('',(1.,0.,0.));
#2328=AXIS2_PLACEMENT_3D('',#2325,#2326,#2327);
#2329=CYLINDRICAL_SURFACE('',#2328,1.13029999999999);
#2330=ORIENTED_EDGE('',*,*,#487,.T.);
#2331=EDGE_LOOP('',(#2330));
#2332=FACE_BOUND('',#2331,.T.);
#2333=ORIENTED_EDGE('',*,*,#1293,.F.);
#2334=EDGE_LOOP('',(#2333));
#2335=FACE_BOUND('',#2334,.T.);
#2336=ADVANCED_FACE('F1146',(#2332,#2335),#2329,.F.);
#2337=CARTESIAN_POINT('',(-19.1232329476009,-5.96900005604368,6.5278));
#2338=DIRECTION('',(0.,0.,1.));
#2339=DIRECTION('',(1.,0.,0.));
#2340=AXIS2_PLACEMENT_3D('',#2337,#2338,#2339);
#2341=CYLINDRICAL_SURFACE('',#2340,1.13029999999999);
#2342=ORIENTED_EDGE('',*,*,#498,.T.);
#2343=EDGE_LOOP('',(#2342));
#2344=FACE_BOUND('',#2343,.T.);
#2345=ORIENTED_EDGE('',*,*,#1304,.F.);
#2346=EDGE_LOOP('',(#2345));
#2347=FACE_BOUND('',#2346,.T.);
#2348=ADVANCED_FACE('F1141',(#2344,#2347),#2341,.F.);
#2349=ORIENTED_EDGE('',*,*,#688,.T.);
#2350=DIRECTION('',(0.,0.,1.));
#2351=VECTOR('',#2350,1.);
#2352=CARTESIAN_POINT('',(10.5197344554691,-12.66698,6.5278));
#2353=LINE('',#2352,#2351);
#2354=CARTESIAN_POINT('',(10.5197344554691,-12.66698,4.08305));
#2355=VERTEX_POINT('',#2354);
#2356=EDGE_CURVE('E608',#683,#2355,#2353,.F.);
#2357=ORIENTED_EDGE('',*,*,#2356,.T.);
#2358=DIRECTION('',(-1.,0.,0.));
#2359=VECTOR('',#2358,1.);
#2360=CARTESIAN_POINT('',(35.1814413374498,-12.66698,4.08305));
#2361=LINE('',#2360,#2359);
#2362=CARTESIAN_POINT('',(28.1331158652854,-12.66698,4.08305));
#2363=VERTEX_POINT('',#2362);
#2364=EDGE_CURVE('E564',#2363,#2355,#2361,.T.);
#2365=ORIENTED_EDGE('',*,*,#2364,.F.);
#2366=DIRECTION('',(0.,0.,1.));
#2367=VECTOR('',#2366,1.);
#2368=CARTESIAN_POINT('',(28.1331158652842,-12.66698,5.09905));
#2369=LINE('',#2368,#2367);
#2370=EDGE_CURVE('E1388',#2363,#687,#2369,.T.);
#2371=ORIENTED_EDGE('',*,*,#2370,.T.);
#2372=EDGE_LOOP('',(#2349,#2357,#2365,#2371));
#2373=FACE_BOUND('',#2372,.T.);
#2374=ADVANCED_FACE('F1131',(#2373),#919,.F.);
#2375=CARTESIAN_POINT('',(-21.971,-43.27398,6.5278));
#2376=DIRECTION('',(1.,0.,0.));
#2377=DIRECTION('',(0.,1.,0.));
#2378=AXIS2_PLACEMENT_3D('',#2375,#2376,#2377);
#2379=PLANE('',#2378);
#2380=ORIENTED_EDGE('',*,*,#609,.F.);
#2381=DIRECTION('',(0.,0.,-1.));
#2382=VECTOR('',#2381,1.);
#2383=CARTESIAN_POINT('',(-21.971,-13.7137314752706,6.5278));
#2384=LINE('',#2383,#2382);
#2385=EDGE_CURVE('E1223',#600,#1036,#2384,.T.);
#2386=ORIENTED_EDGE('',*,*,#2385,.T.);
#2387=ORIENTED_EDGE('',*,*,#1037,.T.);
#2388=DIRECTION('',(0.,0.,1.));
#2389=VECTOR('',#2388,1.);
#2390=CARTESIAN_POINT('',(-21.971,-28.5419799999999,6.5278));
#2391=LINE('',#2390,#2389);
#2392=EDGE_CURVE('E1187',#1028,#608,#2391,.T.);
#2393=ORIENTED_EDGE('',*,*,#2392,.T.);
#2394=EDGE_LOOP('',(#2380,#2386,#2387,#2393));
#2395=FACE_BOUND('',#2394,.T.);
#2396=ADVANCED_FACE('F1127',(#2395),#2379,.F.);
#2397=CARTESIAN_POINT('',(-21.971,24.13,6.5278));
#2398=DIRECTION('',(1.,0.,0.));
#2399=DIRECTION('',(0.,1.,0.));
#2400=AXIS2_PLACEMENT_3D('',#2397,#2398,#2399);
#2401=PLANE('',#2400);
#2402=ORIENTED_EDGE('',*,*,#575,.F.);
#2403=DIRECTION('',(0.,0.,-1.));
#2404=VECTOR('',#2403,1.);
#2405=CARTESIAN_POINT('',(-21.971,22.098,6.5278));
#2406=LINE('',#2405,#2404);
#2407=EDGE_CURVE('E1397',#566,#1070,#2406,.T.);
#2408=ORIENTED_EDGE('',*,*,#2407,.T.);
#2409=ORIENTED_EDGE('',*,*,#1071,.T.);
#2410=DIRECTION('',(0.,0.,1.));
#2411=VECTOR('',#2410,1.);
#2412=CARTESIAN_POINT('',(-21.971,13.7137313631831,6.5278));
#2413=LINE('',#2412,#2411);
#2414=EDGE_CURVE('E1212',#1062,#574,#2413,.T.);
#2415=ORIENTED_EDGE('',*,*,#2414,.T.);
#2416=EDGE_LOOP('',(#2402,#2408,#2409,#2415));
#2417=FACE_BOUND('',#2416,.T.);
#2418=ADVANCED_FACE('F1124',(#2417),#2401,.F.);
#2419=CARTESIAN_POINT('',(-7.23900000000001,-43.27398,6.5278));
#2420=DIRECTION('',(0.707106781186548,0.707106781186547,0.));
#2421=DIRECTION('',(-0.707106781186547,0.707106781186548,0.));
#2422=AXIS2_PLACEMENT_3D('',#2419,#2420,#2421);
#2423=PLANE('',#2422);
#2424=DIRECTION('',(0.707106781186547,-0.707106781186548,0.));
#2425=VECTOR('',#2424,1.);
#2426=CARTESIAN_POINT('',(-7.23900000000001,-43.27398,3.19405));
#2427=LINE('',#2426,#2425);
#2428=CARTESIAN_POINT('',(-15.8927435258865,-34.6202364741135,3.19405));
#2429=VERTEX_POINT('',#2428);
#2430=EDGE_CURVE('E1195',#1694,#2429,#2427,.F.);
#2431=ORIENTED_EDGE('',*,*,#2430,.F.);
#2432=ORIENTED_EDGE('',*,*,#1695,.F.);
#2433=ORIENTED_EDGE('',*,*,#104,.T.);
#2434=ORIENTED_EDGE('',*,*,#615,.F.);
#2435=ORIENTED_EDGE('',*,*,#2392,.F.);
#2436=ORIENTED_EDGE('',*,*,#1029,.F.);
#2437=DIRECTION('',(0.,0.,1.));
#2438=VECTOR('',#2437,1.);
#2439=CARTESIAN_POINT('',(-15.8927435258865,-34.6202364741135,6.5278));
#2440=LINE('',#2439,#2438);
#2441=EDGE_CURVE('E1193',#2429,#1020,#2440,.F.);
#2442=ORIENTED_EDGE('',*,*,#2441,.F.);
#2443=EDGE_LOOP('',(#2431,#2432,#2433,#2434,#2435,#2436,#2442));
#2444=FACE_BOUND('',#2443,.T.);
#2445=ADVANCED_FACE('F1122',(#2444),#2423,.F.);
#2446=CARTESIAN_POINT('',(-4.69900000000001,-15.20698,3.19405));
#2447=DIRECTION('',(0.,0.,1.));
#2448=DIRECTION('',(1.,0.,0.));
#2449=AXIS2_PLACEMENT_3D('',#2446,#2447,#2448);
#2450=PLANE('',#2449);
#2451=CARTESIAN_POINT('',(7.77,-41.49598,3.19405));
#2452=DIRECTION('',(0.,0.,1.));
#2453=DIRECTION('',(1.,0.,0.));
#2454=AXIS2_PLACEMENT_3D('',#2451,#2452,#2453);
#2455=CIRCLE('',#2454,1.190625);
#2456=CARTESIAN_POINT('',(8.960625,-41.49598,3.19405));
#2457=VERTEX_POINT('',#2456);
#2458=EDGE_CURVE('E554',#2457,#2457,#2455,.T.);
#2459=ORIENTED_EDGE('',*,*,#2458,.T.);
#2460=EDGE_LOOP('',(#2459));
#2461=FACE_BOUND('',#2460,.T.);
#2462=CARTESIAN_POINT('',(-5.23000000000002,-41.49598,3.19405));
#2463=DIRECTION('',(0.,0.,1.));
#2464=DIRECTION('',(1.,0.,0.));
#2465=AXIS2_PLACEMENT_3D('',#2462,#2463,#2464);
#2466=CIRCLE('',#2465,1.190625);
#2467=CARTESIAN_POINT('',(-4.03937500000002,-41.49598,3.19405));
#2468=VERTEX_POINT('',#2467);
#2469=EDGE_CURVE('E558',#2468,#2468,#2466,.T.);
#2470=ORIENTED_EDGE('',*,*,#2469,.T.);
#2471=EDGE_LOOP('',(#2470));
#2472=FACE_BOUND('',#2471,.T.);
#2473=CARTESIAN_POINT('',(1.27,-38.70198,3.19405));
#2474=DIRECTION('',(0.,0.,1.));
#2475=DIRECTION('',(1.,0.,0.));
#2476=AXIS2_PLACEMENT_3D('',#2473,#2474,#2475);
#2477=CIRCLE('',#2476,2.38124999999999);
#2478=CARTESIAN_POINT('',(3.65125,-38.70198,3.19405));
#2479=VERTEX_POINT('',#2478);
#2480=EDGE_CURVE('E621',#2479,#2479,#2477,.T.);
#2481=ORIENTED_EDGE('',*,*,#2480,.T.);
#2482=EDGE_LOOP('',(#2481));
#2483=FACE_BOUND('',#2482,.T.);
#2484=CARTESIAN_POINT('',(7.49299999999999,-37.68598,3.19405));
#2485=DIRECTION('',(0.,0.,1.));
#2486=DIRECTION('',(1.,0.,0.));
#2487=AXIS2_PLACEMENT_3D('',#2484,#2485,#2486);
#2488=CIRCLE('',#2487,0.888999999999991);
#2489=CARTESIAN_POINT('',(8.38199999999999,-37.68598,3.19405));
#2490=VERTEX_POINT('',#2489);
#2491=EDGE_CURVE('E696',#2490,#2490,#2488,.T.);
#2492=ORIENTED_EDGE('',*,*,#2491,.T.);
#2493=EDGE_LOOP('',(#2492));
#2494=FACE_BOUND('',#2493,.T.);
#2495=ORIENTED_EDGE('',*,*,#2430,.T.);
#2496=DIRECTION('',(1.,0.,0.));
#2497=VECTOR('',#2496,1.);
#2498=CARTESIAN_POINT('',(9.77899999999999,-34.6202364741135,3.19405));
#2499=LINE('',#2498,#2497);
#2500=EDGE_CURVE('E706',#2429,#1454,#2499,.T.);
#2501=ORIENTED_EDGE('',*,*,#2500,.T.);
#2502=ORIENTED_EDGE('',*,*,#1455,.T.);
#2503=ORIENTED_EDGE('',*,*,#1701,.T.);
#2504=EDGE_LOOP('',(#2495,#2501,#2502,#2503));
#2505=FACE_BOUND('',#2504,.T.);
#2506=ADVANCED_FACE('F1118',(#2461,#2472,#2483,#2494,#2505),#2450,.F.);
#2507=CARTESIAN_POINT('',(9.77899999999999,-34.6202364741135,38.6422522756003));
#2508=DIRECTION('',(0.,1.,0.));
#2509=DIRECTION('',(0.,0.,1.));
#2510=AXIS2_PLACEMENT_3D('',#2507,#2508,#2509);
#2511=PLANE('',#2510);
#2512=ORIENTED_EDGE('',*,*,#2441,.T.);
#2513=ORIENTED_EDGE('',*,*,#1021,.T.);
#2514=ORIENTED_EDGE('',*,*,#1461,.F.);
#2515=ORIENTED_EDGE('',*,*,#2500,.F.);
#2516=EDGE_LOOP('',(#2512,#2513,#2514,#2515));
#2517=FACE_BOUND('',#2516,.T.);
#2518=ADVANCED_FACE('F1114',(#2517),#2511,.F.);
#2519=CARTESIAN_POINT('',(7.493,-18.25498,5.73405));
#2520=DIRECTION('',(0.,0.,1.));
#2521=DIRECTION('',(1.,0.,0.));
#2522=AXIS2_PLACEMENT_3D('',#2519,#2520,#2521);
#2523=CYLINDRICAL_SURFACE('',#2522,0.888999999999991);
#2524=ORIENTED_EDGE('',*,*,#1387,.T.);
#2525=EDGE_LOOP('',(#2524));
#2526=FACE_BOUND('',#2525,.T.);
#2527=ORIENTED_EDGE('',*,*,#1315,.F.);
#2528=EDGE_LOOP('',(#2527));
#2529=FACE_BOUND('',#2528,.T.);
#2530=ADVANCED_FACE('F1110',(#2526,#2529),#2523,.F.);
#2531=CARTESIAN_POINT('',(7.49299999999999,-37.68598,5.73405));
#2532=DIRECTION('',(0.,0.,1.));
#2533=DIRECTION('',(1.,0.,0.));
#2534=AXIS2_PLACEMENT_3D('',#2531,#2532,#2533);
#2535=CYLINDRICAL_SURFACE('',#2534,0.888999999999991);
#2536=ORIENTED_EDGE('',*,*,#1410,.T.);
#2537=EDGE_LOOP('',(#2536));
#2538=FACE_BOUND('',#2537,.T.);
#2539=ORIENTED_EDGE('',*,*,#2491,.F.);
#2540=EDGE_LOOP('',(#2539));
#2541=FACE_BOUND('',#2540,.T.);
#2542=ADVANCED_FACE('F1107',(#2538,#2541),#2535,.F.);
#2543=CARTESIAN_POINT('',(30.48,-43.27398,6.5278));
#2544=DIRECTION('',(0.707106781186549,0.,0.707106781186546));
#2545=DIRECTION('',(0.707106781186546,0.,-0.707106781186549));
#2546=AXIS2_PLACEMENT_3D('',#2543,#2544,#2545);
#2547=PLANE('',#2546);
#2548=ORIENTED_EDGE('',*,*,#1724,.F.);
#2549=ORIENTED_EDGE('',*,*,#1626,.F.);
#2550=ORIENTED_EDGE('',*,*,#1839,.F.);
#2551=ORIENTED_EDGE('',*,*,#713,.F.);
#2552=EDGE_LOOP('',(#2548,#2549,#2550,#2551));
#2553=FACE_BOUND('',#2552,.T.);
#2554=ADVANCED_FACE('F1094',(#2553),#2547,.T.);
#2555=CARTESIAN_POINT('',(7.493,-18.25498,5.09905));
#2556=DIRECTION('',(0.,0.,1.));
#2557=DIRECTION('',(1.,0.,0.));
#2558=AXIS2_PLACEMENT_3D('',#2555,#2556,#2557);
#2559=CYLINDRICAL_SURFACE('',#2558,2.032);
#2560=ORIENTED_EDGE('',*,*,#1398,.F.);
#2561=EDGE_LOOP('',(#2560));
#2562=FACE_BOUND('',#2561,.T.);
#2563=ORIENTED_EDGE('',*,*,#267,.T.);
#2564=EDGE_LOOP('',(#2563));
#2565=FACE_BOUND('',#2564,.T.);
#2566=ADVANCED_FACE('F1090',(#2562,#2565),#2559,.T.);
#2567=CARTESIAN_POINT('',(7.49299999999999,-37.68598,5.09905));
#2568=DIRECTION('',(0.,0.,1.));
#2569=DIRECTION('',(1.,0.,0.));
#2570=AXIS2_PLACEMENT_3D('',#2567,#2568,#2569);
#2571=CYLINDRICAL_SURFACE('',#2570,2.03199999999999);
#2572=ORIENTED_EDGE('',*,*,#1421,.F.);
#2573=EDGE_LOOP('',(#2572));
#2574=FACE_BOUND('',#2573,.T.);
#2575=ORIENTED_EDGE('',*,*,#239,.T.);
#2576=EDGE_LOOP('',(#2575));
#2577=FACE_BOUND('',#2576,.T.);
#2578=ADVANCED_FACE('F1086',(#2574,#2577),#2571,.T.);
#2579=CARTESIAN_POINT('',(-25.527,13.7137313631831,6.5278));
#2580=DIRECTION('',(0.,0.,1.));
#2581=DIRECTION('',(1.,0.,0.));
#2582=AXIS2_PLACEMENT_3D('',#2579,#2580,#2581);
#2583=CYLINDRICAL_SURFACE('',#2582,3.556);
#2584=ORIENTED_EDGE('',*,*,#584,.F.);
#2585=ORIENTED_EDGE('',*,*,#2414,.F.);
#2586=ORIENTED_EDGE('',*,*,#1063,.F.);
#2587=ORIENTED_EDGE('',*,*,#1670,.F.);
#2588=EDGE_LOOP('',(#2584,#2585,#2586,#2587));
#2589=FACE_BOUND('',#2588,.T.);
#2590=ADVANCED_FACE('F1089',(#2589),#2583,.F.);
#2591=CARTESIAN_POINT('',(-25.527,-13.7137314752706,6.5278));
#2592=DIRECTION('',(0.,0.,-1.));
#2593=DIRECTION('',(-1.,0.,0.));
#2594=AXIS2_PLACEMENT_3D('',#2591,#2592,#2593);
#2595=CYLINDRICAL_SURFACE('',#2594,3.556);
#2596=ORIENTED_EDGE('',*,*,#601,.F.);
#2597=ORIENTED_EDGE('',*,*,#1677,.T.);
#2598=ORIENTED_EDGE('',*,*,#1046,.F.);
#2599=ORIENTED_EDGE('',*,*,#2385,.F.);
#2600=EDGE_LOOP('',(#2596,#2597,#2598,#2599));
#2601=FACE_BOUND('',#2600,.T.);
#2602=ADVANCED_FACE('F1514',(#2601),#2595,.F.);
#2603=CARTESIAN_POINT('',(6.858,16.056,6.5278));
#2604=DIRECTION('',(0.,0.,-1.));
#2605=DIRECTION('',(-1.,0.,0.));
#2606=AXIS2_PLACEMENT_3D('',#2603,#2604,#2605);
#2607=CYLINDRICAL_SURFACE('',#2606,3.556);
#2608=ORIENTED_EDGE('',*,*,#957,.F.);
#2609=ORIENTED_EDGE('',*,*,#1781,.F.);
#2610=ORIENTED_EDGE('',*,*,#730,.F.);
#2611=ORIENTED_EDGE('',*,*,#1832,.F.);
#2612=EDGE_LOOP('',(#2608,#2609,#2610,#2611));
#2613=FACE_BOUND('',#2612,.T.);
#2614=ADVANCED_FACE('F1340',(#2613),#2607,.F.);
#2615=CARTESIAN_POINT('',(29.21,-16.056,6.5278));
#2616=DIRECTION('',(0.,0.,1.));
#2617=DIRECTION('',(1.,0.,0.));
#2618=AXIS2_PLACEMENT_3D('',#2615,#2616,#2617);
#2619=CYLINDRICAL_SURFACE('',#2618,3.556);
#2620=ORIENTED_EDGE('',*,*,#2370,.F.);
#2621=CARTESIAN_POINT('',(29.21,-16.056,4.08305));
#2622=DIRECTION('',(0.,0.,1.));
#2623=DIRECTION('',(1.,0.,0.));
#2624=AXIS2_PLACEMENT_3D('',#2621,#2622,#2623);
#2625=CIRCLE('',#2624,3.556);
#2626=EDGE_CURVE('E579',#829,#2363,#2625,.F.);
#2627=ORIENTED_EDGE('',*,*,#2626,.F.);
#2628=ORIENTED_EDGE('',*,*,#877,.F.);
#2629=ORIENTED_EDGE('',*,*,#988,.F.);
#2630=ORIENTED_EDGE('',*,*,#1716,.F.);
#2631=ORIENTED_EDGE('',*,*,#697,.F.);
#2632=EDGE_LOOP('',(#2620,#2627,#2628,#2629,#2630,#2631));
#2633=FACE_BOUND('',#2632,.T.);
#2634=ADVANCED_FACE('F1385',(#2633),#2619,.F.);
#2635=CARTESIAN_POINT('',(-21.971,22.098,6.5278));
#2636=DIRECTION('',(0.707106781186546,-0.707106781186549,0.));
#2637=DIRECTION('',(0.707106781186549,0.707106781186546,0.));
#2638=AXIS2_PLACEMENT_3D('',#2635,#2636,#2637);
#2639=PLANE('',#2638);
#2640=ORIENTED_EDGE('',*,*,#567,.F.);
#2641=ORIENTED_EDGE('',*,*,#1655,.F.);
#2642=ORIENTED_EDGE('',*,*,#1079,.F.);
#2643=ORIENTED_EDGE('',*,*,#2407,.F.);
#2644=EDGE_LOOP('',(#2640,#2641,#2642,#2643));
#2645=FACE_BOUND('',#2644,.T.);
#2646=ADVANCED_FACE('F36',(#2645),#2639,.F.);
#2647=CARTESIAN_POINT('',(14.323,0.,0.));
#2648=DIRECTION('',(0.,0.,-1.));
#2649=DIRECTION('',(-1.,0.,0.));
#2650=AXIS2_PLACEMENT_3D('',#2647,#2648,#2649);
#2651=CYLINDRICAL_SURFACE('',#2650,9.128125);
#2652=ORIENTED_EDGE('',*,*,#509,.F.);
#2653=EDGE_LOOP('',(#2652));
#2654=FACE_BOUND('',#2653,.T.);
#2655=ORIENTED_EDGE('',*,*,#1326,.T.);
#2656=EDGE_LOOP('',(#2655));
#2657=FACE_BOUND('',#2656,.T.);
#2658=ADVANCED_FACE('F1077',(#2654,#2657),#2651,.F.);
#2659=CARTESIAN_POINT('',(-9.398,0.,6.5278));
#2660=DIRECTION('',(0.,0.,1.));
#2661=DIRECTION('',(1.,0.,0.));
#2662=AXIS2_PLACEMENT_3D('',#2659,#2660,#2661);
#2663=CYLINDRICAL_SURFACE('',#2662,7.54062499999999);
#2664=ORIENTED_EDGE('',*,*,#432,.T.);
#2665=EDGE_LOOP('',(#2664));
#2666=FACE_BOUND('',#2665,.T.);
#2667=ORIENTED_EDGE('',*,*,#1337,.F.);
#2668=EDGE_LOOP('',(#2667));
#2669=FACE_BOUND('',#2668,.T.);
#2670=ADVANCED_FACE('F1073',(#2666,#2669),#2663,.F.);
#2671=CARTESIAN_POINT('',(-6.858,-14.82598,0.));
#2672=DIRECTION('',(0.,0.,-1.));
#2673=DIRECTION('',(-1.,0.,0.));
#2674=AXIS2_PLACEMENT_3D('',#2671,#2672,#2673);
#2675=CYLINDRICAL_SURFACE('',#2674,4.365625);
#2676=ORIENTED_EDGE('',*,*,#1348,.T.);
#2677=EDGE_LOOP('',(#2676));
#2678=FACE_BOUND('',#2677,.T.);
#2679=ORIENTED_EDGE('',*,*,#667,.F.);
#2680=ORIENTED_EDGE('',*,*,#135,.F.);
#2681=ORIENTED_EDGE('',*,*,#307,.F.);
#2682=ORIENTED_EDGE('',*,*,#932,.F.);
#2683=EDGE_LOOP('',(#2679,#2680,#2681,#2682));
#2684=FACE_BOUND('',#2683,.T.);
#2685=ADVANCED_FACE('F1069',(#2678,#2684),#2675,.F.);
#2686=CARTESIAN_POINT('',(-13.462,-28.03398,0.));
#2687=DIRECTION('',(0.,0.,-1.));
#2688=DIRECTION('',(-1.,0.,0.));
#2689=AXIS2_PLACEMENT_3D('',#2686,#2687,#2688);
#2690=CYLINDRICAL_SURFACE('',#2689,3.96875);
#2691=ORIENTED_EDGE('',*,*,#421,.F.);
#2692=EDGE_LOOP('',(#2691));
#2693=FACE_BOUND('',#2692,.T.);
#2694=ORIENTED_EDGE('',*,*,#1359,.T.);
#2695=EDGE_LOOP('',(#2694));
#2696=FACE_BOUND('',#2695,.T.);
#2697=ADVANCED_FACE('F1065',(#2693,#2696),#2690,.F.);
#2698=CARTESIAN_POINT('',(-3.302,10.795,0.));
#2699=DIRECTION('',(0.,0.,-1.));
#2700=DIRECTION('',(-1.,0.,0.));
#2701=AXIS2_PLACEMENT_3D('',#2698,#2699,#2700);
#2702=CYLINDRICAL_SURFACE('',#2701,3.175);
#2703=ORIENTED_EDGE('',*,*,#410,.F.);
#2704=EDGE_LOOP('',(#2703));
#2705=FACE_BOUND('',#2704,.T.);
#2706=ORIENTED_EDGE('',*,*,#1370,.T.);
#2707=EDGE_LOOP('',(#2706));
#2708=FACE_BOUND('',#2707,.T.);
#2709=ADVANCED_FACE('F1061',(#2705,#2708),#2702,.F.);
#2710=CARTESIAN_POINT('',(-15.748,10.795,0.));
#2711=DIRECTION('',(0.,0.,-1.));
#2712=DIRECTION('',(-1.,0.,0.));
#2713=AXIS2_PLACEMENT_3D('',#2710,#2711,#2712);
#2714=CYLINDRICAL_SURFACE('',#2713,3.175);
#2715=ORIENTED_EDGE('',*,*,#399,.F.);
#2716=EDGE_LOOP('',(#2715));
#2717=FACE_BOUND('',#2716,.T.);
#2718=ORIENTED_EDGE('',*,*,#1227,.T.);
#2719=EDGE_LOOP('',(#2718));
#2720=FACE_BOUND('',#2719,.T.);
#2721=ADVANCED_FACE('F1057',(#2717,#2720),#2714,.F.);
#2722=CARTESIAN_POINT('',(-21.336,0.,6.5278));
#2723=DIRECTION('',(0.,0.,1.));
#2724=DIRECTION('',(1.,0.,0.));
#2725=AXIS2_PLACEMENT_3D('',#2722,#2723,#2724);
#2726=CYLINDRICAL_SURFACE('',#2725,2.38124999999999);
#2727=ORIENTED_EDGE('',*,*,#520,.T.);
#2728=EDGE_LOOP('',(#2727));
#2729=FACE_BOUND('',#2728,.T.);
#2730=ORIENTED_EDGE('',*,*,#1216,.F.);
#2731=EDGE_LOOP('',(#2730));
#2732=FACE_BOUND('',#2731,.T.);
#2733=ADVANCED_FACE('F1053',(#2729,#2732),#2726,.F.);
#2734=CARTESIAN_POINT('',(1.27,-38.70198,6.5278));
#2735=DIRECTION('',(0.,0.,1.));
#2736=DIRECTION('',(1.,0.,0.));
#2737=AXIS2_PLACEMENT_3D('',#2734,#2735,#2736);
#2738=CYLINDRICAL_SURFACE('',#2737,2.38124999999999);
#2739=ORIENTED_EDGE('',*,*,#154,.F.);
#2740=EDGE_LOOP('',(#2739));
#2741=FACE_BOUND('',#2740,.T.);
#2742=ORIENTED_EDGE('',*,*,#2480,.F.);
#2743=EDGE_LOOP('',(#2742));
#2744=FACE_BOUND('',#2743,.T.);
#2745=ADVANCED_FACE('F1049',(#2741,#2744),#2738,.F.);
#2746=CARTESIAN_POINT('',(-16.256,-10.50798,6.5278));
#2747=DIRECTION('',(0.,0.,1.));
#2748=DIRECTION('',(1.,0.,0.));
#2749=AXIS2_PLACEMENT_3D('',#2746,#2747,#2748);
#2750=CYLINDRICAL_SURFACE('',#2749,2.38124999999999);
#2751=ORIENTED_EDGE('',*,*,#531,.T.);
#2752=EDGE_LOOP('',(#2751));
#2753=FACE_BOUND('',#2752,.T.);
#2754=ORIENTED_EDGE('',*,*,#1205,.F.);
#2755=EDGE_LOOP('',(#2754));
#2756=FACE_BOUND('',#2755,.T.);
#2757=ADVANCED_FACE('F1045',(#2753,#2756),#2750,.F.);
#2758=CARTESIAN_POINT('',(1.27,-17.36598,6.5278));
#2759=DIRECTION('',(0.,0.,1.));
#2760=DIRECTION('',(1.,0.,0.));
#2761=AXIS2_PLACEMENT_3D('',#2758,#2759,#2760);
#2762=CYLINDRICAL_SURFACE('',#2761,2.38124999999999);
#2763=ORIENTED_EDGE('',*,*,#1194,.F.);
#2764=EDGE_LOOP('',(#2763));
#2765=FACE_BOUND('',#2764,.T.);
#2766=ORIENTED_EDGE('',*,*,#165,.F.);
#2767=EDGE_LOOP('',(#2766));
#2768=FACE_BOUND('',#2767,.T.);
#2769=ADVANCED_FACE('F1041',(#2765,#2768),#2762,.F.);
#2770=CARTESIAN_POINT('',(8.382,-13.716,6.5278));
#2771=DIRECTION('',(0.,0.,1.));
#2772=DIRECTION('',(1.,0.,0.));
#2773=AXIS2_PLACEMENT_3D('',#2770,#2771,#2772);
#2774=CYLINDRICAL_SURFACE('',#2773,2.38124999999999);
#2775=ORIENTED_EDGE('',*,*,#292,.F.);
#2776=ORIENTED_EDGE('',*,*,#371,.T.);
#2777=CARTESIAN_POINT('',(8.382,-13.716,4.08305));
#2778=DIRECTION('',(0.,0.,1.));
#2779=DIRECTION('',(1.,0.,0.));
#2780=AXIS2_PLACEMENT_3D('',#2777,#2778,#2779);
#2781=CIRCLE('',#2780,2.38124999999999);
#2782=EDGE_CURVE('E571',#2355,#364,#2781,.F.);
#2783=ORIENTED_EDGE('',*,*,#2782,.F.);
#2784=ORIENTED_EDGE('',*,*,#2356,.F.);
#2785=ORIENTED_EDGE('',*,*,#684,.T.);
#2786=ORIENTED_EDGE('',*,*,#925,.F.);
#2787=EDGE_LOOP('',(#2775,#2776,#2783,#2784,#2785,#2786));
#2788=FACE_BOUND('',#2787,.T.);
#2789=ORIENTED_EDGE('',*,*,#1183,.F.);
#2790=EDGE_LOOP('',(#2789));
#2791=FACE_BOUND('',#2790,.T.);
#2792=ADVANCED_FACE('F1037',(#2788,#2791),#2774,.F.);
#2793=CARTESIAN_POINT('',(-11.43,-7.50040104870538,-22.6314000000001));
#2794=DIRECTION('',(-1.,0.,0.));
#2795=DIRECTION('',(0.,0.,1.));
#2796=AXIS2_PLACEMENT_3D('',#2793,#2794,#2795);
#2797=PLANE('',#2796);
#2798=ORIENTED_EDGE('',*,*,#1648,.T.);
#2799=ORIENTED_EDGE('',*,*,#551,.F.);
#2800=ORIENTED_EDGE('',*,*,#2069,.F.);
#2801=ORIENTED_EDGE('',*,*,#1095,.F.);
#2802=EDGE_LOOP('',(#2798,#2799,#2800,#2801));
#2803=FACE_BOUND('',#2802,.T.);
#2804=ADVANCED_FACE('F1025',(#2803),#2797,.F.);
#2805=CARTESIAN_POINT('',(35.1814413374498,-12.66698,4.08305));
#2806=DIRECTION('',(0.,0.,1.));
#2807=DIRECTION('',(1.,0.,0.));
#2808=AXIS2_PLACEMENT_3D('',#2805,#2806,#2807);
#2809=PLANE('',#2808);
#2810=CARTESIAN_POINT('',(22.86,-22.098,4.08305));
#2811=DIRECTION('',(0.,0.,1.));
#2812=DIRECTION('',(1.,0.,0.));
#2813=AXIS2_PLACEMENT_3D('',#2810,#2811,#2812);
#2814=CIRCLE('',#2813,2.032);
#2815=CARTESIAN_POINT('',(24.892,-22.098,4.08305));
#2816=VERTEX_POINT('',#2815);
#2817=EDGE_CURVE('E561',#2816,#2816,#2814,.T.);
#2818=ORIENTED_EDGE('',*,*,#2817,.F.);
#2819=EDGE_LOOP('',(#2818));
#2820=FACE_BOUND('',#2819,.T.);
#2821=CARTESIAN_POINT('',(19.304,-15.58798,4.08305));
#2822=DIRECTION('',(0.,0.,1.));
#2823=DIRECTION('',(1.,0.,0.));
#2824=AXIS2_PLACEMENT_3D('',#2821,#2822,#2823);
#2825=CIRCLE('',#2824,2.38124999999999);
#2826=CARTESIAN_POINT('',(21.68525,-15.58798,4.08305));
#2827=VERTEX_POINT('',#2826);
#2828=EDGE_CURVE('E570',#2827,#2827,#2825,.F.);
#2829=ORIENTED_EDGE('',*,*,#2828,.T.);
#2830=EDGE_LOOP('',(#2829));
#2831=FACE_BOUND('',#2830,.T.);
#2832=ORIENTED_EDGE('',*,*,#2626,.T.);
#2833=ORIENTED_EDGE('',*,*,#2364,.T.);
#2834=ORIENTED_EDGE('',*,*,#2782,.T.);
#2835=ORIENTED_EDGE('',*,*,#365,.T.);
#2836=DIRECTION('',(1.,0.,0.));
#2837=VECTOR('',#2836,1.);
#2838=CARTESIAN_POINT('',(9.27099999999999,-19.8774036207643,4.08305));
#2839=LINE('',#2838,#2837);
#2840=CARTESIAN_POINT('',(9.27099999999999,-19.8774036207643,4.08305));
#2841=VERTEX_POINT('',#2840);
#2842=EDGE_CURVE('E513',#2841,#356,#2839,.T.);
#2843=ORIENTED_EDGE('',*,*,#2842,.F.);
#2844=CARTESIAN_POINT('',(9.27099999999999,-21.9094036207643,4.08305));
#2845=DIRECTION('',(0.,0.,1.));
#2846=DIRECTION('',(1.,0.,0.));
#2847=AXIS2_PLACEMENT_3D('',#2844,#2845,#2846);
#2848=CIRCLE('',#2847,2.032);
#2849=CARTESIAN_POINT('',(7.239,-21.9094036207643,4.08305));
#2850=VERTEX_POINT('',#2849);
#2851=EDGE_CURVE('E501',#2850,#2841,#2848,.F.);
#2852=ORIENTED_EDGE('',*,*,#2851,.F.);
#2853=DIRECTION('',(0.,1.,0.));
#2854=VECTOR('',#2853,1.);
#2855=CARTESIAN_POINT('',(7.239,-34.0315563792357,4.08305));
#2856=LINE('',#2855,#2854);
#2857=CARTESIAN_POINT('',(7.239,-34.0315563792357,4.08305));
#2858=VERTEX_POINT('',#2857);
#2859=EDGE_CURVE('E503',#2858,#2850,#2856,.T.);
#2860=ORIENTED_EDGE('',*,*,#2859,.F.);
#2861=CARTESIAN_POINT('',(9.27099999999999,-34.0315563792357,4.08305));
#2862=DIRECTION('',(0.,0.,1.));
#2863=DIRECTION('',(1.,0.,0.));
#2864=AXIS2_PLACEMENT_3D('',#2861,#2862,#2863);
#2865=CIRCLE('',#2864,2.032);
#2866=CARTESIAN_POINT('',(9.27099999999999,-36.0635563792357,4.08305));
#2867=VERTEX_POINT('',#2866);
#2868=EDGE_CURVE('E506',#2867,#2858,#2865,.F.);
#2869=ORIENTED_EDGE('',*,*,#2868,.F.);
#2870=DIRECTION('',(-1.,0.,0.));
#2871=VECTOR('',#2870,1.);
#2872=CARTESIAN_POINT('',(9.27099999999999,-36.0635563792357,4.08305));
#2873=LINE('',#2872,#2871);
#2874=EDGE_CURVE('E508',#1431,#2867,#2873,.T.);
#2875=ORIENTED_EDGE('',*,*,#2874,.F.);
#2876=ORIENTED_EDGE('',*,*,#1432,.F.);
#2877=ORIENTED_EDGE('',*,*,#894,.T.);
#2878=ORIENTED_EDGE('',*,*,#776,.T.);
#2879=ORIENTED_EDGE('',*,*,#830,.T.);
#2880=EDGE_LOOP('',(#2832,#2833,#2834,#2835,#2843,#2852,#2860,#2869,#2875,#2876,#2877,#2878,#2879));
#2881=FACE_BOUND('',#2880,.T.);
#2882=ADVANCED_FACE('F1021',(#2820,#2831,#2881),#2809,.T.);
#2883=CARTESIAN_POINT('',(22.86,-22.098,-2.74193));
#2884=DIRECTION('',(0.,0.,1.));
#2885=DIRECTION('',(1.,0.,0.));
#2886=AXIS2_PLACEMENT_3D('',#2883,#2884,#2885);
#2887=CONICAL_SURFACE('',#2886,0.888999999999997,1.02974425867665);
#2888=CARTESIAN_POINT('',(22.86,-22.098,-3.2760950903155));
#2889=VERTEX_POINT('',#2888);
#2890=VERTEX_LOOP('',#2889);
#2891=FACE_BOUND('',#2890,.T.);
#2892=CARTESIAN_POINT('',(22.86,-22.098,-2.74193));
#2893=DIRECTION('',(0.,0.,1.));
#2894=DIRECTION('',(1.,0.,0.));
#2895=AXIS2_PLACEMENT_3D('',#2892,#2893,#2894);
#2896=CIRCLE('',#2895,0.888999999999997);
#2897=CARTESIAN_POINT('',(23.749,-22.098,-2.74193));
#2898=VERTEX_POINT('',#2897);
#2899=EDGE_CURVE('E686',#2898,#2898,#2896,.T.);
#2900=ORIENTED_EDGE('',*,*,#2899,.T.);
#2901=EDGE_LOOP('',(#2900));
#2902=FACE_BOUND('',#2901,.T.);
#2903=ADVANCED_FACE('F1024',(#2891,#2902),#2887,.F.);
#2904=CARTESIAN_POINT('',(22.86,-22.098,5.73405));
#2905=DIRECTION('',(0.,0.,1.));
#2906=DIRECTION('',(1.,0.,0.));
#2907=AXIS2_PLACEMENT_3D('',#2904,#2905,#2906);
#2908=CYLINDRICAL_SURFACE('',#2907,0.888999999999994);
#2909=ORIENTED_EDGE('',*,*,#2899,.F.);
#2910=EDGE_LOOP('',(#2909));
#2911=FACE_BOUND('',#2910,.T.);
#2912=CARTESIAN_POINT('',(22.86,-22.098,5.73405));
#2913=DIRECTION('',(0.,0.,1.));
#2914=DIRECTION('',(1.,0.,0.));
#2915=AXIS2_PLACEMENT_3D('',#2912,#2913,#2914);
#2916=CIRCLE('',#2915,0.88899999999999);
#2917=CARTESIAN_POINT('',(23.749,-22.098,5.73405));
#2918=VERTEX_POINT('',#2917);
#2919=EDGE_CURVE('E690',#2918,#2918,#2916,.T.);
#2920=ORIENTED_EDGE('',*,*,#2919,.T.);
#2921=EDGE_LOOP('',(#2920));
#2922=FACE_BOUND('',#2921,.T.);
#2923=ADVANCED_FACE('F1102',(#2911,#2922),#2908,.F.);
#2924=ORIENTED_EDGE('',*,*,#2919,.F.);
#2925=EDGE_LOOP('',(#2924));
#2926=FACE_BOUND('',#2925,.T.);
#2927=CARTESIAN_POINT('',(22.86,-22.098,5.73405));
#2928=DIRECTION('',(0.,0.,1.));
#2929=DIRECTION('',(1.,0.,0.));
#2930=AXIS2_PLACEMENT_3D('',#2927,#2928,#2929);
#2931=CIRCLE('',#2930,2.032);
#2932=CARTESIAN_POINT('',(24.892,-22.098,5.73405));
#2933=VERTEX_POINT('',#2932);
#2934=EDGE_CURVE('E682',#2933,#2933,#2931,.T.);
#2935=ORIENTED_EDGE('',*,*,#2934,.T.);
#2936=EDGE_LOOP('',(#2935));
#2937=FACE_BOUND('',#2936,.T.);
#2938=ADVANCED_FACE('F1084',(#2926,#2937),#1379,.T.);
#2939=CARTESIAN_POINT('',(22.86,-22.098,5.09905));
#2940=DIRECTION('',(0.,0.,1.));
#2941=DIRECTION('',(1.,0.,0.));
#2942=AXIS2_PLACEMENT_3D('',#2939,#2940,#2941);
#2943=CYLINDRICAL_SURFACE('',#2942,2.032);
#2944=ORIENTED_EDGE('',*,*,#2934,.F.);
#2945=EDGE_LOOP('',(#2944));
#2946=FACE_BOUND('',#2945,.T.);
#2947=ORIENTED_EDGE('',*,*,#2817,.T.);
#2948=EDGE_LOOP('',(#2947));
#2949=FACE_BOUND('',#2948,.T.);
#2950=ADVANCED_FACE('F1030',(#2946,#2949),#2943,.T.);
#2951=CARTESIAN_POINT('',(19.304,-15.58798,-12.68095));
#2952=DIRECTION('',(0.,0.,-1.));
#2953=DIRECTION('',(-1.,0.,0.));
#2954=AXIS2_PLACEMENT_3D('',#2951,#2952,#2953);
#2955=PLANE('',#2954);
#2956=CARTESIAN_POINT('',(19.304,-15.58798,-12.68095));
#2957=DIRECTION('',(0.,0.,1.));
#2958=DIRECTION('',(1.,0.,0.));
#2959=AXIS2_PLACEMENT_3D('',#2956,#2957,#2958);
#2960=CIRCLE('',#2959,2.38124999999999);
#2961=CARTESIAN_POINT('',(21.68525,-15.58798,-12.68095));
#2962=VERTEX_POINT('',#2961);
#2963=EDGE_CURVE('E582',#2962,#2962,#2960,.T.);
#2964=ORIENTED_EDGE('',*,*,#2963,.T.);
#2965=EDGE_LOOP('',(#2964));
#2966=FACE_BOUND('',#2965,.T.);
#2967=ADVANCED_FACE('F1027',(#2966),#2955,.F.);
#2968=CARTESIAN_POINT('',(19.304,-15.58798,5.09905));
#2969=DIRECTION('',(0.,0.,1.));
#2970=DIRECTION('',(1.,0.,0.));
#2971=AXIS2_PLACEMENT_3D('',#2968,#2969,#2970);
#2972=CYLINDRICAL_SURFACE('',#2971,2.38124999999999);
#2973=ORIENTED_EDGE('',*,*,#2963,.F.);
#2974=EDGE_LOOP('',(#2973));
#2975=FACE_BOUND('',#2974,.T.);
#2976=ORIENTED_EDGE('',*,*,#2828,.F.);
#2977=EDGE_LOOP('',(#2976));
#2978=FACE_BOUND('',#2977,.T.);
#2979=ADVANCED_FACE('F1019',(#2975,#2978),#2972,.F.);
#2980=CARTESIAN_POINT('',(-5.23000000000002,-41.49598,-22.6314000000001));
#2981=DIRECTION('',(0.,0.,1.));
#2982=DIRECTION('',(1.,0.,0.));
#2983=AXIS2_PLACEMENT_3D('',#2980,#2981,#2982);
#2984=CYLINDRICAL_SURFACE('',#2983,1.190625);
#2985=CARTESIAN_POINT('',(-4.03937500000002,-41.49598,5.09905));
#2986=CARTESIAN_POINT('',(-4.03937500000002,-41.49598,5.07920625));
#2987=CARTESIAN_POINT('',(-4.03937500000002,-41.49598,5.0593625));
#2988=CARTESIAN_POINT('',(-4.03937500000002,-41.49598,5.019675));
#2989=CARTESIAN_POINT('',(-4.03937500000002,-41.49598,4.99983125));
#2990=CARTESIAN_POINT('',(-4.03937500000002,-41.49598,4.96014375));
#2991=CARTESIAN_POINT('',(-4.03937500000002,-41.49598,4.9403));
#2992=CARTESIAN_POINT('',(-4.03937500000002,-41.49598,4.9006125));
#2993=CARTESIAN_POINT('',(-4.03937500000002,-41.49598,4.88076875));
#2994=CARTESIAN_POINT('',(-4.03937500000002,-41.49598,4.84108125));
#2995=CARTESIAN_POINT('',(-4.03937500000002,-41.49598,4.8212375));
#2996=CARTESIAN_POINT('',(-4.03937500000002,-41.49598,4.78155));
#2997=CARTESIAN_POINT('',(-4.03937500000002,-41.49598,4.76170625));
#2998=CARTESIAN_POINT('',(-4.03937500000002,-41.49598,4.72201875));
#2999=CARTESIAN_POINT('',(-4.03937500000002,-41.49598,4.702175));
#3000=CARTESIAN_POINT('',(-4.03937500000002,-41.49598,4.6624875));
#3001=CARTESIAN_POINT('',(-4.03937500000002,-41.49598,4.64264375));
#3002=CARTESIAN_POINT('',(-4.03937500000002,-41.49598,4.60295625));
#3003=CARTESIAN_POINT('',(-4.03937500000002,-41.49598,4.5831125));
#3004=CARTESIAN_POINT('',(-4.03937500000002,-41.49598,4.543425));
#3005=CARTESIAN_POINT('',(-4.03937500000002,-41.49598,4.52358125));
#3006=CARTESIAN_POINT('',(-4.03937500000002,-41.49598,4.48389375));
#3007=CARTESIAN_POINT('',(-4.03937500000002,-41.49598,4.46405));
#3008=CARTESIAN_POINT('',(-4.03937500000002,-41.49598,4.4243625));
#3009=CARTESIAN_POINT('',(-4.03937500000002,-41.49598,4.40451875));
#3010=CARTESIAN_POINT('',(-4.03937500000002,-41.49598,4.36483125));
#3011=CARTESIAN_POINT('',(-4.03937500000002,-41.49598,4.3449875));
#3012=CARTESIAN_POINT('',(-4.03937500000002,-41.49598,4.3053));
#3013=CARTESIAN_POINT('',(-4.03937500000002,-41.49598,4.28545625));
#3014=CARTESIAN_POINT('',(-4.03937500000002,-41.49598,4.24576875));
#3015=CARTESIAN_POINT('',(-4.03937500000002,-41.49598,4.225925));
#3016=CARTESIAN_POINT('',(-4.03937500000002,-41.49598,4.1862375));
#3017=CARTESIAN_POINT('',(-4.03937500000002,-41.49598,4.16639375));
#3018=CARTESIAN_POINT('',(-4.03937500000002,-41.49598,4.12670625));
#3019=CARTESIAN_POINT('',(-4.03937500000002,-41.49598,4.1068625));
#3020=CARTESIAN_POINT('',(-4.03937500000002,-41.49598,4.067175));
#3021=CARTESIAN_POINT('',(-4.03937500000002,-41.49598,4.04733125));
#3022=CARTESIAN_POINT('',(-4.03937500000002,-41.49598,4.00764375));
#3023=CARTESIAN_POINT('',(-4.03937500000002,-41.49598,3.9878));
#3024=CARTESIAN_POINT('',(-4.03937500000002,-41.49598,3.9481125));
#3025=CARTESIAN_POINT('',(-4.03937500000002,-41.49598,3.92826875));
#3026=CARTESIAN_POINT('',(-4.03937500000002,-41.49598,3.88858125));
#3027=CARTESIAN_POINT('',(-4.03937500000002,-41.49598,3.8687375));
#3028=CARTESIAN_POINT('',(-4.03937500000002,-41.49598,3.82905));
#3029=CARTESIAN_POINT('',(-4.03937500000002,-41.49598,3.80920625));
#3030=CARTESIAN_POINT('',(-4.03937500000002,-41.49598,3.76951875));
#3031=CARTESIAN_POINT('',(-4.03937500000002,-41.49598,3.749675));
#3032=CARTESIAN_POINT('',(-4.03937500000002,-41.49598,3.7099875));
#3033=CARTESIAN_POINT('',(-4.03937500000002,-41.49598,3.69014375));
#3034=CARTESIAN_POINT('',(-4.03937500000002,-41.49598,3.65045625));
#3035=CARTESIAN_POINT('',(-4.03937500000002,-41.49598,3.6306125));
#3036=CARTESIAN_POINT('',(-4.03937500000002,-41.49598,3.590925));
#3037=CARTESIAN_POINT('',(-4.03937500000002,-41.49598,3.57108125));
#3038=CARTESIAN_POINT('',(-4.03937500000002,-41.49598,3.53139375));
#3039=CARTESIAN_POINT('',(-4.03937500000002,-41.49598,3.51155));
#3040=CARTESIAN_POINT('',(-4.03937500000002,-41.49598,3.4718625));
#3041=CARTESIAN_POINT('',(-4.03937500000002,-41.49598,3.45201875));
#3042=CARTESIAN_POINT('',(-4.03937500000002,-41.49598,3.41233125));
#3043=CARTESIAN_POINT('',(-4.03937500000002,-41.49598,3.3924875));
#3044=CARTESIAN_POINT('',(-4.03937500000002,-41.49598,3.3528));
#3045=CARTESIAN_POINT('',(-4.03937500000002,-41.49598,3.33295625));
#3046=CARTESIAN_POINT('',(-4.03937500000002,-41.49598,3.29326875));
#3047=CARTESIAN_POINT('',(-4.03937500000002,-41.49598,3.273425));
#3048=CARTESIAN_POINT('',(-4.03937500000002,-41.49598,3.2337375));
#3049=CARTESIAN_POINT('',(-4.03937500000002,-41.49598,3.21389375));
#3050=CARTESIAN_POINT('',(-4.03937500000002,-41.49598,3.19405));
#3051=B_SPLINE_CURVE_WITH_KNOTS('',3,(#2985,#2986,#2987,#2988,#2989,#2990,#2991,#2992,#2993,
#2994,#2995,#2996,#2997,#2998,#2999,#3000,#3001,#3002,#3003,#3004,#3005,#3006,#3007,#3008,#3009,
#3010,#3011,#3012,#3013,#3014,#3015,#3016,#3017,#3018,#3019,#3020,#3021,#3022,#3023,#3024,#3025,
#3026,#3027,#3028,#3029,#3030,#3031,#3032,#3033,#3034,#3035,#3036,#3037,#3038,#3039,#3040,#3041,
#3042,#3043,#3044,#3045,#3046,#3047,#3048,#3049,#3050),.UNSPECIFIED.,.F.,.F.,(4,2,2,2,2,2,2,2,2,
2,2,2,2,2,2,2,2,2,2,2,2,2,2,2,2,2,2,2,2,2,2,2,4),(0.,0.0595312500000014,0.119062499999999,
0.178593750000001,0.238124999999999,0.29765625,0.357187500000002,0.41671875,0.476250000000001,
0.535781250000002,0.5953125,0.654843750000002,0.714375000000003,0.773906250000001,
0.833437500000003,0.892968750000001,0.952500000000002,1.01203125,1.0715625,1.13109375,1.190625,
1.25015625,1.3096875,1.36921875,1.42875,1.48828125,1.5478125,1.60734375,1.66687500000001,
1.72640625,1.7859375,1.84546875,1.905),.UNSPECIFIED.);
#3052=EDGE_CURVE('BSEAM1015',#175,#2468,#3051,.T.);
#3053=ORIENTED_EDGE('',*,*,#176,.F.);
#3054=ORIENTED_EDGE('',*,*,#2469,.F.);
#3055=ORIENTED_EDGE('',*,*,#3052,.T.);
#3056=ORIENTED_EDGE('',*,*,#3052,.F.);
#3057=EDGE_LOOP('',(#3053,#3055,#3054,#3056));
#3058=FACE_BOUND('',#3057,.T.);
#3059=ADVANCED_FACE('F1015',(#3058),#2984,.F.);
#3060=CARTESIAN_POINT('',(7.77,-41.49598,-22.6314000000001));
#3061=DIRECTION('',(0.,0.,1.));
#3062=DIRECTION('',(1.,0.,0.));
#3063=AXIS2_PLACEMENT_3D('',#3060,#3061,#3062);
#3064=CYLINDRICAL_SURFACE('',#3063,1.190625);
#3065=CARTESIAN_POINT('',(8.960625,-41.49598,5.09905));
#3066=CARTESIAN_POINT('',(8.960625,-41.49598,5.07920625));
#3067=CARTESIAN_POINT('',(8.960625,-41.49598,5.0593625));
#3068=CARTESIAN_POINT('',(8.960625,-41.49598,5.019675));
#3069=CARTESIAN_POINT('',(8.960625,-41.49598,4.99983125));
#3070=CARTESIAN_POINT('',(8.960625,-41.49598,4.96014375));
#3071=CARTESIAN_POINT('',(8.960625,-41.49598,4.9403));
#3072=CARTESIAN_POINT('',(8.960625,-41.49598,4.9006125));
#3073=CARTESIAN_POINT('',(8.960625,-41.49598,4.88076875));
#3074=CARTESIAN_POINT('',(8.960625,-41.49598,4.84108125));
#3075=CARTESIAN_POINT('',(8.960625,-41.49598,4.8212375));
#3076=CARTESIAN_POINT('',(8.960625,-41.49598,4.78155));
#3077=CARTESIAN_POINT('',(8.960625,-41.49598,4.76170625));
#3078=CARTESIAN_POINT('',(8.960625,-41.49598,4.72201875));
#3079=CARTESIAN_POINT('',(8.960625,-41.49598,4.702175));
#3080=CARTESIAN_POINT('',(8.960625,-41.49598,4.6624875));
#3081=CARTESIAN_POINT('',(8.960625,-41.49598,4.64264375));
#3082=CARTESIAN_POINT('',(8.960625,-41.49598,4.60295625));
#3083=CARTESIAN_POINT('',(8.960625,-41.49598,4.5831125));
#3084=CARTESIAN_POINT('',(8.960625,-41.49598,4.543425));
#3085=CARTESIAN_POINT('',(8.960625,-41.49598,4.52358125));
#3086=CARTESIAN_POINT('',(8.960625,-41.49598,4.48389375));
#3087=CARTESIAN_POINT('',(8.960625,-41.49598,4.46405));
#3088=CARTESIAN_POINT('',(8.960625,-41.49598,4.4243625));
#3089=CARTESIAN_POINT('',(8.960625,-41.49598,4.40451875));
#3090=CARTESIAN_POINT('',(8.960625,-41.49598,4.36483125));
#3091=CARTESIAN_POINT('',(8.960625,-41.49598,4.3449875));
#3092=CARTESIAN_POINT('',(8.960625,-41.49598,4.3053));
#3093=CARTESIAN_POINT('',(8.960625,-41.49598,4.28545625));
#3094=CARTESIAN_POINT('',(8.960625,-41.49598,4.24576875));
#3095=CARTESIAN_POINT('',(8.960625,-41.49598,4.225925));
#3096=CARTESIAN_POINT('',(8.960625,-41.49598,4.1862375));
#3097=CARTESIAN_POINT('',(8.960625,-41.49598,4.16639375));
#3098=CARTESIAN_POINT('',(8.960625,-41.49598,4.12670625));
#3099=CARTESIAN_POINT('',(8.960625,-41.49598,4.1068625));
#3100=CARTESIAN_POINT('',(8.960625,-41.49598,4.067175));
#3101=CARTESIAN_POINT('',(8.960625,-41.49598,4.04733125));
#3102=CARTESIAN_POINT('',(8.960625,-41.49598,4.00764375));
#3103=CARTESIAN_POINT('',(8.960625,-41.49598,3.9878));
#3104=CARTESIAN_POINT('',(8.960625,-41.49598,3.9481125));
#3105=CARTESIAN_POINT('',(8.960625,-41.49598,3.92826875));
#3106=CARTESIAN_POINT('',(8.960625,-41.49598,3.88858125));
#3107=CARTESIAN_POINT('',(8.960625,-41.49598,3.8687375));
#3108=CARTESIAN_POINT('',(8.960625,-41.49598,3.82905));
#3109=CARTESIAN_POINT('',(8.960625,-41.49598,3.80920625));
#3110=CARTESIAN_POINT('',(8.960625,-41.49598,3.76951875));
#3111=CARTESIAN_POINT('',(8.960625,-41.49598,3.749675));
#3112=CARTESIAN_POINT('',(8.960625,-41.49598,3.7099875));
#3113=CARTESIAN_POINT('',(8.960625,-41.49598,3.69014375));
#3114=CARTESIAN_POINT('',(8.960625,-41.49598,3.65045625));
#3115=CARTESIAN_POINT('',(8.960625,-41.49598,3.6306125));
#3116=CARTESIAN_POINT('',(8.960625,-41.49598,3.590925));
#3117=CARTESIAN_POINT('',(8.960625,-41.49598,3.57108125));
#3118=CARTESIAN_POINT('',(8.960625,-41.49598,3.53139375));
#3119=CARTESIAN_POINT('',(8.960625,-41.49598,3.51155));
#3120=CARTESIAN_POINT('',(8.960625,-41.49598,3.4718625));
#3121=CARTESIAN_POINT('',(8.960625,-41.49598,3.45201875));
#3122=CARTESIAN_POINT('',(8.960625,-41.49598,3.41233125));
#3123=CARTESIAN_POINT('',(8.960625,-41.49598,3.3924875));
#3124=CARTESIAN_POINT('',(8.960625,-41.49598,3.3528));
#3125=CARTESIAN_POINT('',(8.960625,-41.49598,3.33295625));
#3126=CARTESIAN_POINT('',(8.960625,-41.49598,3.29326875));
#3127=CARTESIAN_POINT('',(8.960625,-41.49598,3.273425));
#3128=CARTESIAN_POINT('',(8.960625,-41.49598,3.2337375));
#3129=CARTESIAN_POINT('',(8.960625,-41.49598,3.21389375));
#3130=CARTESIAN_POINT('',(8.960625,-41.49598,3.19405));
#3131=B_SPLINE_CURVE_WITH_KNOTS('',3,(#3065,#3066,#3067,#3068,#3069,#3070,#3071,#3072,#3073,
#3074,#3075,#3076,#3077,#3078,#3079,#3080,#3081,#3082,#3083,#3084,#3085,#3086,#3087,#3088,#3089,
#3090,#3091,#3092,#3093,#3094,#3095,#3096,#3097,#3098,#3099,#3100,#3101,#3102,#3103,#3104,#3105,
#3106,#3107,#3108,#3109,#3110,#3111,#3112,#3113,#3114,#3115,#3116,#3117,#3118,#3119,#3120,#3121,
#3122,#3123,#3124,#3125,#3126,#3127,#3128,#3129,#3130),.UNSPECIFIED.,.F.,.F.,(4,2,2,2,2,2,2,2,2,
2,2,2,2,2,2,2,2,2,2,2,2,2,2,2,2,2,2,2,2,2,2,2,4),(0.,0.0595312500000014,0.119062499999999,
0.178593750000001,0.238124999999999,0.29765625,0.357187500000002,0.41671875,0.476250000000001,
0.535781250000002,0.5953125,0.654843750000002,0.714375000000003,0.773906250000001,
0.833437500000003,0.892968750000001,0.952500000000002,1.01203125,1.0715625,1.13109375,1.190625,
1.25015625,1.3096875,1.36921875,1.42875,1.48828125,1.5478125,1.60734375,1.66687500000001,
1.72640625,1.7859375,1.84546875,1.905),.UNSPECIFIED.);
#3132=EDGE_CURVE('BSEAM1011',#186,#2457,#3131,.T.);
#3133=ORIENTED_EDGE('',*,*,#187,.F.);
#3134=ORIENTED_EDGE('',*,*,#2458,.F.);
#3135=ORIENTED_EDGE('',*,*,#3132,.T.);
#3136=ORIENTED_EDGE('',*,*,#3132,.F.);
#3137=EDGE_LOOP('',(#3133,#3135,#3134,#3136));
#3138=FACE_BOUND('',#3137,.T.);
#3139=ADVANCED_FACE('F1011',(#3138),#3064,.F.);
#3140=CARTESIAN_POINT('',(-16.51,18.941358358,6.528054));
#3141=DIRECTION('',(0.,0.,-1.));
#3142=DIRECTION('',(-1.,0.,0.));
#3143=AXIS2_PLACEMENT_3D('',#3140,#3141,#3142);
#3144=CYLINDRICAL_SURFACE('',#3143,1.6002);
#3145=CARTESIAN_POINT('',(-16.51,18.941358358,6.528054));
#3146=DIRECTION('',(0.,0.,1.));
#3147=DIRECTION('',(1.,0.,0.));
#3148=AXIS2_PLACEMENT_3D('',#3145,#3146,#3147);
#3149=CIRCLE('',#3148,1.6002);
#3150=CARTESIAN_POINT('',(-14.9098,18.941358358,6.528054));
#3151=VERTEX_POINT('',#3150);
#3152=EDGE_CURVE('E548',#3151,#3151,#3149,.T.);
#3153=ORIENTED_EDGE('',*,*,#3152,.F.);
#3154=EDGE_LOOP('',(#3153));
#3155=FACE_BOUND('',#3154,.T.);
#3156=ORIENTED_EDGE('',*,*,#747,.T.);
#3157=EDGE_LOOP('',(#3156));
#3158=FACE_BOUND('',#3157,.T.);
#3159=ADVANCED_FACE('F1007',(#3155,#3158),#3144,.T.);
#3160=CARTESIAN_POINT('',(-16.51,18.941358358,6.528054));
#3161=DIRECTION('',(0.,0.,1.));
#3162=DIRECTION('',(1.,0.,0.));
#3163=AXIS2_PLACEMENT_3D('',#3160,#3161,#3162);
#3164=PLANE('',#3163);
#3165=CARTESIAN_POINT('',(-16.51,18.941358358,6.528054));
#3166=DIRECTION('',(0.,0.,1.));
#3167=DIRECTION('',(1.,0.,0.));
#3168=AXIS2_PLACEMENT_3D('',#3165,#3166,#3167);
#3169=CIRCLE('',#3168,1.5875);
#3170=CARTESIAN_POINT('',(-14.9225,18.941358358,6.528054));
#3171=VERTEX_POINT('',#3170);
#3172=EDGE_CURVE('E1438',#3171,#3171,#3169,.T.);
#3173=ORIENTED_EDGE('',*,*,#3172,.F.);
#3174=EDGE_LOOP('',(#3173));
#3175=FACE_BOUND('',#3174,.T.);
#3176=ORIENTED_EDGE('',*,*,#3152,.T.);
#3177=EDGE_LOOP('',(#3176));
#3178=FACE_BOUND('',#3177,.T.);
#3179=ADVANCED_FACE('F1003',(#3175,#3178),#3164,.T.);
#3180=CARTESIAN_POINT('',(-16.51,-18.941358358,6.528054));
#3181=DIRECTION('',(0.,0.,-1.));
#3182=DIRECTION('',(-1.,0.,0.));
#3183=AXIS2_PLACEMENT_3D('',#3180,#3181,#3182);
#3184=CYLINDRICAL_SURFACE('',#3183,1.6002);
#3185=CARTESIAN_POINT('',(-16.51,-18.941358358,6.528054));
#3186=DIRECTION('',(0.,0.,-1.));
#3187=DIRECTION('',(1.,0.,0.));
#3188=AXIS2_PLACEMENT_3D('',#3185,#3186,#3187);
#3189=CIRCLE('',#3188,1.6002);
#3190=CARTESIAN_POINT('',(-14.9098,-18.941358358,6.528054));
#3191=VERTEX_POINT('',#3190);
#3192=EDGE_CURVE('E544',#3191,#3191,#3189,.T.);
#3193=ORIENTED_EDGE('',*,*,#3192,.T.);
#3194=EDGE_LOOP('',(#3193));
#3195=FACE_BOUND('',#3194,.T.);
#3196=ORIENTED_EDGE('',*,*,#388,.T.);
#3197=EDGE_LOOP('',(#3196));
#3198=FACE_BOUND('',#3197,.T.);
#3199=ADVANCED_FACE('F999',(#3195,#3198),#3184,.T.);
#3200=CARTESIAN_POINT('',(-16.51,-18.941358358,6.528054));
#3201=DIRECTION('',(0.,0.,1.));
#3202=DIRECTION('',(1.,0.,0.));
#3203=AXIS2_PLACEMENT_3D('',#3200,#3201,#3202);
#3204=PLANE('',#3203);
#3205=CARTESIAN_POINT('',(-16.51,-18.941358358,6.528054));
#3206=DIRECTION('',(0.,0.,1.));
#3207=DIRECTION('',(1.,0.,0.));
#3208=AXIS2_PLACEMENT_3D('',#3205,#3206,#3207);
#3209=CIRCLE('',#3208,1.5875);
#3210=CARTESIAN_POINT('',(-14.9225,-18.941358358,6.528054));
#3211=VERTEX_POINT('',#3210);
#3212=EDGE_CURVE('E1445',#3211,#3211,#3209,.T.);
#3213=ORIENTED_EDGE('',*,*,#3212,.F.);
#3214=EDGE_LOOP('',(#3213));
#3215=FACE_BOUND('',#3214,.T.);
#3216=ORIENTED_EDGE('',*,*,#3192,.F.);
#3217=EDGE_LOOP('',(#3216));
#3218=FACE_BOUND('',#3217,.T.);
#3219=ADVANCED_FACE('F979',(#3215,#3218),#3204,.T.);
#3220=CARTESIAN_POINT('',(9.27099999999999,-36.0635563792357,-12.3011845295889));
#3221=DIRECTION('',(0.,-1.,0.));
#3222=DIRECTION('',(0.,0.,-1.));
#3223=AXIS2_PLACEMENT_3D('',#3220,#3221,#3222);
#3224=PLANE('',#3223);
#3225=ORIENTED_EDGE('',*,*,#2874,.T.);
#3226=DIRECTION('',(0.,0.,1.));
#3227=VECTOR('',#3226,1.);
#3228=CARTESIAN_POINT('',(9.27099999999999,-36.0635563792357,-12.3011845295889));
#3229=LINE('',#3228,#3227);
#3230=EDGE_CURVE('E532',#2867,#222,#3229,.T.);
#3231=ORIENTED_EDGE('',*,*,#3230,.T.);
#3232=ORIENTED_EDGE('',*,*,#223,.T.);
#3233=ORIENTED_EDGE('',*,*,#1438,.F.);
#3234=EDGE_LOOP('',(#3225,#3231,#3232,#3233));
#3235=FACE_BOUND('',#3234,.T.);
#3236=ADVANCED_FACE('F975',(#3235),#3224,.F.);
#3237=CARTESIAN_POINT('',(9.27099999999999,-34.0315563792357,-12.3011845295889));
#3238=DIRECTION('',(0.,0.,1.));
#3239=DIRECTION('',(1.,0.,0.));
#3240=AXIS2_PLACEMENT_3D('',#3237,#3238,#3239);
#3241=CYLINDRICAL_SURFACE('',#3240,2.032);
#3242=ORIENTED_EDGE('',*,*,#2868,.T.);
#3243=DIRECTION('',(0.,0.,1.));
#3244=VECTOR('',#3243,1.);
#3245=CARTESIAN_POINT('',(7.239,-34.0315563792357,-12.3011845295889));
#3246=LINE('',#3245,#3244);
#3247=EDGE_CURVE('E535',#2858,#242,#3246,.T.);
#3248=ORIENTED_EDGE('',*,*,#3247,.T.);
#3249=ORIENTED_EDGE('',*,*,#243,.T.);
#3250=ORIENTED_EDGE('',*,*,#232,.T.);
#3251=ORIENTED_EDGE('',*,*,#3230,.F.);
#3252=EDGE_LOOP('',(#3242,#3248,#3249,#3250,#3251));
#3253=FACE_BOUND('',#3252,.T.);
#3254=ADVANCED_FACE('F978',(#3253),#3241,.F.);
#3255=CARTESIAN_POINT('',(7.239,-34.0315563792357,-12.3011845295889));
#3256=DIRECTION('',(-1.,0.,0.));
#3257=DIRECTION('',(0.,0.,1.));
#3258=AXIS2_PLACEMENT_3D('',#3255,#3256,#3257);
#3259=PLANE('',#3258);
#3260=ORIENTED_EDGE('',*,*,#2859,.T.);
#3261=DIRECTION('',(0.,0.,1.));
#3262=VECTOR('',#3261,1.);
#3263=CARTESIAN_POINT('',(7.239,-21.9094036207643,-12.3011845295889));
#3264=LINE('',#3263,#3262);
#3265=EDGE_CURVE('E537',#2850,#250,#3264,.T.);
#3266=ORIENTED_EDGE('',*,*,#3265,.T.);
#3267=ORIENTED_EDGE('',*,*,#251,.T.);
#3268=ORIENTED_EDGE('',*,*,#3247,.F.);
#3269=EDGE_LOOP('',(#3260,#3266,#3267,#3268));
#3270=FACE_BOUND('',#3269,.T.);
#3271=ADVANCED_FACE('F983',(#3270),#3259,.F.);
#3272=CARTESIAN_POINT('',(9.27099999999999,-21.9094036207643,-12.3011845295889));
#3273=DIRECTION('',(0.,0.,1.));
#3274=DIRECTION('',(1.,0.,0.));
#3275=AXIS2_PLACEMENT_3D('',#3272,#3273,#3274);
#3276=CYLINDRICAL_SURFACE('',#3275,2.032);
#3277=ORIENTED_EDGE('',*,*,#2851,.T.);
#3278=DIRECTION('',(0.,0.,1.));
#3279=VECTOR('',#3278,1.);
#3280=CARTESIAN_POINT('',(9.27099999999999,-19.8774036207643,-12.3011845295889));
#3281=LINE('',#3280,#3279);
#3282=EDGE_CURVE('E540',#2841,#270,#3281,.T.);
#3283=ORIENTED_EDGE('',*,*,#3282,.T.);
#3284=ORIENTED_EDGE('',*,*,#271,.T.);
#3285=ORIENTED_EDGE('',*,*,#260,.T.);
#3286=ORIENTED_EDGE('',*,*,#3265,.F.);
#3287=EDGE_LOOP('',(#3277,#3283,#3284,#3285,#3286));
#3288=FACE_BOUND('',#3287,.T.);
#3289=ADVANCED_FACE('F987',(#3288),#3276,.F.);
#3290=CARTESIAN_POINT('',(9.27099999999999,-19.8774036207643,-12.3011845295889));
#3291=DIRECTION('',(0.,1.,0.));
#3292=DIRECTION('',(0.,0.,1.));
#3293=AXIS2_PLACEMENT_3D('',#3290,#3291,#3292);
#3294=PLANE('',#3293);
#3295=ORIENTED_EDGE('',*,*,#2842,.T.);
#3296=ORIENTED_EDGE('',*,*,#357,.T.);
#3297=ORIENTED_EDGE('',*,*,#279,.T.);
#3298=ORIENTED_EDGE('',*,*,#3282,.F.);
#3299=EDGE_LOOP('',(#3295,#3296,#3297,#3298));
#3300=FACE_BOUND('',#3299,.T.);
#3301=ADVANCED_FACE('F991',(#3300),#3294,.F.);
#3302=CARTESIAN_POINT('',(-1.27,-20.84578,28.3966203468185));
#3303=DIRECTION('',(0.,-1.,0.));
#3304=DIRECTION('',(0.,0.,-1.));
#3305=AXIS2_PLACEMENT_3D('',#3302,#3303,#3304);
#3306=PLANE('',#3305);
#3307=ORIENTED_EDGE('',*,*,#650,.F.);
#3308=DIRECTION('',(0.,0.,-1.));
#3309=VECTOR('',#3308,1.);
#3310=CARTESIAN_POINT('',(-1.27,-20.84578,28.3966203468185));
#3311=LINE('',#3310,#3309);
#3312=EDGE_CURVE('E485',#641,#324,#3311,.T.);
#3313=ORIENTED_EDGE('',*,*,#3312,.T.);
#3314=ORIENTED_EDGE('',*,*,#325,.T.);
#3315=DIRECTION('',(0.,0.,-1.));
#3316=VECTOR('',#3315,1.);
#3317=CARTESIAN_POINT('',(-5.6536886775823,-20.84578,28.3966203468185));
#3318=LINE('',#3317,#3316);
#3319=EDGE_CURVE('E482',#649,#316,#3318,.T.);
#3320=ORIENTED_EDGE('',*,*,#3319,.F.);
#3321=EDGE_LOOP('',(#3307,#3313,#3314,#3320));
#3322=FACE_BOUND('',#3321,.T.);
#3323=ADVANCED_FACE('F995',(#3322),#3306,.F.);
#3324=CARTESIAN_POINT('',(-1.27,-28.03398,28.3966203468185));
#3325=DIRECTION('',(0.,0.,-1.));
#3326=DIRECTION('',(-1.,0.,0.));
#3327=AXIS2_PLACEMENT_3D('',#3324,#3325,#3326);
#3328=CYLINDRICAL_SURFACE('',#3327,7.1882);
#3329=ORIENTED_EDGE('',*,*,#642,.F.);
#3330=DIRECTION('',(0.,0.,-1.));
#3331=VECTOR('',#3330,1.);
#3332=CARTESIAN_POINT('',(-1.27,-35.22218,28.3966203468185));
#3333=LINE('',#3332,#3331);
#3334=EDGE_CURVE('E488',#632,#333,#3333,.T.);
#3335=ORIENTED_EDGE('',*,*,#3334,.T.);
#3336=ORIENTED_EDGE('',*,*,#334,.T.);
#3337=ORIENTED_EDGE('',*,*,#3312,.F.);
#3338=EDGE_LOOP('',(#3329,#3335,#3336,#3337));
#3339=FACE_BOUND('',#3338,.T.);
#3340=ADVANCED_FACE('F1617',(#3339),#3328,.T.);
#3341=CARTESIAN_POINT('',(-1.27,-35.22218,28.3966203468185));
#3342=DIRECTION('',(0.,1.,0.));
#3343=DIRECTION('',(0.,0.,1.));
#3344=AXIS2_PLACEMENT_3D('',#3341,#3342,#3343);
#3345=PLANE('',#3344);
#3346=ORIENTED_EDGE('',*,*,#633,.F.);
#3347=DIRECTION('',(0.,0.,-1.));
#3348=VECTOR('',#3347,1.);
#3349=CARTESIAN_POINT('',(-5.65150000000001,-35.22218,28.3966203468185));
#3350=LINE('',#3349,#3348);
#3351=EDGE_CURVE('E491',#624,#197,#3350,.T.);
#3352=ORIENTED_EDGE('',*,*,#3351,.T.);
#3353=ORIENTED_EDGE('',*,*,#340,.T.);
#3354=ORIENTED_EDGE('',*,*,#3334,.F.);
#3355=EDGE_LOOP('',(#3346,#3352,#3353,#3354));
#3356=FACE_BOUND('',#3355,.T.);
#3357=ADVANCED_FACE('F1613',(#3356),#3345,.F.);
#3358=CARTESIAN_POINT('',(-5.65150000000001,-36.80968,28.3966203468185));
#3359=DIRECTION('',(0.,0.,-1.));
#3360=DIRECTION('',(-1.,0.,0.));
#3361=AXIS2_PLACEMENT_3D('',#3358,#3359,#3360);
#3362=CYLINDRICAL_SURFACE('',#3361,1.5875);
#3363=ORIENTED_EDGE('',*,*,#625,.F.);
#3364=ORIENTED_EDGE('',*,*,#88,.T.);
#3365=ORIENTED_EDGE('',*,*,#198,.T.);
#3366=ORIENTED_EDGE('',*,*,#3351,.F.);
#3367=EDGE_LOOP('',(#3363,#3364,#3365,#3366));
#3368=FACE_BOUND('',#3367,.T.);
#3369=ADVANCED_FACE('F1611',(#3368),#3362,.F.);
#3370=CARTESIAN_POINT('',(-5.6536886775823,-19.25828,28.3966203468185));
#3371=DIRECTION('',(0.,0.,-1.));
#3372=DIRECTION('',(-1.,0.,0.));
#3373=AXIS2_PLACEMENT_3D('',#3370,#3371,#3372);
#3374=CYLINDRICAL_SURFACE('',#3373,1.5875);
#3375=ORIENTED_EDGE('',*,*,#657,.F.);
#3376=ORIENTED_EDGE('',*,*,#3319,.T.);
#3377=ORIENTED_EDGE('',*,*,#317,.T.);
#3378=ORIENTED_EDGE('',*,*,#123,.F.);
#3379=EDGE_LOOP('',(#3375,#3376,#3377,#3378));
#3380=FACE_BOUND('',#3379,.T.);
#3381=ADVANCED_FACE('F1621',(#3380),#3374,.F.);
#3382=CARTESIAN_POINT('',(-4.98474999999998,-43.2749800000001,-6.26745000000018));
#3383=DIRECTION('',(0.,1.,0.));
#3384=DIRECTION('',(0.,0.,1.));
#3385=AXIS2_PLACEMENT_3D('',#3382,#3383,#3384);
#3386=CYLINDRICAL_SURFACE('',#3385,2.38125);
#3387=ORIENTED_EDGE('',*,*,#1870,.T.);
#3388=DIRECTION('',(0.,1.,0.));
#3389=VECTOR('',#3388,1.);
#3390=CARTESIAN_POINT('',(-7.36599999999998,-43.2749800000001,-6.26745000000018));
#3391=LINE('',#3390,#3389);
#3392=EDGE_CURVE('E444',#1869,#2033,#3391,.T.);
#3393=ORIENTED_EDGE('',*,*,#3392,.T.);
#3394=ORIENTED_EDGE('',*,*,#2034,.T.);
#3395=ORIENTED_EDGE('',*,*,#1999,.F.);
#3396=EDGE_LOOP('',(#3387,#3393,#3394,#3395));
#3397=FACE_BOUND('',#3396,.T.);
#3398=ADVANCED_FACE('F1456',(#3397),#3386,.F.);
#3399=CARTESIAN_POINT('',(-7.36599999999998,-43.27498,-14.1033500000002));
#3400=DIRECTION('',(-1.,0.,0.));
#3401=DIRECTION('',(0.,-1.,0.));
#3402=AXIS2_PLACEMENT_3D('',#3399,#3400,#3401);
#3403=PLANE('',#3402);
#3404=ORIENTED_EDGE('',*,*,#1933,.T.);
#3405=DIRECTION('',(0.,1.,0.));
#3406=VECTOR('',#3405,1.);
#3407=CARTESIAN_POINT('',(-7.36599999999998,-43.27498,-14.1033500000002));
#3408=LINE('',#3407,#3406);
#3409=EDGE_CURVE('E436',#1926,#2041,#3408,.T.);
#3410=ORIENTED_EDGE('',*,*,#3409,.T.);
#3411=ORIENTED_EDGE('',*,*,#2042,.T.);
#3412=ORIENTED_EDGE('',*,*,#3392,.F.);
#3413=EDGE_LOOP('',(#3404,#3410,#3411,#3412));
#3414=FACE_BOUND('',#3413,.T.);
#3415=ADVANCED_FACE('F1460',(#3414),#3403,.F.);
#3416=CARTESIAN_POINT('',(-4.98474999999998,-43.27498,-14.1033500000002));
#3417=DIRECTION('',(0.,1.,0.));
#3418=DIRECTION('',(0.,0.,1.));
#3419=AXIS2_PLACEMENT_3D('',#3416,#3417,#3418);
#3420=CYLINDRICAL_SURFACE('',#3419,2.38125);
#3421=ORIENTED_EDGE('',*,*,#1927,.T.);
#3422=ORIENTED_EDGE('',*,*,#2097,.T.);
#3423=ORIENTED_EDGE('',*,*,#2051,.T.);
#3424=ORIENTED_EDGE('',*,*,#3409,.F.);
#3425=EDGE_LOOP('',(#3421,#3422,#3423,#3424));
#3426=FACE_BOUND('',#3425,.T.);
#3427=ADVANCED_FACE('F432',(#3426),#3420,.F.);
#3428=CARTESIAN_POINT('',(-16.51,18.941358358,5.258054));
#3429=DIRECTION('',(0.,0.,1.));
#3430=DIRECTION('',(1.,0.,0.));
#3431=AXIS2_PLACEMENT_3D('',#3428,#3429,#3430);
#3432=PLANE('',#3431);
#3433=CARTESIAN_POINT('',(-16.51,18.941358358,5.258054));
#3434=DIRECTION('',(0.,0.,1.));
#3435=DIRECTION('',(1.,0.,0.));
#3436=AXIS2_PLACEMENT_3D('',#3433,#3434,#3435);
#3437=CIRCLE('',#3436,1.5875);
#3438=CARTESIAN_POINT('',(-14.9225,18.941358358,5.258054));
#3439=VERTEX_POINT('',#3438);
#3440=EDGE_CURVE('E1434',#3439,#3439,#3437,.T.);
#3441=ORIENTED_EDGE('',*,*,#3440,.T.);
#3442=EDGE_LOOP('',(#3441));
#3443=FACE_BOUND('',#3442,.T.);
#3444=ORIENTED_EDGE('',*,*,#70,.T.);
#3445=EDGE_LOOP('',(#3444));
#3446=FACE_BOUND('',#3445,.T.);
#3447=ADVANCED_FACE('F1830',(#3443,#3446),#3432,.T.);
#3448=CARTESIAN_POINT('',(-16.51,18.941358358,5.258054));
#3449=DIRECTION('',(0.,0.,1.));
#3450=DIRECTION('',(1.,0.,0.));
#3451=AXIS2_PLACEMENT_3D('',#3448,#3449,#3450);
#3452=CYLINDRICAL_SURFACE('',#3451,1.5875);
#3453=ORIENTED_EDGE('',*,*,#3440,.F.);
#3454=EDGE_LOOP('',(#3453));
#3455=FACE_BOUND('',#3454,.T.);
#3456=ORIENTED_EDGE('',*,*,#3172,.T.);
#3457=EDGE_LOOP('',(#3456));
#3458=FACE_BOUND('',#3457,.T.);
#3459=ADVANCED_FACE('F1844',(#3455,#3458),#3452,.F.);
#3460=CARTESIAN_POINT('',(-16.51,-18.941358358,5.258054));
#3461=DIRECTION('',(0.,0.,1.));
#3462=DIRECTION('',(1.,0.,0.));
#3463=AXIS2_PLACEMENT_3D('',#3460,#3461,#3462);
#3464=PLANE('',#3463);
#3465=CARTESIAN_POINT('',(-16.51,-18.941358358,5.258054));
#3466=DIRECTION('',(0.,0.,1.));
#3467=DIRECTION('',(1.,0.,0.));
#3468=AXIS2_PLACEMENT_3D('',#3465,#3466,#3467);
#3469=CIRCLE('',#3468,1.5875);
#3470=CARTESIAN_POINT('',(-14.9225,-18.941358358,5.258054));
#3471=VERTEX_POINT('',#3470);
#3472=EDGE_CURVE('E1892',#3471,#3471,#3469,.T.);
#3473=ORIENTED_EDGE('',*,*,#3472,.T.);
#3474=EDGE_LOOP('',(#3473));
#3475=FACE_BOUND('',#3474,.T.);
#3476=ORIENTED_EDGE('',*,*,#42,.T.);
#3477=EDGE_LOOP('',(#3476));
#3478=FACE_BOUND('',#3477,.T.);
#3479=ADVANCED_FACE('F1852',(#3475,#3478),#3464,.T.);
#3480=CARTESIAN_POINT('',(-16.51,-18.941358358,5.258054));
#3481=DIRECTION('',(0.,0.,1.));
#3482=DIRECTION('',(1.,0.,0.));
#3483=AXIS2_PLACEMENT_3D('',#3480,#3481,#3482);
#3484=CYLINDRICAL_SURFACE('',#3483,1.5875);
#3485=ORIENTED_EDGE('',*,*,#3472,.F.);
#3486=EDGE_LOOP('',(#3485));
#3487=FACE_BOUND('',#3486,.T.);
#3488=ORIENTED_EDGE('',*,*,#3212,.T.);
#3489=EDGE_LOOP('',(#3488));
#3490=FACE_BOUND('',#3489,.T.);
#3491=ADVANCED_FACE('F1866',(#3487,#3490),#3484,.F.);
#3492=CLOSED_SHELL('',(#46,#74,#114,#141,#344,#375,#762,#818,#881,#914,#936,#1374,#1402,#1425,
#1467,#1555,#1586,#1606,#1637,#1659,#1681,#1705,#1728,#1759,#1771,#1809,#1821,#1844,#1937,#1961,
#1985,#2009,#2086,#2108,#2120,#2137,#2171,#2191,#2200,#2220,#2233,#2245,#2266,#2276,#2288,#2300,
#2312,#2324,#2336,#2348,#2374,#2396,#2418,#2445,#2506,#2518,#2530,#2542,#2554,#2566,#2578,#2590,
#2602,#2614,#2634,#2646,#2658,#2670,#2685,#2697,#2709,#2721,#2733,#2745,#2757,#2769,#2792,#2804,
#2882,#2903,#2923,#2938,#2950,#2967,#2979,#3059,#3139,#3159,#3179,#3199,#3219,#3236,#3254,#3271,
#3289,#3301,#3323,#3340,#3357,#3369,#3381,#3398,#3415,#3427,#3447,#3459,#3479,#3491));
#3493=MANIFOLD_SOLID_BREP('B2',#3492);
#3494=ADVANCED_BREP_SHAPE_REPRESENTATION('',(#18,#3493),#14);
#3495=SHAPE_DEFINITION_REPRESENTATION(#9,#3494);
ENDSEC;
END-ISO-10303-21;
